VERSION 5.8 ;
BUSBITCHARS "[]" ;
DIVIDERCHAR "/" ;
UNITS
    DATABASE MICRONS 1000 ;
END UNITS

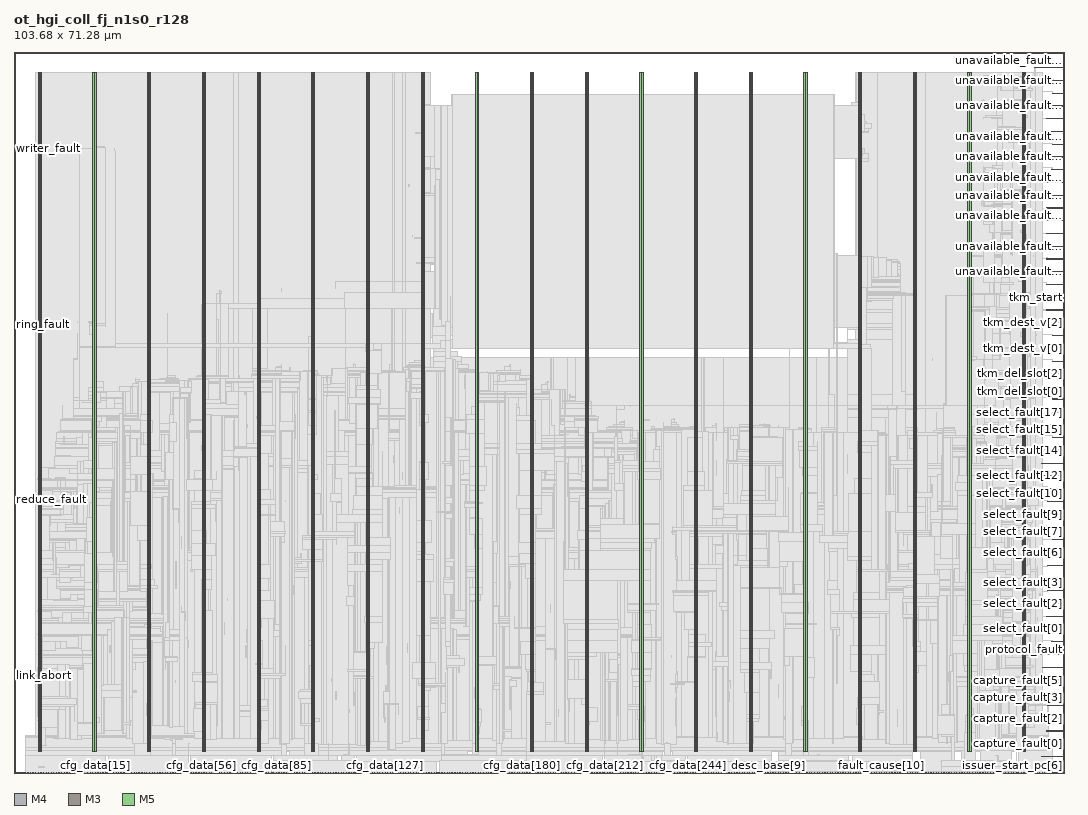
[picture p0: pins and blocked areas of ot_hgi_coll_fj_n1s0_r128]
MACRO ot_hgi_coll_fj_n1s0_r128
  FOREIGN ot_hgi_coll_fj_n1s0_r128 0 0 ;
  CLASS BLOCK ;
  SIZE 103.68 BY 71.28 ;
  PIN arg_capture_slot
    DIRECTION INPUT ;
    USE SIGNAL ;
    PORT
      LAYER M4 ;
        RECT  103.596 1.632 103.68 1.656 ;
    END
    PORT
      LAYER M4 ;
        RECT  101.437 1.632 103.644 1.656 ;
    END
  END arg_capture_slot
  PIN capture_fault[0]
    DIRECTION INPUT ;
    USE SIGNAL ;
    PORT
      LAYER M4 ;
        RECT  103.596 2.88 103.68 2.904 ;
    END
    PORT
      LAYER M4 ;
        RECT  102.013 2.88 103.644 2.904 ;
    END
  END capture_fault[0]
  PIN capture_fault[1]
    DIRECTION INPUT ;
    USE SIGNAL ;
    PORT
      LAYER M4 ;
        RECT  103.596 4.128 103.68 4.152 ;
    END
    PORT
      LAYER M4 ;
        RECT  101.977 4.128 103.644 4.152 ;
    END
  END capture_fault[1]
  PIN capture_fault[2]
    DIRECTION INPUT ;
    USE SIGNAL ;
    PORT
      LAYER M4 ;
        RECT  103.596 5.376 103.68 5.4 ;
    END
    PORT
      LAYER M4 ;
        RECT  102.553 5.376 103.644 5.4 ;
    END
  END capture_fault[2]
  PIN capture_fault[3]
    DIRECTION INPUT ;
    USE SIGNAL ;
    PORT
      LAYER M4 ;
        RECT  103.596 6.672 103.68 6.696 ;
    END
    PORT
      LAYER M4 ;
        RECT  102.013 6.672 103.644 6.696 ;
    END
  END capture_fault[3]
  PIN capture_fault[4]
    DIRECTION INPUT ;
    USE SIGNAL ;
    PORT
      LAYER M4 ;
        RECT  103.596 7.92 103.68 7.944 ;
    END
    PORT
      LAYER M4 ;
        RECT  101.977 7.92 103.644 7.944 ;
    END
  END capture_fault[4]
  PIN capture_fault[5]
    DIRECTION INPUT ;
    USE SIGNAL ;
    PORT
      LAYER M4 ;
        RECT  103.596 9.168 103.68 9.192 ;
    END
    PORT
      LAYER M4 ;
        RECT  101.905 9.168 103.644 9.192 ;
    END
  END capture_fault[5]
  PIN capture_fault[6]
    DIRECTION INPUT ;
    USE SIGNAL ;
    PORT
      LAYER M4 ;
        RECT  103.596 10.416 103.68 10.44 ;
    END
    PORT
      LAYER M4 ;
        RECT  101.509 10.416 103.644 10.44 ;
    END
  END capture_fault[6]
  PIN capture_fault[7]
    DIRECTION INPUT ;
    USE SIGNAL ;
    PORT
      LAYER M4 ;
        RECT  103.596 11.712 103.68 11.736 ;
    END
    PORT
      LAYER M4 ;
        RECT  101.365 11.712 103.644 11.736 ;
    END
  END capture_fault[7]
  PIN cfg_addr[0]
    DIRECTION INPUT ;
    USE SIGNAL ;
    PORT
      LAYER M3 ;
        RECT  1.116 0 1.134 0.038 ;
    END
  END cfg_addr[0]
  PIN cfg_addr[10]
    DIRECTION INPUT ;
    USE SIGNAL ;
    PORT
      LAYER M3 ;
        RECT  3.672 0 3.69 0.038 ;
    END
  END cfg_addr[10]
  PIN cfg_addr[11]
    DIRECTION INPUT ;
    USE SIGNAL ;
    PORT
      LAYER M3 ;
        RECT  3.924 0 3.942 0.038 ;
    END
  END cfg_addr[11]
  PIN cfg_addr[1]
    DIRECTION INPUT ;
    USE SIGNAL ;
    PORT
      LAYER M3 ;
        RECT  1.368 0 1.386 0.038 ;
    END
  END cfg_addr[1]
  PIN cfg_addr[2]
    DIRECTION INPUT ;
    USE SIGNAL ;
    PORT
      LAYER M3 ;
        RECT  1.62 0 1.638 0.038 ;
    END
  END cfg_addr[2]
  PIN cfg_addr[3]
    DIRECTION INPUT ;
    USE SIGNAL ;
    PORT
      LAYER M3 ;
        RECT  1.872 0 1.89 0.038 ;
    END
  END cfg_addr[3]
  PIN cfg_addr[4]
    DIRECTION INPUT ;
    USE SIGNAL ;
    PORT
      LAYER M3 ;
        RECT  2.124 0 2.142 0.038 ;
    END
  END cfg_addr[4]
  PIN cfg_addr[5]
    DIRECTION INPUT ;
    USE SIGNAL ;
    PORT
      LAYER M3 ;
        RECT  2.412 0 2.43 0.038 ;
    END
  END cfg_addr[5]
  PIN cfg_addr[6]
    DIRECTION INPUT ;
    USE SIGNAL ;
    PORT
      LAYER M3 ;
        RECT  2.664 0 2.682 0.038 ;
    END
  END cfg_addr[6]
  PIN cfg_addr[7]
    DIRECTION INPUT ;
    USE SIGNAL ;
    PORT
      LAYER M3 ;
        RECT  2.916 0 2.934 0.038 ;
    END
  END cfg_addr[7]
  PIN cfg_addr[8]
    DIRECTION INPUT ;
    USE SIGNAL ;
    PORT
      LAYER M3 ;
        RECT  3.168 0 3.186 0.038 ;
    END
  END cfg_addr[8]
  PIN cfg_addr[9]
    DIRECTION INPUT ;
    USE SIGNAL ;
    PORT
      LAYER M3 ;
        RECT  3.42 0 3.438 0.038 ;
    END
  END cfg_addr[9]
  PIN cfg_data[0]
    DIRECTION INPUT ;
    USE SIGNAL ;
    PORT
      LAYER M3 ;
        RECT  4.176 0 4.194 0.038 ;
    END
  END cfg_data[0]
  PIN cfg_data[100]
    DIRECTION INPUT ;
    USE SIGNAL ;
    PORT
      LAYER M5 ;
        RECT  29.712 0 29.736 0.084 ;
    END
  END cfg_data[100]
  PIN cfg_data[101]
    DIRECTION INPUT ;
    USE SIGNAL ;
    PORT
      LAYER M5 ;
        RECT  30 0 30.024 0.084 ;
    END
  END cfg_data[101]
  PIN cfg_data[102]
    DIRECTION INPUT ;
    USE SIGNAL ;
    PORT
      LAYER M5 ;
        RECT  30.24 0 30.264 0.084 ;
    END
  END cfg_data[102]
  PIN cfg_data[103]
    DIRECTION INPUT ;
    USE SIGNAL ;
    PORT
      LAYER M5 ;
        RECT  30.48 0 30.504 0.084 ;
    END
  END cfg_data[103]
  PIN cfg_data[104]
    DIRECTION INPUT ;
    USE SIGNAL ;
    PORT
      LAYER M5 ;
        RECT  30.768 0 30.792 0.084 ;
    END
  END cfg_data[104]
  PIN cfg_data[105]
    DIRECTION INPUT ;
    USE SIGNAL ;
    PORT
      LAYER M5 ;
        RECT  31.008 0 31.032 0.084 ;
    END
  END cfg_data[105]
  PIN cfg_data[106]
    DIRECTION INPUT ;
    USE SIGNAL ;
    PORT
      LAYER M5 ;
        RECT  31.248 0 31.272 0.084 ;
    END
  END cfg_data[106]
  PIN cfg_data[107]
    DIRECTION INPUT ;
    USE SIGNAL ;
    PORT
      LAYER M5 ;
        RECT  31.536 0 31.56 0.084 ;
    END
  END cfg_data[107]
  PIN cfg_data[108]
    DIRECTION INPUT ;
    USE SIGNAL ;
    PORT
      LAYER M5 ;
        RECT  31.776 0 31.8 0.084 ;
    END
  END cfg_data[108]
  PIN cfg_data[109]
    DIRECTION INPUT ;
    USE SIGNAL ;
    PORT
      LAYER M5 ;
        RECT  32.016 0 32.04 0.084 ;
    END
  END cfg_data[109]
  PIN cfg_data[10]
    DIRECTION INPUT ;
    USE SIGNAL ;
    PORT
      LAYER M3 ;
        RECT  6.732 0 6.75 0.038 ;
    END
  END cfg_data[10]
  PIN cfg_data[110]
    DIRECTION INPUT ;
    USE SIGNAL ;
    PORT
      LAYER M5 ;
        RECT  32.304 0 32.328 0.084 ;
    END
  END cfg_data[110]
  PIN cfg_data[111]
    DIRECTION INPUT ;
    USE SIGNAL ;
    PORT
      LAYER M5 ;
        RECT  32.544 0 32.568 0.084 ;
    END
  END cfg_data[111]
  PIN cfg_data[112]
    DIRECTION INPUT ;
    USE SIGNAL ;
    PORT
      LAYER M5 ;
        RECT  32.784 0 32.808 0.084 ;
    END
  END cfg_data[112]
  PIN cfg_data[113]
    DIRECTION INPUT ;
    USE SIGNAL ;
    PORT
      LAYER M5 ;
        RECT  33.072 0 33.096 0.084 ;
    END
  END cfg_data[113]
  PIN cfg_data[114]
    DIRECTION INPUT ;
    USE SIGNAL ;
    PORT
      LAYER M5 ;
        RECT  33.312 0 33.336 0.084 ;
    END
  END cfg_data[114]
  PIN cfg_data[115]
    DIRECTION INPUT ;
    USE SIGNAL ;
    PORT
      LAYER M5 ;
        RECT  33.552 0 33.576 0.084 ;
    END
  END cfg_data[115]
  PIN cfg_data[116]
    DIRECTION INPUT ;
    USE SIGNAL ;
    PORT
      LAYER M3 ;
        RECT  33.804 0 33.822 0.038 ;
    END
  END cfg_data[116]
  PIN cfg_data[117]
    DIRECTION INPUT ;
    USE SIGNAL ;
    PORT
      LAYER M3 ;
        RECT  34.092 0 34.11 0.038 ;
    END
  END cfg_data[117]
  PIN cfg_data[118]
    DIRECTION INPUT ;
    USE SIGNAL ;
    PORT
      LAYER M3 ;
        RECT  34.344 0 34.362 0.038 ;
    END
  END cfg_data[118]
  PIN cfg_data[119]
    DIRECTION INPUT ;
    USE SIGNAL ;
    PORT
      LAYER M3 ;
        RECT  34.596 0 34.614 0.038 ;
    END
  END cfg_data[119]
  PIN cfg_data[11]
    DIRECTION INPUT ;
    USE SIGNAL ;
    PORT
      LAYER M3 ;
        RECT  6.984 0 7.002 0.038 ;
    END
  END cfg_data[11]
  PIN cfg_data[120]
    DIRECTION INPUT ;
    USE SIGNAL ;
    PORT
      LAYER M3 ;
        RECT  34.848 0 34.866 0.038 ;
    END
  END cfg_data[120]
  PIN cfg_data[121]
    DIRECTION INPUT ;
    USE SIGNAL ;
    PORT
      LAYER M3 ;
        RECT  35.1 0 35.118 0.038 ;
    END
  END cfg_data[121]
  PIN cfg_data[122]
    DIRECTION INPUT ;
    USE SIGNAL ;
    PORT
      LAYER M3 ;
        RECT  35.352 0 35.37 0.038 ;
    END
  END cfg_data[122]
  PIN cfg_data[123]
    DIRECTION INPUT ;
    USE SIGNAL ;
    PORT
      LAYER M3 ;
        RECT  35.604 0 35.622 0.038 ;
    END
  END cfg_data[123]
  PIN cfg_data[124]
    DIRECTION INPUT ;
    USE SIGNAL ;
    PORT
      LAYER M3 ;
        RECT  35.856 0 35.874 0.038 ;
    END
  END cfg_data[124]
  PIN cfg_data[125]
    DIRECTION INPUT ;
    USE SIGNAL ;
    PORT
      LAYER M3 ;
        RECT  36.108 0 36.126 0.038 ;
    END
  END cfg_data[125]
  PIN cfg_data[126]
    DIRECTION INPUT ;
    USE SIGNAL ;
    PORT
      LAYER M3 ;
        RECT  36.36 0 36.378 0.038 ;
    END
  END cfg_data[126]
  PIN cfg_data[127]
    DIRECTION INPUT ;
    USE SIGNAL ;
    PORT
      LAYER M3 ;
        RECT  36.648 0 36.666 0.038 ;
    END
  END cfg_data[127]
  PIN cfg_data[128]
    DIRECTION INPUT ;
    USE SIGNAL ;
    PORT
      LAYER M3 ;
        RECT  36.9 0 36.918 0.038 ;
    END
  END cfg_data[128]
  PIN cfg_data[129]
    DIRECTION INPUT ;
    USE SIGNAL ;
    PORT
      LAYER M3 ;
        RECT  37.152 0 37.17 0.038 ;
    END
  END cfg_data[129]
  PIN cfg_data[12]
    DIRECTION INPUT ;
    USE SIGNAL ;
    PORT
      LAYER M3 ;
        RECT  7.236 0 7.254 0.038 ;
    END
  END cfg_data[12]
  PIN cfg_data[130]
    DIRECTION INPUT ;
    USE SIGNAL ;
    PORT
      LAYER M3 ;
        RECT  37.404 0 37.422 0.038 ;
    END
  END cfg_data[130]
  PIN cfg_data[131]
    DIRECTION INPUT ;
    USE SIGNAL ;
    PORT
      LAYER M3 ;
        RECT  37.656 0 37.674 0.038 ;
    END
  END cfg_data[131]
  PIN cfg_data[132]
    DIRECTION INPUT ;
    USE SIGNAL ;
    PORT
      LAYER M3 ;
        RECT  37.908 0 37.926 0.038 ;
    END
  END cfg_data[132]
  PIN cfg_data[133]
    DIRECTION INPUT ;
    USE SIGNAL ;
    PORT
      LAYER M3 ;
        RECT  38.16 0 38.178 0.038 ;
    END
  END cfg_data[133]
  PIN cfg_data[134]
    DIRECTION INPUT ;
    USE SIGNAL ;
    PORT
      LAYER M3 ;
        RECT  38.412 0 38.43 0.038 ;
    END
  END cfg_data[134]
  PIN cfg_data[135]
    DIRECTION INPUT ;
    USE SIGNAL ;
    PORT
      LAYER M3 ;
        RECT  38.664 0 38.682 0.038 ;
    END
  END cfg_data[135]
  PIN cfg_data[136]
    DIRECTION INPUT ;
    USE SIGNAL ;
    PORT
      LAYER M3 ;
        RECT  38.916 0 38.934 0.038 ;
    END
  END cfg_data[136]
  PIN cfg_data[137]
    DIRECTION INPUT ;
    USE SIGNAL ;
    PORT
      LAYER M3 ;
        RECT  39.168 0 39.186 0.038 ;
    END
  END cfg_data[137]
  PIN cfg_data[138]
    DIRECTION INPUT ;
    USE SIGNAL ;
    PORT
      LAYER M3 ;
        RECT  39.456 0 39.474 0.038 ;
    END
  END cfg_data[138]
  PIN cfg_data[139]
    DIRECTION INPUT ;
    USE SIGNAL ;
    PORT
      LAYER M3 ;
        RECT  39.708 0 39.726 0.038 ;
    END
  END cfg_data[139]
  PIN cfg_data[13]
    DIRECTION INPUT ;
    USE SIGNAL ;
    PORT
      LAYER M3 ;
        RECT  7.524 0 7.542 0.038 ;
    END
  END cfg_data[13]
  PIN cfg_data[140]
    DIRECTION INPUT ;
    USE SIGNAL ;
    PORT
      LAYER M3 ;
        RECT  39.96 0 39.978 0.038 ;
    END
  END cfg_data[140]
  PIN cfg_data[141]
    DIRECTION INPUT ;
    USE SIGNAL ;
    PORT
      LAYER M3 ;
        RECT  40.212 0 40.23 0.038 ;
    END
  END cfg_data[141]
  PIN cfg_data[142]
    DIRECTION INPUT ;
    USE SIGNAL ;
    PORT
      LAYER M3 ;
        RECT  40.464 0 40.482 0.038 ;
    END
  END cfg_data[142]
  PIN cfg_data[143]
    DIRECTION INPUT ;
    USE SIGNAL ;
    PORT
      LAYER M3 ;
        RECT  40.716 0 40.734 0.038 ;
    END
  END cfg_data[143]
  PIN cfg_data[144]
    DIRECTION INPUT ;
    USE SIGNAL ;
    PORT
      LAYER M3 ;
        RECT  40.968 0 40.986 0.038 ;
    END
  END cfg_data[144]
  PIN cfg_data[145]
    DIRECTION INPUT ;
    USE SIGNAL ;
    PORT
      LAYER M3 ;
        RECT  41.22 0 41.238 0.038 ;
    END
  END cfg_data[145]
  PIN cfg_data[146]
    DIRECTION INPUT ;
    USE SIGNAL ;
    PORT
      LAYER M3 ;
        RECT  41.472 0 41.49 0.038 ;
    END
  END cfg_data[146]
  PIN cfg_data[147]
    DIRECTION INPUT ;
    USE SIGNAL ;
    PORT
      LAYER M3 ;
        RECT  41.724 0 41.742 0.038 ;
    END
  END cfg_data[147]
  PIN cfg_data[148]
    DIRECTION INPUT ;
    USE SIGNAL ;
    PORT
      LAYER M5 ;
        RECT  42 0 42.024 0.084 ;
    END
  END cfg_data[148]
  PIN cfg_data[149]
    DIRECTION INPUT ;
    USE SIGNAL ;
    PORT
      LAYER M5 ;
        RECT  42.24 0 42.264 0.084 ;
    END
  END cfg_data[149]
  PIN cfg_data[14]
    DIRECTION INPUT ;
    USE SIGNAL ;
    PORT
      LAYER M3 ;
        RECT  7.776 0 7.794 0.038 ;
    END
  END cfg_data[14]
  PIN cfg_data[150]
    DIRECTION INPUT ;
    USE SIGNAL ;
    PORT
      LAYER M5 ;
        RECT  42.48 0 42.504 0.084 ;
    END
  END cfg_data[150]
  PIN cfg_data[151]
    DIRECTION INPUT ;
    USE SIGNAL ;
    PORT
      LAYER M5 ;
        RECT  42.768 0 42.792 0.084 ;
    END
  END cfg_data[151]
  PIN cfg_data[152]
    DIRECTION INPUT ;
    USE SIGNAL ;
    PORT
      LAYER M5 ;
        RECT  43.008 0 43.032 0.084 ;
    END
  END cfg_data[152]
  PIN cfg_data[153]
    DIRECTION INPUT ;
    USE SIGNAL ;
    PORT
      LAYER M5 ;
        RECT  43.248 0 43.272 0.084 ;
    END
  END cfg_data[153]
  PIN cfg_data[154]
    DIRECTION INPUT ;
    USE SIGNAL ;
    PORT
      LAYER M5 ;
        RECT  43.536 0 43.56 0.084 ;
    END
  END cfg_data[154]
  PIN cfg_data[155]
    DIRECTION INPUT ;
    USE SIGNAL ;
    PORT
      LAYER M5 ;
        RECT  43.776 0 43.8 0.084 ;
    END
  END cfg_data[155]
  PIN cfg_data[156]
    DIRECTION INPUT ;
    USE SIGNAL ;
    PORT
      LAYER M5 ;
        RECT  44.016 0 44.04 0.084 ;
    END
  END cfg_data[156]
  PIN cfg_data[157]
    DIRECTION INPUT ;
    USE SIGNAL ;
    PORT
      LAYER M5 ;
        RECT  44.304 0 44.328 0.084 ;
    END
  END cfg_data[157]
  PIN cfg_data[158]
    DIRECTION INPUT ;
    USE SIGNAL ;
    PORT
      LAYER M5 ;
        RECT  44.544 0 44.568 0.084 ;
    END
  END cfg_data[158]
  PIN cfg_data[159]
    DIRECTION INPUT ;
    USE SIGNAL ;
    PORT
      LAYER M5 ;
        RECT  44.784 0 44.808 0.084 ;
    END
  END cfg_data[159]
  PIN cfg_data[15]
    DIRECTION INPUT ;
    USE SIGNAL ;
    PORT
      LAYER M3 ;
        RECT  8.028 0 8.046 0.038 ;
    END
  END cfg_data[15]
  PIN cfg_data[160]
    DIRECTION INPUT ;
    USE SIGNAL ;
    PORT
      LAYER M5 ;
        RECT  45.072 0 45.096 0.084 ;
    END
  END cfg_data[160]
  PIN cfg_data[161]
    DIRECTION INPUT ;
    USE SIGNAL ;
    PORT
      LAYER M5 ;
        RECT  45.312 0 45.336 0.084 ;
    END
  END cfg_data[161]
  PIN cfg_data[162]
    DIRECTION INPUT ;
    USE SIGNAL ;
    PORT
      LAYER M5 ;
        RECT  45.552 0 45.576 0.084 ;
    END
  END cfg_data[162]
  PIN cfg_data[163]
    DIRECTION INPUT ;
    USE SIGNAL ;
    PORT
      LAYER M5 ;
        RECT  45.84 0 45.864 0.084 ;
    END
  END cfg_data[163]
  PIN cfg_data[164]
    DIRECTION INPUT ;
    USE SIGNAL ;
    PORT
      LAYER M5 ;
        RECT  46.08 0 46.104 0.084 ;
    END
  END cfg_data[164]
  PIN cfg_data[165]
    DIRECTION INPUT ;
    USE SIGNAL ;
    PORT
      LAYER M5 ;
        RECT  46.32 0 46.344 0.084 ;
    END
  END cfg_data[165]
  PIN cfg_data[166]
    DIRECTION INPUT ;
    USE SIGNAL ;
    PORT
      LAYER M5 ;
        RECT  46.608 0 46.632 0.084 ;
    END
  END cfg_data[166]
  PIN cfg_data[167]
    DIRECTION INPUT ;
    USE SIGNAL ;
    PORT
      LAYER M5 ;
        RECT  46.848 0 46.872 0.084 ;
    END
  END cfg_data[167]
  PIN cfg_data[168]
    DIRECTION INPUT ;
    USE SIGNAL ;
    PORT
      LAYER M5 ;
        RECT  47.088 0 47.112 0.084 ;
    END
  END cfg_data[168]
  PIN cfg_data[169]
    DIRECTION INPUT ;
    USE SIGNAL ;
    PORT
      LAYER M5 ;
        RECT  47.376 0 47.4 0.084 ;
    END
  END cfg_data[169]
  PIN cfg_data[16]
    DIRECTION INPUT ;
    USE SIGNAL ;
    PORT
      LAYER M3 ;
        RECT  8.28 0 8.298 0.038 ;
    END
  END cfg_data[16]
  PIN cfg_data[170]
    DIRECTION INPUT ;
    USE SIGNAL ;
    PORT
      LAYER M5 ;
        RECT  47.616 0 47.64 0.084 ;
    END
  END cfg_data[170]
  PIN cfg_data[171]
    DIRECTION INPUT ;
    USE SIGNAL ;
    PORT
      LAYER M5 ;
        RECT  47.856 0 47.88 0.084 ;
    END
  END cfg_data[171]
  PIN cfg_data[172]
    DIRECTION INPUT ;
    USE SIGNAL ;
    PORT
      LAYER M5 ;
        RECT  48.144 0 48.168 0.084 ;
    END
  END cfg_data[172]
  PIN cfg_data[173]
    DIRECTION INPUT ;
    USE SIGNAL ;
    PORT
      LAYER M5 ;
        RECT  48.384 0 48.408 0.084 ;
    END
  END cfg_data[173]
  PIN cfg_data[174]
    DIRECTION INPUT ;
    USE SIGNAL ;
    PORT
      LAYER M5 ;
        RECT  48.624 0 48.648 0.084 ;
    END
  END cfg_data[174]
  PIN cfg_data[175]
    DIRECTION INPUT ;
    USE SIGNAL ;
    PORT
      LAYER M5 ;
        RECT  48.912 0 48.936 0.084 ;
    END
  END cfg_data[175]
  PIN cfg_data[176]
    DIRECTION INPUT ;
    USE SIGNAL ;
    PORT
      LAYER M5 ;
        RECT  49.152 0 49.176 0.084 ;
    END
  END cfg_data[176]
  PIN cfg_data[177]
    DIRECTION INPUT ;
    USE SIGNAL ;
    PORT
      LAYER M5 ;
        RECT  49.392 0 49.416 0.084 ;
    END
  END cfg_data[177]
  PIN cfg_data[178]
    DIRECTION INPUT ;
    USE SIGNAL ;
    PORT
      LAYER M5 ;
        RECT  49.68 0 49.704 0.084 ;
    END
  END cfg_data[178]
  PIN cfg_data[179]
    DIRECTION INPUT ;
    USE SIGNAL ;
    PORT
      LAYER M5 ;
        RECT  49.92 0 49.944 0.084 ;
    END
  END cfg_data[179]
  PIN cfg_data[17]
    DIRECTION INPUT ;
    USE SIGNAL ;
    PORT
      LAYER M3 ;
        RECT  8.532 0 8.55 0.038 ;
    END
  END cfg_data[17]
  PIN cfg_data[180]
    DIRECTION INPUT ;
    USE SIGNAL ;
    PORT
      LAYER M3 ;
        RECT  50.184 0 50.202 0.038 ;
    END
  END cfg_data[180]
  PIN cfg_data[181]
    DIRECTION INPUT ;
    USE SIGNAL ;
    PORT
      LAYER M3 ;
        RECT  50.436 0 50.454 0.038 ;
    END
  END cfg_data[181]
  PIN cfg_data[182]
    DIRECTION INPUT ;
    USE SIGNAL ;
    PORT
      LAYER M3 ;
        RECT  50.688 0 50.706 0.038 ;
    END
  END cfg_data[182]
  PIN cfg_data[183]
    DIRECTION INPUT ;
    USE SIGNAL ;
    PORT
      LAYER M3 ;
        RECT  50.94 0 50.958 0.038 ;
    END
  END cfg_data[183]
  PIN cfg_data[184]
    DIRECTION INPUT ;
    USE SIGNAL ;
    PORT
      LAYER M3 ;
        RECT  51.192 0 51.21 0.038 ;
    END
  END cfg_data[184]
  PIN cfg_data[185]
    DIRECTION INPUT ;
    USE SIGNAL ;
    PORT
      LAYER M3 ;
        RECT  51.444 0 51.462 0.038 ;
    END
  END cfg_data[185]
  PIN cfg_data[186]
    DIRECTION INPUT ;
    USE SIGNAL ;
    PORT
      LAYER M3 ;
        RECT  51.696 0 51.714 0.038 ;
    END
  END cfg_data[186]
  PIN cfg_data[187]
    DIRECTION INPUT ;
    USE SIGNAL ;
    PORT
      LAYER M3 ;
        RECT  51.948 0 51.966 0.038 ;
    END
  END cfg_data[187]
  PIN cfg_data[188]
    DIRECTION INPUT ;
    USE SIGNAL ;
    PORT
      LAYER M3 ;
        RECT  52.2 0 52.218 0.038 ;
    END
  END cfg_data[188]
  PIN cfg_data[189]
    DIRECTION INPUT ;
    USE SIGNAL ;
    PORT
      LAYER M3 ;
        RECT  52.488 0 52.506 0.038 ;
    END
  END cfg_data[189]
  PIN cfg_data[18]
    DIRECTION INPUT ;
    USE SIGNAL ;
    PORT
      LAYER M3 ;
        RECT  8.784 0 8.802 0.038 ;
    END
  END cfg_data[18]
  PIN cfg_data[190]
    DIRECTION INPUT ;
    USE SIGNAL ;
    PORT
      LAYER M3 ;
        RECT  52.74 0 52.758 0.038 ;
    END
  END cfg_data[190]
  PIN cfg_data[191]
    DIRECTION INPUT ;
    USE SIGNAL ;
    PORT
      LAYER M3 ;
        RECT  52.992 0 53.01 0.038 ;
    END
  END cfg_data[191]
  PIN cfg_data[192]
    DIRECTION INPUT ;
    USE SIGNAL ;
    PORT
      LAYER M3 ;
        RECT  53.244 0 53.262 0.038 ;
    END
  END cfg_data[192]
  PIN cfg_data[193]
    DIRECTION INPUT ;
    USE SIGNAL ;
    PORT
      LAYER M3 ;
        RECT  53.496 0 53.514 0.038 ;
    END
  END cfg_data[193]
  PIN cfg_data[194]
    DIRECTION INPUT ;
    USE SIGNAL ;
    PORT
      LAYER M3 ;
        RECT  53.748 0 53.766 0.038 ;
    END
  END cfg_data[194]
  PIN cfg_data[195]
    DIRECTION INPUT ;
    USE SIGNAL ;
    PORT
      LAYER M3 ;
        RECT  54 0 54.018 0.038 ;
    END
  END cfg_data[195]
  PIN cfg_data[196]
    DIRECTION INPUT ;
    USE SIGNAL ;
    PORT
      LAYER M3 ;
        RECT  54.252 0 54.27 0.038 ;
    END
  END cfg_data[196]
  PIN cfg_data[197]
    DIRECTION INPUT ;
    USE SIGNAL ;
    PORT
      LAYER M3 ;
        RECT  54.504 0 54.522 0.038 ;
    END
  END cfg_data[197]
  PIN cfg_data[198]
    DIRECTION INPUT ;
    USE SIGNAL ;
    PORT
      LAYER M3 ;
        RECT  54.756 0 54.774 0.038 ;
    END
  END cfg_data[198]
  PIN cfg_data[199]
    DIRECTION INPUT ;
    USE SIGNAL ;
    PORT
      LAYER M3 ;
        RECT  55.008 0 55.026 0.038 ;
    END
  END cfg_data[199]
  PIN cfg_data[19]
    DIRECTION INPUT ;
    USE SIGNAL ;
    PORT
      LAYER M3 ;
        RECT  9.036 0 9.054 0.038 ;
    END
  END cfg_data[19]
  PIN cfg_data[1]
    DIRECTION INPUT ;
    USE SIGNAL ;
    PORT
      LAYER M3 ;
        RECT  4.428 0 4.446 0.038 ;
    END
  END cfg_data[1]
  PIN cfg_data[200]
    DIRECTION INPUT ;
    USE SIGNAL ;
    PORT
      LAYER M3 ;
        RECT  55.296 0 55.314 0.038 ;
    END
  END cfg_data[200]
  PIN cfg_data[201]
    DIRECTION INPUT ;
    USE SIGNAL ;
    PORT
      LAYER M3 ;
        RECT  55.548 0 55.566 0.038 ;
    END
  END cfg_data[201]
  PIN cfg_data[202]
    DIRECTION INPUT ;
    USE SIGNAL ;
    PORT
      LAYER M3 ;
        RECT  55.8 0 55.818 0.038 ;
    END
  END cfg_data[202]
  PIN cfg_data[203]
    DIRECTION INPUT ;
    USE SIGNAL ;
    PORT
      LAYER M3 ;
        RECT  56.052 0 56.07 0.038 ;
    END
  END cfg_data[203]
  PIN cfg_data[204]
    DIRECTION INPUT ;
    USE SIGNAL ;
    PORT
      LAYER M3 ;
        RECT  56.304 0 56.322 0.038 ;
    END
  END cfg_data[204]
  PIN cfg_data[205]
    DIRECTION INPUT ;
    USE SIGNAL ;
    PORT
      LAYER M3 ;
        RECT  56.556 0 56.574 0.038 ;
    END
  END cfg_data[205]
  PIN cfg_data[206]
    DIRECTION INPUT ;
    USE SIGNAL ;
    PORT
      LAYER M3 ;
        RECT  56.808 0 56.826 0.038 ;
    END
  END cfg_data[206]
  PIN cfg_data[207]
    DIRECTION INPUT ;
    USE SIGNAL ;
    PORT
      LAYER M3 ;
        RECT  57.06 0 57.078 0.038 ;
    END
  END cfg_data[207]
  PIN cfg_data[208]
    DIRECTION INPUT ;
    USE SIGNAL ;
    PORT
      LAYER M3 ;
        RECT  57.312 0 57.33 0.038 ;
    END
  END cfg_data[208]
  PIN cfg_data[209]
    DIRECTION INPUT ;
    USE SIGNAL ;
    PORT
      LAYER M3 ;
        RECT  57.564 0 57.582 0.038 ;
    END
  END cfg_data[209]
  PIN cfg_data[20]
    DIRECTION INPUT ;
    USE SIGNAL ;
    PORT
      LAYER M5 ;
        RECT  9.312 0 9.336 0.084 ;
    END
  END cfg_data[20]
  PIN cfg_data[210]
    DIRECTION INPUT ;
    USE SIGNAL ;
    PORT
      LAYER M3 ;
        RECT  57.852 0 57.87 0.038 ;
    END
  END cfg_data[210]
  PIN cfg_data[211]
    DIRECTION INPUT ;
    USE SIGNAL ;
    PORT
      LAYER M3 ;
        RECT  58.104 0 58.122 0.038 ;
    END
  END cfg_data[211]
  PIN cfg_data[212]
    DIRECTION INPUT ;
    USE SIGNAL ;
    PORT
      LAYER M5 ;
        RECT  58.32 0 58.344 0.084 ;
    END
  END cfg_data[212]
  PIN cfg_data[213]
    DIRECTION INPUT ;
    USE SIGNAL ;
    PORT
      LAYER M5 ;
        RECT  58.608 0 58.632 0.084 ;
    END
  END cfg_data[213]
  PIN cfg_data[214]
    DIRECTION INPUT ;
    USE SIGNAL ;
    PORT
      LAYER M5 ;
        RECT  58.848 0 58.872 0.084 ;
    END
  END cfg_data[214]
  PIN cfg_data[215]
    DIRECTION INPUT ;
    USE SIGNAL ;
    PORT
      LAYER M5 ;
        RECT  59.088 0 59.112 0.084 ;
    END
  END cfg_data[215]
  PIN cfg_data[216]
    DIRECTION INPUT ;
    USE SIGNAL ;
    PORT
      LAYER M5 ;
        RECT  59.376 0 59.4 0.084 ;
    END
  END cfg_data[216]
  PIN cfg_data[217]
    DIRECTION INPUT ;
    USE SIGNAL ;
    PORT
      LAYER M5 ;
        RECT  59.616 0 59.64 0.084 ;
    END
  END cfg_data[217]
  PIN cfg_data[218]
    DIRECTION INPUT ;
    USE SIGNAL ;
    PORT
      LAYER M5 ;
        RECT  59.856 0 59.88 0.084 ;
    END
  END cfg_data[218]
  PIN cfg_data[219]
    DIRECTION INPUT ;
    USE SIGNAL ;
    PORT
      LAYER M5 ;
        RECT  60.144 0 60.168 0.084 ;
    END
  END cfg_data[219]
  PIN cfg_data[21]
    DIRECTION INPUT ;
    USE SIGNAL ;
    PORT
      LAYER M5 ;
        RECT  9.552 0 9.576 0.084 ;
    END
  END cfg_data[21]
  PIN cfg_data[220]
    DIRECTION INPUT ;
    USE SIGNAL ;
    PORT
      LAYER M5 ;
        RECT  60.384 0 60.408 0.084 ;
    END
  END cfg_data[220]
  PIN cfg_data[221]
    DIRECTION INPUT ;
    USE SIGNAL ;
    PORT
      LAYER M5 ;
        RECT  60.624 0 60.648 0.084 ;
    END
  END cfg_data[221]
  PIN cfg_data[222]
    DIRECTION INPUT ;
    USE SIGNAL ;
    PORT
      LAYER M5 ;
        RECT  60.912 0 60.936 0.084 ;
    END
  END cfg_data[222]
  PIN cfg_data[223]
    DIRECTION INPUT ;
    USE SIGNAL ;
    PORT
      LAYER M5 ;
        RECT  61.152 0 61.176 0.084 ;
    END
  END cfg_data[223]
  PIN cfg_data[224]
    DIRECTION INPUT ;
    USE SIGNAL ;
    PORT
      LAYER M5 ;
        RECT  61.392 0 61.416 0.084 ;
    END
  END cfg_data[224]
  PIN cfg_data[225]
    DIRECTION INPUT ;
    USE SIGNAL ;
    PORT
      LAYER M5 ;
        RECT  61.68 0 61.704 0.084 ;
    END
  END cfg_data[225]
  PIN cfg_data[226]
    DIRECTION INPUT ;
    USE SIGNAL ;
    PORT
      LAYER M5 ;
        RECT  61.92 0 61.944 0.084 ;
    END
  END cfg_data[226]
  PIN cfg_data[227]
    DIRECTION INPUT ;
    USE SIGNAL ;
    PORT
      LAYER M5 ;
        RECT  62.16 0 62.184 0.084 ;
    END
  END cfg_data[227]
  PIN cfg_data[228]
    DIRECTION INPUT ;
    USE SIGNAL ;
    PORT
      LAYER M5 ;
        RECT  62.448 0 62.472 0.084 ;
    END
  END cfg_data[228]
  PIN cfg_data[229]
    DIRECTION INPUT ;
    USE SIGNAL ;
    PORT
      LAYER M5 ;
        RECT  62.688 0 62.712 0.084 ;
    END
  END cfg_data[229]
  PIN cfg_data[22]
    DIRECTION INPUT ;
    USE SIGNAL ;
    PORT
      LAYER M5 ;
        RECT  9.792 0 9.816 0.084 ;
    END
  END cfg_data[22]
  PIN cfg_data[230]
    DIRECTION INPUT ;
    USE SIGNAL ;
    PORT
      LAYER M5 ;
        RECT  62.928 0 62.952 0.084 ;
    END
  END cfg_data[230]
  PIN cfg_data[231]
    DIRECTION INPUT ;
    USE SIGNAL ;
    PORT
      LAYER M5 ;
        RECT  63.216 0 63.24 0.084 ;
    END
  END cfg_data[231]
  PIN cfg_data[232]
    DIRECTION INPUT ;
    USE SIGNAL ;
    PORT
      LAYER M5 ;
        RECT  63.456 0 63.48 0.084 ;
    END
  END cfg_data[232]
  PIN cfg_data[233]
    DIRECTION INPUT ;
    USE SIGNAL ;
    PORT
      LAYER M5 ;
        RECT  63.696 0 63.72 0.084 ;
    END
  END cfg_data[233]
  PIN cfg_data[234]
    DIRECTION INPUT ;
    USE SIGNAL ;
    PORT
      LAYER M5 ;
        RECT  63.984 0 64.008 0.084 ;
    END
  END cfg_data[234]
  PIN cfg_data[235]
    DIRECTION INPUT ;
    USE SIGNAL ;
    PORT
      LAYER M5 ;
        RECT  64.224 0 64.248 0.084 ;
    END
  END cfg_data[235]
  PIN cfg_data[236]
    DIRECTION INPUT ;
    USE SIGNAL ;
    PORT
      LAYER M5 ;
        RECT  64.464 0 64.488 0.084 ;
    END
  END cfg_data[236]
  PIN cfg_data[237]
    DIRECTION INPUT ;
    USE SIGNAL ;
    PORT
      LAYER M5 ;
        RECT  64.752 0 64.776 0.084 ;
    END
  END cfg_data[237]
  PIN cfg_data[238]
    DIRECTION INPUT ;
    USE SIGNAL ;
    PORT
      LAYER M5 ;
        RECT  64.992 0 65.016 0.084 ;
    END
  END cfg_data[238]
  PIN cfg_data[239]
    DIRECTION INPUT ;
    USE SIGNAL ;
    PORT
      LAYER M5 ;
        RECT  65.232 0 65.256 0.084 ;
    END
  END cfg_data[239]
  PIN cfg_data[23]
    DIRECTION INPUT ;
    USE SIGNAL ;
    PORT
      LAYER M5 ;
        RECT  10.08 0 10.104 0.084 ;
    END
  END cfg_data[23]
  PIN cfg_data[240]
    DIRECTION INPUT ;
    USE SIGNAL ;
    PORT
      LAYER M5 ;
        RECT  65.52 0 65.544 0.084 ;
    END
  END cfg_data[240]
  PIN cfg_data[241]
    DIRECTION INPUT ;
    USE SIGNAL ;
    PORT
      LAYER M5 ;
        RECT  65.76 0 65.784 0.084 ;
    END
  END cfg_data[241]
  PIN cfg_data[242]
    DIRECTION INPUT ;
    USE SIGNAL ;
    PORT
      LAYER M5 ;
        RECT  66 0 66.024 0.084 ;
    END
  END cfg_data[242]
  PIN cfg_data[243]
    DIRECTION INPUT ;
    USE SIGNAL ;
    PORT
      LAYER M5 ;
        RECT  66.24 0 66.264 0.084 ;
    END
  END cfg_data[243]
  PIN cfg_data[244]
    DIRECTION INPUT ;
    USE SIGNAL ;
    PORT
      LAYER M3 ;
        RECT  66.528 0 66.546 0.038 ;
    END
  END cfg_data[244]
  PIN cfg_data[245]
    DIRECTION INPUT ;
    USE SIGNAL ;
    PORT
      LAYER M3 ;
        RECT  66.78 0 66.798 0.038 ;
    END
  END cfg_data[245]
  PIN cfg_data[246]
    DIRECTION INPUT ;
    USE SIGNAL ;
    PORT
      LAYER M3 ;
        RECT  67.032 0 67.05 0.038 ;
    END
  END cfg_data[246]
  PIN cfg_data[247]
    DIRECTION INPUT ;
    USE SIGNAL ;
    PORT
      LAYER M3 ;
        RECT  67.284 0 67.302 0.038 ;
    END
  END cfg_data[247]
  PIN cfg_data[248]
    DIRECTION INPUT ;
    USE SIGNAL ;
    PORT
      LAYER M3 ;
        RECT  67.536 0 67.554 0.038 ;
    END
  END cfg_data[248]
  PIN cfg_data[249]
    DIRECTION INPUT ;
    USE SIGNAL ;
    PORT
      LAYER M3 ;
        RECT  67.788 0 67.806 0.038 ;
    END
  END cfg_data[249]
  PIN cfg_data[24]
    DIRECTION INPUT ;
    USE SIGNAL ;
    PORT
      LAYER M5 ;
        RECT  10.32 0 10.344 0.084 ;
    END
  END cfg_data[24]
  PIN cfg_data[250]
    DIRECTION INPUT ;
    USE SIGNAL ;
    PORT
      LAYER M3 ;
        RECT  68.04 0 68.058 0.038 ;
    END
  END cfg_data[250]
  PIN cfg_data[251]
    DIRECTION INPUT ;
    USE SIGNAL ;
    PORT
      LAYER M3 ;
        RECT  68.292 0 68.31 0.038 ;
    END
  END cfg_data[251]
  PIN cfg_data[252]
    DIRECTION INPUT ;
    USE SIGNAL ;
    PORT
      LAYER M3 ;
        RECT  68.58 0 68.598 0.038 ;
    END
  END cfg_data[252]
  PIN cfg_data[253]
    DIRECTION INPUT ;
    USE SIGNAL ;
    PORT
      LAYER M3 ;
        RECT  68.832 0 68.85 0.038 ;
    END
  END cfg_data[253]
  PIN cfg_data[254]
    DIRECTION INPUT ;
    USE SIGNAL ;
    PORT
      LAYER M3 ;
        RECT  69.084 0 69.102 0.038 ;
    END
  END cfg_data[254]
  PIN cfg_data[255]
    DIRECTION INPUT ;
    USE SIGNAL ;
    PORT
      LAYER M3 ;
        RECT  69.336 0 69.354 0.038 ;
    END
  END cfg_data[255]
  PIN cfg_data[25]
    DIRECTION INPUT ;
    USE SIGNAL ;
    PORT
      LAYER M5 ;
        RECT  10.56 0 10.584 0.084 ;
    END
  END cfg_data[25]
  PIN cfg_data[26]
    DIRECTION INPUT ;
    USE SIGNAL ;
    PORT
      LAYER M5 ;
        RECT  10.848 0 10.872 0.084 ;
    END
  END cfg_data[26]
  PIN cfg_data[27]
    DIRECTION INPUT ;
    USE SIGNAL ;
    PORT
      LAYER M5 ;
        RECT  11.088 0 11.112 0.084 ;
    END
  END cfg_data[27]
  PIN cfg_data[28]
    DIRECTION INPUT ;
    USE SIGNAL ;
    PORT
      LAYER M5 ;
        RECT  11.328 0 11.352 0.084 ;
    END
  END cfg_data[28]
  PIN cfg_data[29]
    DIRECTION INPUT ;
    USE SIGNAL ;
    PORT
      LAYER M5 ;
        RECT  11.568 0 11.592 0.084 ;
    END
  END cfg_data[29]
  PIN cfg_data[2]
    DIRECTION INPUT ;
    USE SIGNAL ;
    PORT
      LAYER M3 ;
        RECT  4.68 0 4.698 0.038 ;
    END
  END cfg_data[2]
  PIN cfg_data[30]
    DIRECTION INPUT ;
    USE SIGNAL ;
    PORT
      LAYER M5 ;
        RECT  11.856 0 11.88 0.084 ;
    END
  END cfg_data[30]
  PIN cfg_data[31]
    DIRECTION INPUT ;
    USE SIGNAL ;
    PORT
      LAYER M5 ;
        RECT  12.096 0 12.12 0.084 ;
    END
  END cfg_data[31]
  PIN cfg_data[32]
    DIRECTION INPUT ;
    USE SIGNAL ;
    PORT
      LAYER M5 ;
        RECT  12.336 0 12.36 0.084 ;
    END
  END cfg_data[32]
  PIN cfg_data[33]
    DIRECTION INPUT ;
    USE SIGNAL ;
    PORT
      LAYER M5 ;
        RECT  12.624 0 12.648 0.084 ;
    END
  END cfg_data[33]
  PIN cfg_data[34]
    DIRECTION INPUT ;
    USE SIGNAL ;
    PORT
      LAYER M5 ;
        RECT  12.864 0 12.888 0.084 ;
    END
  END cfg_data[34]
  PIN cfg_data[35]
    DIRECTION INPUT ;
    USE SIGNAL ;
    PORT
      LAYER M5 ;
        RECT  13.104 0 13.128 0.084 ;
    END
  END cfg_data[35]
  PIN cfg_data[36]
    DIRECTION INPUT ;
    USE SIGNAL ;
    PORT
      LAYER M5 ;
        RECT  13.392 0 13.416 0.084 ;
    END
  END cfg_data[36]
  PIN cfg_data[37]
    DIRECTION INPUT ;
    USE SIGNAL ;
    PORT
      LAYER M5 ;
        RECT  13.632 0 13.656 0.084 ;
    END
  END cfg_data[37]
  PIN cfg_data[38]
    DIRECTION INPUT ;
    USE SIGNAL ;
    PORT
      LAYER M5 ;
        RECT  13.872 0 13.896 0.084 ;
    END
  END cfg_data[38]
  PIN cfg_data[39]
    DIRECTION INPUT ;
    USE SIGNAL ;
    PORT
      LAYER M5 ;
        RECT  14.16 0 14.184 0.084 ;
    END
  END cfg_data[39]
  PIN cfg_data[3]
    DIRECTION INPUT ;
    USE SIGNAL ;
    PORT
      LAYER M3 ;
        RECT  4.968 0 4.986 0.038 ;
    END
  END cfg_data[3]
  PIN cfg_data[40]
    DIRECTION INPUT ;
    USE SIGNAL ;
    PORT
      LAYER M5 ;
        RECT  14.4 0 14.424 0.084 ;
    END
  END cfg_data[40]
  PIN cfg_data[41]
    DIRECTION INPUT ;
    USE SIGNAL ;
    PORT
      LAYER M5 ;
        RECT  14.64 0 14.664 0.084 ;
    END
  END cfg_data[41]
  PIN cfg_data[42]
    DIRECTION INPUT ;
    USE SIGNAL ;
    PORT
      LAYER M5 ;
        RECT  14.928 0 14.952 0.084 ;
    END
  END cfg_data[42]
  PIN cfg_data[43]
    DIRECTION INPUT ;
    USE SIGNAL ;
    PORT
      LAYER M5 ;
        RECT  15.168 0 15.192 0.084 ;
    END
  END cfg_data[43]
  PIN cfg_data[44]
    DIRECTION INPUT ;
    USE SIGNAL ;
    PORT
      LAYER M5 ;
        RECT  15.408 0 15.432 0.084 ;
    END
  END cfg_data[44]
  PIN cfg_data[45]
    DIRECTION INPUT ;
    USE SIGNAL ;
    PORT
      LAYER M5 ;
        RECT  15.696 0 15.72 0.084 ;
    END
  END cfg_data[45]
  PIN cfg_data[46]
    DIRECTION INPUT ;
    USE SIGNAL ;
    PORT
      LAYER M5 ;
        RECT  15.936 0 15.96 0.084 ;
    END
  END cfg_data[46]
  PIN cfg_data[47]
    DIRECTION INPUT ;
    USE SIGNAL ;
    PORT
      LAYER M5 ;
        RECT  16.176 0 16.2 0.084 ;
    END
  END cfg_data[47]
  PIN cfg_data[48]
    DIRECTION INPUT ;
    USE SIGNAL ;
    PORT
      LAYER M5 ;
        RECT  16.464 0 16.488 0.084 ;
    END
  END cfg_data[48]
  PIN cfg_data[49]
    DIRECTION INPUT ;
    USE SIGNAL ;
    PORT
      LAYER M5 ;
        RECT  16.704 0 16.728 0.084 ;
    END
  END cfg_data[49]
  PIN cfg_data[4]
    DIRECTION INPUT ;
    USE SIGNAL ;
    PORT
      LAYER M3 ;
        RECT  5.22 0 5.238 0.038 ;
    END
  END cfg_data[4]
  PIN cfg_data[50]
    DIRECTION INPUT ;
    USE SIGNAL ;
    PORT
      LAYER M5 ;
        RECT  16.944 0 16.968 0.084 ;
    END
  END cfg_data[50]
  PIN cfg_data[51]
    DIRECTION INPUT ;
    USE SIGNAL ;
    PORT
      LAYER M5 ;
        RECT  17.232 0 17.256 0.084 ;
    END
  END cfg_data[51]
  PIN cfg_data[52]
    DIRECTION INPUT ;
    USE SIGNAL ;
    PORT
      LAYER M3 ;
        RECT  17.46 0 17.478 0.038 ;
    END
  END cfg_data[52]
  PIN cfg_data[53]
    DIRECTION INPUT ;
    USE SIGNAL ;
    PORT
      LAYER M3 ;
        RECT  17.712 0 17.73 0.038 ;
    END
  END cfg_data[53]
  PIN cfg_data[54]
    DIRECTION INPUT ;
    USE SIGNAL ;
    PORT
      LAYER M3 ;
        RECT  17.964 0 17.982 0.038 ;
    END
  END cfg_data[54]
  PIN cfg_data[55]
    DIRECTION INPUT ;
    USE SIGNAL ;
    PORT
      LAYER M3 ;
        RECT  18.252 0 18.27 0.038 ;
    END
  END cfg_data[55]
  PIN cfg_data[56]
    DIRECTION INPUT ;
    USE SIGNAL ;
    PORT
      LAYER M3 ;
        RECT  18.504 0 18.522 0.038 ;
    END
  END cfg_data[56]
  PIN cfg_data[57]
    DIRECTION INPUT ;
    USE SIGNAL ;
    PORT
      LAYER M3 ;
        RECT  18.756 0 18.774 0.038 ;
    END
  END cfg_data[57]
  PIN cfg_data[58]
    DIRECTION INPUT ;
    USE SIGNAL ;
    PORT
      LAYER M3 ;
        RECT  19.008 0 19.026 0.038 ;
    END
  END cfg_data[58]
  PIN cfg_data[59]
    DIRECTION INPUT ;
    USE SIGNAL ;
    PORT
      LAYER M3 ;
        RECT  19.26 0 19.278 0.038 ;
    END
  END cfg_data[59]
  PIN cfg_data[5]
    DIRECTION INPUT ;
    USE SIGNAL ;
    PORT
      LAYER M3 ;
        RECT  5.472 0 5.49 0.038 ;
    END
  END cfg_data[5]
  PIN cfg_data[60]
    DIRECTION INPUT ;
    USE SIGNAL ;
    PORT
      LAYER M3 ;
        RECT  19.512 0 19.53 0.038 ;
    END
  END cfg_data[60]
  PIN cfg_data[61]
    DIRECTION INPUT ;
    USE SIGNAL ;
    PORT
      LAYER M3 ;
        RECT  19.764 0 19.782 0.038 ;
    END
  END cfg_data[61]
  PIN cfg_data[62]
    DIRECTION INPUT ;
    USE SIGNAL ;
    PORT
      LAYER M3 ;
        RECT  20.016 0 20.034 0.038 ;
    END
  END cfg_data[62]
  PIN cfg_data[63]
    DIRECTION INPUT ;
    USE SIGNAL ;
    PORT
      LAYER M3 ;
        RECT  20.268 0 20.286 0.038 ;
    END
  END cfg_data[63]
  PIN cfg_data[64]
    DIRECTION INPUT ;
    USE SIGNAL ;
    PORT
      LAYER M3 ;
        RECT  20.52 0 20.538 0.038 ;
    END
  END cfg_data[64]
  PIN cfg_data[65]
    DIRECTION INPUT ;
    USE SIGNAL ;
    PORT
      LAYER M3 ;
        RECT  20.808 0 20.826 0.038 ;
    END
  END cfg_data[65]
  PIN cfg_data[66]
    DIRECTION INPUT ;
    USE SIGNAL ;
    PORT
      LAYER M3 ;
        RECT  21.06 0 21.078 0.038 ;
    END
  END cfg_data[66]
  PIN cfg_data[67]
    DIRECTION INPUT ;
    USE SIGNAL ;
    PORT
      LAYER M3 ;
        RECT  21.312 0 21.33 0.038 ;
    END
  END cfg_data[67]
  PIN cfg_data[68]
    DIRECTION INPUT ;
    USE SIGNAL ;
    PORT
      LAYER M3 ;
        RECT  21.564 0 21.582 0.038 ;
    END
  END cfg_data[68]
  PIN cfg_data[69]
    DIRECTION INPUT ;
    USE SIGNAL ;
    PORT
      LAYER M3 ;
        RECT  21.816 0 21.834 0.038 ;
    END
  END cfg_data[69]
  PIN cfg_data[6]
    DIRECTION INPUT ;
    USE SIGNAL ;
    PORT
      LAYER M3 ;
        RECT  5.724 0 5.742 0.038 ;
    END
  END cfg_data[6]
  PIN cfg_data[70]
    DIRECTION INPUT ;
    USE SIGNAL ;
    PORT
      LAYER M3 ;
        RECT  22.068 0 22.086 0.038 ;
    END
  END cfg_data[70]
  PIN cfg_data[71]
    DIRECTION INPUT ;
    USE SIGNAL ;
    PORT
      LAYER M3 ;
        RECT  22.32 0 22.338 0.038 ;
    END
  END cfg_data[71]
  PIN cfg_data[72]
    DIRECTION INPUT ;
    USE SIGNAL ;
    PORT
      LAYER M3 ;
        RECT  22.572 0 22.59 0.038 ;
    END
  END cfg_data[72]
  PIN cfg_data[73]
    DIRECTION INPUT ;
    USE SIGNAL ;
    PORT
      LAYER M3 ;
        RECT  22.824 0 22.842 0.038 ;
    END
  END cfg_data[73]
  PIN cfg_data[74]
    DIRECTION INPUT ;
    USE SIGNAL ;
    PORT
      LAYER M3 ;
        RECT  23.076 0 23.094 0.038 ;
    END
  END cfg_data[74]
  PIN cfg_data[75]
    DIRECTION INPUT ;
    USE SIGNAL ;
    PORT
      LAYER M3 ;
        RECT  23.328 0 23.346 0.038 ;
    END
  END cfg_data[75]
  PIN cfg_data[76]
    DIRECTION INPUT ;
    USE SIGNAL ;
    PORT
      LAYER M3 ;
        RECT  23.616 0 23.634 0.038 ;
    END
  END cfg_data[76]
  PIN cfg_data[77]
    DIRECTION INPUT ;
    USE SIGNAL ;
    PORT
      LAYER M3 ;
        RECT  23.868 0 23.886 0.038 ;
    END
  END cfg_data[77]
  PIN cfg_data[78]
    DIRECTION INPUT ;
    USE SIGNAL ;
    PORT
      LAYER M3 ;
        RECT  24.12 0 24.138 0.038 ;
    END
  END cfg_data[78]
  PIN cfg_data[79]
    DIRECTION INPUT ;
    USE SIGNAL ;
    PORT
      LAYER M3 ;
        RECT  24.372 0 24.39 0.038 ;
    END
  END cfg_data[79]
  PIN cfg_data[7]
    DIRECTION INPUT ;
    USE SIGNAL ;
    PORT
      LAYER M3 ;
        RECT  5.976 0 5.994 0.038 ;
    END
  END cfg_data[7]
  PIN cfg_data[80]
    DIRECTION INPUT ;
    USE SIGNAL ;
    PORT
      LAYER M3 ;
        RECT  24.624 0 24.642 0.038 ;
    END
  END cfg_data[80]
  PIN cfg_data[81]
    DIRECTION INPUT ;
    USE SIGNAL ;
    PORT
      LAYER M3 ;
        RECT  24.876 0 24.894 0.038 ;
    END
  END cfg_data[81]
  PIN cfg_data[82]
    DIRECTION INPUT ;
    USE SIGNAL ;
    PORT
      LAYER M3 ;
        RECT  25.128 0 25.146 0.038 ;
    END
  END cfg_data[82]
  PIN cfg_data[83]
    DIRECTION INPUT ;
    USE SIGNAL ;
    PORT
      LAYER M3 ;
        RECT  25.38 0 25.398 0.038 ;
    END
  END cfg_data[83]
  PIN cfg_data[84]
    DIRECTION INPUT ;
    USE SIGNAL ;
    PORT
      LAYER M5 ;
        RECT  25.632 0 25.656 0.084 ;
    END
  END cfg_data[84]
  PIN cfg_data[85]
    DIRECTION INPUT ;
    USE SIGNAL ;
    PORT
      LAYER M5 ;
        RECT  25.92 0 25.944 0.084 ;
    END
  END cfg_data[85]
  PIN cfg_data[86]
    DIRECTION INPUT ;
    USE SIGNAL ;
    PORT
      LAYER M5 ;
        RECT  26.16 0 26.184 0.084 ;
    END
  END cfg_data[86]
  PIN cfg_data[87]
    DIRECTION INPUT ;
    USE SIGNAL ;
    PORT
      LAYER M5 ;
        RECT  26.4 0 26.424 0.084 ;
    END
  END cfg_data[87]
  PIN cfg_data[88]
    DIRECTION INPUT ;
    USE SIGNAL ;
    PORT
      LAYER M5 ;
        RECT  26.64 0 26.664 0.084 ;
    END
  END cfg_data[88]
  PIN cfg_data[89]
    DIRECTION INPUT ;
    USE SIGNAL ;
    PORT
      LAYER M5 ;
        RECT  26.928 0 26.952 0.084 ;
    END
  END cfg_data[89]
  PIN cfg_data[8]
    DIRECTION INPUT ;
    USE SIGNAL ;
    PORT
      LAYER M3 ;
        RECT  6.228 0 6.246 0.038 ;
    END
  END cfg_data[8]
  PIN cfg_data[90]
    DIRECTION INPUT ;
    USE SIGNAL ;
    PORT
      LAYER M5 ;
        RECT  27.168 0 27.192 0.084 ;
    END
  END cfg_data[90]
  PIN cfg_data[91]
    DIRECTION INPUT ;
    USE SIGNAL ;
    PORT
      LAYER M5 ;
        RECT  27.408 0 27.432 0.084 ;
    END
  END cfg_data[91]
  PIN cfg_data[92]
    DIRECTION INPUT ;
    USE SIGNAL ;
    PORT
      LAYER M5 ;
        RECT  27.696 0 27.72 0.084 ;
    END
  END cfg_data[92]
  PIN cfg_data[93]
    DIRECTION INPUT ;
    USE SIGNAL ;
    PORT
      LAYER M5 ;
        RECT  27.936 0 27.96 0.084 ;
    END
  END cfg_data[93]
  PIN cfg_data[94]
    DIRECTION INPUT ;
    USE SIGNAL ;
    PORT
      LAYER M5 ;
        RECT  28.176 0 28.2 0.084 ;
    END
  END cfg_data[94]
  PIN cfg_data[95]
    DIRECTION INPUT ;
    USE SIGNAL ;
    PORT
      LAYER M5 ;
        RECT  28.464 0 28.488 0.084 ;
    END
  END cfg_data[95]
  PIN cfg_data[96]
    DIRECTION INPUT ;
    USE SIGNAL ;
    PORT
      LAYER M5 ;
        RECT  28.704 0 28.728 0.084 ;
    END
  END cfg_data[96]
  PIN cfg_data[97]
    DIRECTION INPUT ;
    USE SIGNAL ;
    PORT
      LAYER M5 ;
        RECT  28.944 0 28.968 0.084 ;
    END
  END cfg_data[97]
  PIN cfg_data[98]
    DIRECTION INPUT ;
    USE SIGNAL ;
    PORT
      LAYER M5 ;
        RECT  29.232 0 29.256 0.084 ;
    END
  END cfg_data[98]
  PIN cfg_data[99]
    DIRECTION INPUT ;
    USE SIGNAL ;
    PORT
      LAYER M5 ;
        RECT  29.472 0 29.496 0.084 ;
    END
  END cfg_data[99]
  PIN cfg_data[9]
    DIRECTION INPUT ;
    USE SIGNAL ;
    PORT
      LAYER M3 ;
        RECT  6.48 0 6.498 0.038 ;
    END
  END cfg_data[9]
  PIN cfg_target[0]
    DIRECTION INPUT ;
    USE SIGNAL ;
    PORT
      LAYER M3 ;
        RECT  69.588 0 69.606 0.038 ;
    END
  END cfg_target[0]
  PIN cfg_target[1]
    DIRECTION INPUT ;
    USE SIGNAL ;
    PORT
      LAYER M3 ;
        RECT  69.84 0 69.858 0.038 ;
    END
  END cfg_target[1]
  PIN cfg_target[2]
    DIRECTION INPUT ;
    USE SIGNAL ;
    PORT
      LAYER M3 ;
        RECT  70.092 0 70.11 0.038 ;
    END
  END cfg_target[2]
  PIN cfg_target[3]
    DIRECTION INPUT ;
    USE SIGNAL ;
    PORT
      LAYER M3 ;
        RECT  70.344 0 70.362 0.038 ;
    END
  END cfg_target[3]
  PIN cfg_target[4]
    DIRECTION INPUT ;
    USE SIGNAL ;
    PORT
      LAYER M3 ;
        RECT  70.596 0 70.614 0.038 ;
    END
  END cfg_target[4]
  PIN cfg_target[5]
    DIRECTION INPUT ;
    USE SIGNAL ;
    PORT
      LAYER M3 ;
        RECT  70.848 0 70.866 0.038 ;
    END
  END cfg_target[5]
  PIN cfg_target[6]
    DIRECTION INPUT ;
    USE SIGNAL ;
    PORT
      LAYER M3 ;
        RECT  71.136 0 71.154 0.038 ;
    END
  END cfg_target[6]
  PIN cfg_target[7]
    DIRECTION INPUT ;
    USE SIGNAL ;
    PORT
      LAYER M3 ;
        RECT  71.388 0 71.406 0.038 ;
    END
  END cfg_target[7]
  PIN cfg_v
    DIRECTION INPUT ;
    USE SIGNAL ;
    PORT
      LAYER M3 ;
        RECT  71.64 0 71.658 0.038 ;
    END
  END cfg_v
  PIN clk
    DIRECTION INPUT ;
    USE SIGNAL ;
    PORT
      LAYER M3 ;
        RECT  50.58 0 50.598 0.038 ;
    END
  END clk
  PIN configured
    DIRECTION OUTPUT ;
    USE SIGNAL ;
    PORT
      LAYER M3 ;
        RECT  71.892 0 71.91 0.038 ;
    END
  END configured
  PIN desc_base[0]
    DIRECTION INPUT ;
    USE SIGNAL ;
    PORT
      LAYER M3 ;
        RECT  72.144 0 72.162 0.038 ;
    END
  END desc_base[0]
  PIN desc_base[10]
    DIRECTION INPUT ;
    USE SIGNAL ;
    PORT
      LAYER M5 ;
        RECT  74.688 0 74.712 0.084 ;
    END
  END desc_base[10]
  PIN desc_base[11]
    DIRECTION INPUT ;
    USE SIGNAL ;
    PORT
      LAYER M5 ;
        RECT  74.928 0 74.952 0.084 ;
    END
  END desc_base[11]
  PIN desc_base[1]
    DIRECTION INPUT ;
    USE SIGNAL ;
    PORT
      LAYER M3 ;
        RECT  72.396 0 72.414 0.038 ;
    END
  END desc_base[1]
  PIN desc_base[2]
    DIRECTION INPUT ;
    USE SIGNAL ;
    PORT
      LAYER M3 ;
        RECT  72.648 0 72.666 0.038 ;
    END
  END desc_base[2]
  PIN desc_base[3]
    DIRECTION INPUT ;
    USE SIGNAL ;
    PORT
      LAYER M3 ;
        RECT  72.9 0 72.918 0.038 ;
    END
  END desc_base[3]
  PIN desc_base[4]
    DIRECTION INPUT ;
    USE SIGNAL ;
    PORT
      LAYER M3 ;
        RECT  73.152 0 73.17 0.038 ;
    END
  END desc_base[4]
  PIN desc_base[5]
    DIRECTION INPUT ;
    USE SIGNAL ;
    PORT
      LAYER M3 ;
        RECT  73.404 0 73.422 0.038 ;
    END
  END desc_base[5]
  PIN desc_base[6]
    DIRECTION INPUT ;
    USE SIGNAL ;
    PORT
      LAYER M3 ;
        RECT  73.692 0 73.71 0.038 ;
    END
  END desc_base[6]
  PIN desc_base[7]
    DIRECTION INPUT ;
    USE SIGNAL ;
    PORT
      LAYER M3 ;
        RECT  73.944 0 73.962 0.038 ;
    END
  END desc_base[7]
  PIN desc_base[8]
    DIRECTION INPUT ;
    USE SIGNAL ;
    PORT
      LAYER M3 ;
        RECT  74.196 0 74.214 0.038 ;
    END
  END desc_base[8]
  PIN desc_base[9]
    DIRECTION INPUT ;
    USE SIGNAL ;
    PORT
      LAYER M3 ;
        RECT  74.448 0 74.466 0.038 ;
    END
  END desc_base[9]
  PIN desc_limit[0]
    DIRECTION INPUT ;
    USE SIGNAL ;
    PORT
      LAYER M5 ;
        RECT  75.216 0 75.24 0.084 ;
    END
  END desc_limit[0]
  PIN desc_limit[10]
    DIRECTION INPUT ;
    USE SIGNAL ;
    PORT
      LAYER M5 ;
        RECT  77.76 0 77.784 0.084 ;
    END
  END desc_limit[10]
  PIN desc_limit[11]
    DIRECTION INPUT ;
    USE SIGNAL ;
    PORT
      LAYER M5 ;
        RECT  78 0 78.024 0.084 ;
    END
  END desc_limit[11]
  PIN desc_limit[12]
    DIRECTION INPUT ;
    USE SIGNAL ;
    PORT
      LAYER M5 ;
        RECT  78.288 0 78.312 0.084 ;
    END
  END desc_limit[12]
  PIN desc_limit[1]
    DIRECTION INPUT ;
    USE SIGNAL ;
    PORT
      LAYER M5 ;
        RECT  75.456 0 75.48 0.084 ;
    END
  END desc_limit[1]
  PIN desc_limit[2]
    DIRECTION INPUT ;
    USE SIGNAL ;
    PORT
      LAYER M5 ;
        RECT  75.696 0 75.72 0.084 ;
    END
  END desc_limit[2]
  PIN desc_limit[3]
    DIRECTION INPUT ;
    USE SIGNAL ;
    PORT
      LAYER M5 ;
        RECT  75.984 0 76.008 0.084 ;
    END
  END desc_limit[3]
  PIN desc_limit[4]
    DIRECTION INPUT ;
    USE SIGNAL ;
    PORT
      LAYER M5 ;
        RECT  76.224 0 76.248 0.084 ;
    END
  END desc_limit[4]
  PIN desc_limit[5]
    DIRECTION INPUT ;
    USE SIGNAL ;
    PORT
      LAYER M5 ;
        RECT  76.464 0 76.488 0.084 ;
    END
  END desc_limit[5]
  PIN desc_limit[6]
    DIRECTION INPUT ;
    USE SIGNAL ;
    PORT
      LAYER M5 ;
        RECT  76.752 0 76.776 0.084 ;
    END
  END desc_limit[6]
  PIN desc_limit[7]
    DIRECTION INPUT ;
    USE SIGNAL ;
    PORT
      LAYER M5 ;
        RECT  76.992 0 77.016 0.084 ;
    END
  END desc_limit[7]
  PIN desc_limit[8]
    DIRECTION INPUT ;
    USE SIGNAL ;
    PORT
      LAYER M5 ;
        RECT  77.232 0 77.256 0.084 ;
    END
  END desc_limit[8]
  PIN desc_limit[9]
    DIRECTION INPUT ;
    USE SIGNAL ;
    PORT
      LAYER M5 ;
        RECT  77.52 0 77.544 0.084 ;
    END
  END desc_limit[9]
  PIN desc_loops[0]
    DIRECTION INPUT ;
    USE SIGNAL ;
    PORT
      LAYER M5 ;
        RECT  78.528 0 78.552 0.084 ;
    END
  END desc_loops[0]
  PIN desc_loops[10]
    DIRECTION INPUT ;
    USE SIGNAL ;
    PORT
      LAYER M5 ;
        RECT  81.072 0 81.096 0.084 ;
    END
  END desc_loops[10]
  PIN desc_loops[11]
    DIRECTION INPUT ;
    USE SIGNAL ;
    PORT
      LAYER M5 ;
        RECT  81.36 0 81.384 0.084 ;
    END
  END desc_loops[11]
  PIN desc_loops[12]
    DIRECTION INPUT ;
    USE SIGNAL ;
    PORT
      LAYER M5 ;
        RECT  81.6 0 81.624 0.084 ;
    END
  END desc_loops[12]
  PIN desc_loops[13]
    DIRECTION INPUT ;
    USE SIGNAL ;
    PORT
      LAYER M5 ;
        RECT  81.84 0 81.864 0.084 ;
    END
  END desc_loops[13]
  PIN desc_loops[14]
    DIRECTION INPUT ;
    USE SIGNAL ;
    PORT
      LAYER M5 ;
        RECT  82.08 0 82.104 0.084 ;
    END
  END desc_loops[14]
  PIN desc_loops[15]
    DIRECTION INPUT ;
    USE SIGNAL ;
    PORT
      LAYER M5 ;
        RECT  82.368 0 82.392 0.084 ;
    END
  END desc_loops[15]
  PIN desc_loops[1]
    DIRECTION INPUT ;
    USE SIGNAL ;
    PORT
      LAYER M5 ;
        RECT  78.768 0 78.792 0.084 ;
    END
  END desc_loops[1]
  PIN desc_loops[2]
    DIRECTION INPUT ;
    USE SIGNAL ;
    PORT
      LAYER M5 ;
        RECT  79.056 0 79.08 0.084 ;
    END
  END desc_loops[2]
  PIN desc_loops[3]
    DIRECTION INPUT ;
    USE SIGNAL ;
    PORT
      LAYER M5 ;
        RECT  79.296 0 79.32 0.084 ;
    END
  END desc_loops[3]
  PIN desc_loops[4]
    DIRECTION INPUT ;
    USE SIGNAL ;
    PORT
      LAYER M5 ;
        RECT  79.536 0 79.56 0.084 ;
    END
  END desc_loops[4]
  PIN desc_loops[5]
    DIRECTION INPUT ;
    USE SIGNAL ;
    PORT
      LAYER M5 ;
        RECT  79.824 0 79.848 0.084 ;
    END
  END desc_loops[5]
  PIN desc_loops[6]
    DIRECTION INPUT ;
    USE SIGNAL ;
    PORT
      LAYER M5 ;
        RECT  80.064 0 80.088 0.084 ;
    END
  END desc_loops[6]
  PIN desc_loops[7]
    DIRECTION INPUT ;
    USE SIGNAL ;
    PORT
      LAYER M5 ;
        RECT  80.304 0 80.328 0.084 ;
    END
  END desc_loops[7]
  PIN desc_loops[8]
    DIRECTION INPUT ;
    USE SIGNAL ;
    PORT
      LAYER M5 ;
        RECT  80.592 0 80.616 0.084 ;
    END
  END desc_loops[8]
  PIN desc_loops[9]
    DIRECTION INPUT ;
    USE SIGNAL ;
    PORT
      LAYER M5 ;
        RECT  80.832 0 80.856 0.084 ;
    END
  END desc_loops[9]
  PIN desc_v
    DIRECTION INPUT ;
    USE SIGNAL ;
    PORT
      LAYER M5 ;
        RECT  82.608 0 82.632 0.084 ;
    END
  END desc_v
  PIN fault
    DIRECTION OUTPUT ;
    USE SIGNAL ;
    PORT
      LAYER M3 ;
        RECT  82.872 0 82.89 0.038 ;
    END
  END fault
  PIN fault_cause[0]
    DIRECTION OUTPUT ;
    USE SIGNAL ;
    PORT
      LAYER M3 ;
        RECT  83.124 0 83.142 0.038 ;
    END
  END fault_cause[0]
  PIN fault_cause[10]
    DIRECTION OUTPUT ;
    USE SIGNAL ;
    PORT
      LAYER M3 ;
        RECT  85.68 0 85.698 0.038 ;
    END
  END fault_cause[10]
  PIN fault_cause[11]
    DIRECTION OUTPUT ;
    USE SIGNAL ;
    PORT
      LAYER M3 ;
        RECT  85.932 0 85.95 0.038 ;
    END
  END fault_cause[11]
  PIN fault_cause[12]
    DIRECTION OUTPUT ;
    USE SIGNAL ;
    PORT
      LAYER M3 ;
        RECT  86.184 0 86.202 0.038 ;
    END
  END fault_cause[12]
  PIN fault_cause[13]
    DIRECTION OUTPUT ;
    USE SIGNAL ;
    PORT
      LAYER M3 ;
        RECT  86.436 0 86.454 0.038 ;
    END
  END fault_cause[13]
  PIN fault_cause[14]
    DIRECTION OUTPUT ;
    USE SIGNAL ;
    PORT
      LAYER M3 ;
        RECT  86.688 0 86.706 0.038 ;
    END
  END fault_cause[14]
  PIN fault_cause[15]
    DIRECTION OUTPUT ;
    USE SIGNAL ;
    PORT
      LAYER M3 ;
        RECT  86.976 0 86.994 0.038 ;
    END
  END fault_cause[15]
  PIN fault_cause[1]
    DIRECTION OUTPUT ;
    USE SIGNAL ;
    PORT
      LAYER M3 ;
        RECT  83.376 0 83.394 0.038 ;
    END
  END fault_cause[1]
  PIN fault_cause[2]
    DIRECTION OUTPUT ;
    USE SIGNAL ;
    PORT
      LAYER M3 ;
        RECT  83.628 0 83.646 0.038 ;
    END
  END fault_cause[2]
  PIN fault_cause[3]
    DIRECTION OUTPUT ;
    USE SIGNAL ;
    PORT
      LAYER M3 ;
        RECT  83.88 0 83.898 0.038 ;
    END
  END fault_cause[3]
  PIN fault_cause[4]
    DIRECTION OUTPUT ;
    USE SIGNAL ;
    PORT
      LAYER M3 ;
        RECT  84.132 0 84.15 0.038 ;
    END
  END fault_cause[4]
  PIN fault_cause[5]
    DIRECTION OUTPUT ;
    USE SIGNAL ;
    PORT
      LAYER M3 ;
        RECT  84.42 0 84.438 0.038 ;
    END
  END fault_cause[5]
  PIN fault_cause[6]
    DIRECTION OUTPUT ;
    USE SIGNAL ;
    PORT
      LAYER M3 ;
        RECT  84.672 0 84.69 0.038 ;
    END
  END fault_cause[6]
  PIN fault_cause[7]
    DIRECTION OUTPUT ;
    USE SIGNAL ;
    PORT
      LAYER M3 ;
        RECT  84.924 0 84.942 0.038 ;
    END
  END fault_cause[7]
  PIN fault_cause[8]
    DIRECTION OUTPUT ;
    USE SIGNAL ;
    PORT
      LAYER M3 ;
        RECT  85.176 0 85.194 0.038 ;
    END
  END fault_cause[8]
  PIN fault_cause[9]
    DIRECTION OUTPUT ;
    USE SIGNAL ;
    PORT
      LAYER M3 ;
        RECT  85.428 0 85.446 0.038 ;
    END
  END fault_cause[9]
  PIN init_busy
    DIRECTION OUTPUT ;
    USE SIGNAL ;
    PORT
      LAYER M3 ;
        RECT  87.228 0 87.246 0.038 ;
    END
  END init_busy
  PIN issuer_busy
    DIRECTION INPUT ;
    USE SIGNAL ;
    PORT
      LAYER M3 ;
        RECT  87.48 0 87.498 0.038 ;
    END
  END issuer_busy
  PIN issuer_cfg[0]
    DIRECTION OUTPUT ;
    USE SIGNAL ;
    PORT
      LAYER M3 ;
        RECT  87.732 0 87.75 0.038 ;
    END
  END issuer_cfg[0]
  PIN issuer_cfg[10]
    DIRECTION OUTPUT ;
    USE SIGNAL ;
    PORT
      LAYER M3 ;
        RECT  90.288 0 90.306 0.038 ;
    END
  END issuer_cfg[10]
  PIN issuer_cfg[11]
    DIRECTION OUTPUT ;
    USE SIGNAL ;
    PORT
      LAYER M3 ;
        RECT  90.54 0 90.558 0.038 ;
    END
  END issuer_cfg[11]
  PIN issuer_cfg[12]
    DIRECTION OUTPUT ;
    USE SIGNAL ;
    PORT
      LAYER M3 ;
        RECT  90.792 0 90.81 0.038 ;
    END
  END issuer_cfg[12]
  PIN issuer_cfg[13]
    DIRECTION OUTPUT ;
    USE SIGNAL ;
    PORT
      LAYER M5 ;
        RECT  91.056 0 91.08 0.084 ;
    END
  END issuer_cfg[13]
  PIN issuer_cfg[14]
    DIRECTION OUTPUT ;
    USE SIGNAL ;
    PORT
      LAYER M5 ;
        RECT  91.296 0 91.32 0.084 ;
    END
  END issuer_cfg[14]
  PIN issuer_cfg[15]
    DIRECTION OUTPUT ;
    USE SIGNAL ;
    PORT
      LAYER M5 ;
        RECT  91.536 0 91.56 0.084 ;
    END
  END issuer_cfg[15]
  PIN issuer_cfg[16]
    DIRECTION OUTPUT ;
    USE SIGNAL ;
    PORT
      LAYER M5 ;
        RECT  91.824 0 91.848 0.084 ;
    END
  END issuer_cfg[16]
  PIN issuer_cfg[17]
    DIRECTION OUTPUT ;
    USE SIGNAL ;
    PORT
      LAYER M5 ;
        RECT  92.064 0 92.088 0.084 ;
    END
  END issuer_cfg[17]
  PIN issuer_cfg[18]
    DIRECTION OUTPUT ;
    USE SIGNAL ;
    PORT
      LAYER M5 ;
        RECT  92.304 0 92.328 0.084 ;
    END
  END issuer_cfg[18]
  PIN issuer_cfg[19]
    DIRECTION OUTPUT ;
    USE SIGNAL ;
    PORT
      LAYER M5 ;
        RECT  92.592 0 92.616 0.084 ;
    END
  END issuer_cfg[19]
  PIN issuer_cfg[1]
    DIRECTION OUTPUT ;
    USE SIGNAL ;
    PORT
      LAYER M3 ;
        RECT  87.984 0 88.002 0.038 ;
    END
  END issuer_cfg[1]
  PIN issuer_cfg[20]
    DIRECTION OUTPUT ;
    USE SIGNAL ;
    PORT
      LAYER M5 ;
        RECT  92.832 0 92.856 0.084 ;
    END
  END issuer_cfg[20]
  PIN issuer_cfg[21]
    DIRECTION OUTPUT ;
    USE SIGNAL ;
    PORT
      LAYER M5 ;
        RECT  93.072 0 93.096 0.084 ;
    END
  END issuer_cfg[21]
  PIN issuer_cfg[22]
    DIRECTION OUTPUT ;
    USE SIGNAL ;
    PORT
      LAYER M5 ;
        RECT  93.36 0 93.384 0.084 ;
    END
  END issuer_cfg[22]
  PIN issuer_cfg[23]
    DIRECTION OUTPUT ;
    USE SIGNAL ;
    PORT
      LAYER M5 ;
        RECT  93.6 0 93.624 0.084 ;
    END
  END issuer_cfg[23]
  PIN issuer_cfg[24]
    DIRECTION OUTPUT ;
    USE SIGNAL ;
    PORT
      LAYER M5 ;
        RECT  93.84 0 93.864 0.084 ;
    END
  END issuer_cfg[24]
  PIN issuer_cfg[25]
    DIRECTION OUTPUT ;
    USE SIGNAL ;
    PORT
      LAYER M5 ;
        RECT  94.128 0 94.152 0.084 ;
    END
  END issuer_cfg[25]
  PIN issuer_cfg[26]
    DIRECTION OUTPUT ;
    USE SIGNAL ;
    PORT
      LAYER M5 ;
        RECT  94.368 0 94.392 0.084 ;
    END
  END issuer_cfg[26]
  PIN issuer_cfg[27]
    DIRECTION OUTPUT ;
    USE SIGNAL ;
    PORT
      LAYER M5 ;
        RECT  94.608 0 94.632 0.084 ;
    END
  END issuer_cfg[27]
  PIN issuer_cfg[28]
    DIRECTION OUTPUT ;
    USE SIGNAL ;
    PORT
      LAYER M5 ;
        RECT  94.896 0 94.92 0.084 ;
    END
  END issuer_cfg[28]
  PIN issuer_cfg[29]
    DIRECTION OUTPUT ;
    USE SIGNAL ;
    PORT
      LAYER M5 ;
        RECT  95.136 0 95.16 0.084 ;
    END
  END issuer_cfg[29]
  PIN issuer_cfg[2]
    DIRECTION OUTPUT ;
    USE SIGNAL ;
    PORT
      LAYER M3 ;
        RECT  88.236 0 88.254 0.038 ;
    END
  END issuer_cfg[2]
  PIN issuer_cfg[30]
    DIRECTION OUTPUT ;
    USE SIGNAL ;
    PORT
      LAYER M5 ;
        RECT  95.376 0 95.4 0.084 ;
    END
  END issuer_cfg[30]
  PIN issuer_cfg[31]
    DIRECTION OUTPUT ;
    USE SIGNAL ;
    PORT
      LAYER M5 ;
        RECT  95.664 0 95.688 0.084 ;
    END
  END issuer_cfg[31]
  PIN issuer_cfg[32]
    DIRECTION OUTPUT ;
    USE SIGNAL ;
    PORT
      LAYER M5 ;
        RECT  95.904 0 95.928 0.084 ;
    END
  END issuer_cfg[32]
  PIN issuer_cfg[33]
    DIRECTION OUTPUT ;
    USE SIGNAL ;
    PORT
      LAYER M5 ;
        RECT  96.144 0 96.168 0.084 ;
    END
  END issuer_cfg[33]
  PIN issuer_cfg[34]
    DIRECTION OUTPUT ;
    USE SIGNAL ;
    PORT
      LAYER M5 ;
        RECT  96.432 0 96.456 0.084 ;
    END
  END issuer_cfg[34]
  PIN issuer_cfg[35]
    DIRECTION OUTPUT ;
    USE SIGNAL ;
    PORT
      LAYER M5 ;
        RECT  96.672 0 96.696 0.084 ;
    END
  END issuer_cfg[35]
  PIN issuer_cfg[36]
    DIRECTION OUTPUT ;
    USE SIGNAL ;
    PORT
      LAYER M5 ;
        RECT  96.912 0 96.936 0.084 ;
    END
  END issuer_cfg[36]
  PIN issuer_cfg[3]
    DIRECTION OUTPUT ;
    USE SIGNAL ;
    PORT
      LAYER M3 ;
        RECT  88.488 0 88.506 0.038 ;
    END
  END issuer_cfg[3]
  PIN issuer_cfg[4]
    DIRECTION OUTPUT ;
    USE SIGNAL ;
    PORT
      LAYER M3 ;
        RECT  88.74 0 88.758 0.038 ;
    END
  END issuer_cfg[4]
  PIN issuer_cfg[5]
    DIRECTION OUTPUT ;
    USE SIGNAL ;
    PORT
      LAYER M3 ;
        RECT  88.992 0 89.01 0.038 ;
    END
  END issuer_cfg[5]
  PIN issuer_cfg[6]
    DIRECTION OUTPUT ;
    USE SIGNAL ;
    PORT
      LAYER M3 ;
        RECT  89.244 0 89.262 0.038 ;
    END
  END issuer_cfg[6]
  PIN issuer_cfg[7]
    DIRECTION OUTPUT ;
    USE SIGNAL ;
    PORT
      LAYER M3 ;
        RECT  89.532 0 89.55 0.038 ;
    END
  END issuer_cfg[7]
  PIN issuer_cfg[8]
    DIRECTION OUTPUT ;
    USE SIGNAL ;
    PORT
      LAYER M3 ;
        RECT  89.784 0 89.802 0.038 ;
    END
  END issuer_cfg[8]
  PIN issuer_cfg[9]
    DIRECTION OUTPUT ;
    USE SIGNAL ;
    PORT
      LAYER M3 ;
        RECT  90.036 0 90.054 0.038 ;
    END
  END issuer_cfg[9]
  PIN issuer_fault
    DIRECTION INPUT ;
    USE SIGNAL ;
    PORT
      LAYER M5 ;
        RECT  97.152 0 97.176 0.084 ;
    END
  END issuer_fault
  PIN issuer_start
    DIRECTION OUTPUT ;
    USE SIGNAL ;
    PORT
      LAYER M5 ;
        RECT  97.44 0 97.464 0.084 ;
    END
  END issuer_start
  PIN issuer_start_pc[0]
    DIRECTION OUTPUT ;
    USE SIGNAL ;
    PORT
      LAYER M5 ;
        RECT  97.68 0 97.704 0.084 ;
    END
  END issuer_start_pc[0]
  PIN issuer_start_pc[1]
    DIRECTION OUTPUT ;
    USE SIGNAL ;
    PORT
      LAYER M5 ;
        RECT  97.92 0 97.944 0.084 ;
    END
  END issuer_start_pc[1]
  PIN issuer_start_pc[2]
    DIRECTION OUTPUT ;
    USE SIGNAL ;
    PORT
      LAYER M5 ;
        RECT  98.208 0 98.232 0.084 ;
    END
  END issuer_start_pc[2]
  PIN issuer_start_pc[3]
    DIRECTION OUTPUT ;
    USE SIGNAL ;
    PORT
      LAYER M5 ;
        RECT  98.448 0 98.472 0.084 ;
    END
  END issuer_start_pc[3]
  PIN issuer_start_pc[4]
    DIRECTION OUTPUT ;
    USE SIGNAL ;
    PORT
      LAYER M5 ;
        RECT  98.688 0 98.712 0.084 ;
    END
  END issuer_start_pc[4]
  PIN issuer_start_pc[5]
    DIRECTION OUTPUT ;
    USE SIGNAL ;
    PORT
      LAYER M5 ;
        RECT  98.976 0 99 0.084 ;
    END
  END issuer_start_pc[5]
  PIN issuer_start_pc[6]
    DIRECTION OUTPUT ;
    USE SIGNAL ;
    PORT
      LAYER M3 ;
        RECT  99.216 0 99.234 0.038 ;
    END
  END issuer_start_pc[6]
  PIN issuer_uop_pc[0]
    DIRECTION INPUT ;
    USE SIGNAL ;
    PORT
      LAYER M3 ;
        RECT  99.468 0 99.486 0.038 ;
    END
  END issuer_uop_pc[0]
  PIN issuer_uop_pc[1]
    DIRECTION INPUT ;
    USE SIGNAL ;
    PORT
      LAYER M3 ;
        RECT  99.72 0 99.738 0.038 ;
    END
  END issuer_uop_pc[1]
  PIN issuer_uop_pc[2]
    DIRECTION INPUT ;
    USE SIGNAL ;
    PORT
      LAYER M3 ;
        RECT  99.972 0 99.99 0.038 ;
    END
  END issuer_uop_pc[2]
  PIN issuer_uop_pc[3]
    DIRECTION INPUT ;
    USE SIGNAL ;
    PORT
      LAYER M3 ;
        RECT  100.26 0 100.278 0.038 ;
    END
  END issuer_uop_pc[3]
  PIN issuer_uop_pc[4]
    DIRECTION INPUT ;
    USE SIGNAL ;
    PORT
      LAYER M3 ;
        RECT  100.512 0 100.53 0.038 ;
    END
  END issuer_uop_pc[4]
  PIN issuer_uop_pc[5]
    DIRECTION INPUT ;
    USE SIGNAL ;
    PORT
      LAYER M3 ;
        RECT  100.764 0 100.782 0.038 ;
    END
  END issuer_uop_pc[5]
  PIN issuer_uop_pc[6]
    DIRECTION INPUT ;
    USE SIGNAL ;
    PORT
      LAYER M3 ;
        RECT  101.016 0 101.034 0.038 ;
    END
  END issuer_uop_pc[6]
  PIN issuer_uop_v
    DIRECTION INPUT ;
    USE SIGNAL ;
    PORT
      LAYER M3 ;
        RECT  101.268 0 101.286 0.038 ;
    END
  END issuer_uop_v
  PIN launch_v
    DIRECTION INPUT ;
    USE SIGNAL ;
    PORT
      LAYER M3 ;
        RECT  101.52 0 101.538 0.038 ;
    END
  END launch_v
  PIN link_abort
    DIRECTION INPUT ;
    USE SIGNAL ;
    PORT
      LAYER M4 ;
        RECT  0 9.648 0.084 9.672 ;
    END
    PORT
      LAYER M4 ;
        RECT  0.06 9.648 0.137 9.672 ;
    END
  END link_abort
  PIN program_active
    DIRECTION INPUT ;
    USE SIGNAL ;
    PORT
      LAYER M3 ;
        RECT  101.772 0 101.79 0.038 ;
    END
  END program_active
  PIN program_fault
    DIRECTION OUTPUT ;
    USE SIGNAL ;
    PORT
      LAYER M3 ;
        RECT  102.024 0 102.042 0.038 ;
    END
  END program_fault
  PIN protocol_fault
    DIRECTION INPUT ;
    USE SIGNAL ;
    PORT
      LAYER M4 ;
        RECT  103.596 12.96 103.68 12.984 ;
    END
    PORT
      LAYER M4 ;
        RECT  102.481 12.96 103.644 12.984 ;
    END
  END protocol_fault
  PIN qid[0]
    DIRECTION INPUT ;
    USE SIGNAL ;
    PORT
      LAYER M3 ;
        RECT  102.276 0 102.294 0.038 ;
    END
  END qid[0]
  PIN qid[1]
    DIRECTION INPUT ;
    USE SIGNAL ;
    PORT
      LAYER M3 ;
        RECT  102.528 0 102.546 0.038 ;
    END
  END qid[1]
  PIN reduce_fault
    DIRECTION INPUT ;
    USE SIGNAL ;
    PORT
      LAYER M4 ;
        RECT  0 26.976 0.084 27 ;
    END
    PORT
      LAYER M4 ;
        RECT  0.06 26.976 0.137 27 ;
    END
  END reduce_fault
  PIN ring_fault
    DIRECTION INPUT ;
    USE SIGNAL ;
    PORT
      LAYER M4 ;
        RECT  0 44.304 0.084 44.328 ;
    END
    PORT
      LAYER M4 ;
        RECT  0.06 44.304 0.137 44.328 ;
    END
  END ring_fault
  PIN rst_n
    DIRECTION INPUT ;
    USE SIGNAL ;
    PORT
      LAYER M3 ;
        RECT  51.804 0 51.822 0.038 ;
    END
  END rst_n
  PIN select_fault[0]
    DIRECTION INPUT ;
    USE SIGNAL ;
    PORT
      LAYER M4 ;
        RECT  103.596 14.208 103.68 14.232 ;
    END
    PORT
      LAYER M4 ;
        RECT  102.553 14.208 103.644 14.232 ;
    END
  END select_fault[0]
  PIN select_fault[10]
    DIRECTION INPUT ;
    USE SIGNAL ;
    PORT
      LAYER M4 ;
        RECT  103.596 26.832 103.68 26.856 ;
    END
    PORT
      LAYER M4 ;
        RECT  102.013 26.832 103.644 26.856 ;
    END
  END select_fault[10]
  PIN select_fault[11]
    DIRECTION INPUT ;
    USE SIGNAL ;
    PORT
      LAYER M4 ;
        RECT  103.596 28.08 103.68 28.104 ;
    END
    PORT
      LAYER M4 ;
        RECT  102.013 28.08 103.644 28.104 ;
    END
  END select_fault[11]
  PIN select_fault[12]
    DIRECTION INPUT ;
    USE SIGNAL ;
    PORT
      LAYER M4 ;
        RECT  103.596 29.328 103.68 29.352 ;
    END
    PORT
      LAYER M4 ;
        RECT  101.437 29.328 103.644 29.352 ;
    END
  END select_fault[12]
  PIN select_fault[13]
    DIRECTION INPUT ;
    USE SIGNAL ;
    PORT
      LAYER M4 ;
        RECT  103.596 30.576 103.68 30.6 ;
    END
    PORT
      LAYER M4 ;
        RECT  101.437 30.576 103.644 30.6 ;
    END
  END select_fault[13]
  PIN select_fault[14]
    DIRECTION INPUT ;
    USE SIGNAL ;
    PORT
      LAYER M4 ;
        RECT  103.596 31.872 103.68 31.896 ;
    END
    PORT
      LAYER M4 ;
        RECT  102.553 31.872 103.644 31.896 ;
    END
  END select_fault[14]
  PIN select_fault[15]
    DIRECTION INPUT ;
    USE SIGNAL ;
    PORT
      LAYER M4 ;
        RECT  103.596 33.12 103.68 33.144 ;
    END
    PORT
      LAYER M4 ;
        RECT  102.553 33.12 103.644 33.144 ;
    END
  END select_fault[15]
  PIN select_fault[16]
    DIRECTION INPUT ;
    USE SIGNAL ;
    PORT
      LAYER M4 ;
        RECT  103.596 34.368 103.68 34.392 ;
    END
    PORT
      LAYER M4 ;
        RECT  101.977 34.368 103.644 34.392 ;
    END
  END select_fault[16]
  PIN select_fault[17]
    DIRECTION INPUT ;
    USE SIGNAL ;
    PORT
      LAYER M4 ;
        RECT  103.596 35.616 103.68 35.64 ;
    END
    PORT
      LAYER M4 ;
        RECT  102.553 35.616 103.644 35.64 ;
    END
  END select_fault[17]
  PIN select_fault[1]
    DIRECTION INPUT ;
    USE SIGNAL ;
    PORT
      LAYER M4 ;
        RECT  103.596 15.456 103.68 15.48 ;
    END
    PORT
      LAYER M4 ;
        RECT  101.977 15.456 103.644 15.48 ;
    END
  END select_fault[1]
  PIN select_fault[2]
    DIRECTION INPUT ;
    USE SIGNAL ;
    PORT
      LAYER M4 ;
        RECT  103.596 16.752 103.68 16.776 ;
    END
    PORT
      LAYER M4 ;
        RECT  102.553 16.752 103.644 16.776 ;
    END
  END select_fault[2]
  PIN select_fault[3]
    DIRECTION INPUT ;
    USE SIGNAL ;
    PORT
      LAYER M4 ;
        RECT  103.596 18 103.68 18.024 ;
    END
    PORT
      LAYER M4 ;
        RECT  102.013 18 103.644 18.024 ;
    END
  END select_fault[3]
  PIN select_fault[4]
    DIRECTION INPUT ;
    USE SIGNAL ;
    PORT
      LAYER M4 ;
        RECT  103.596 19.248 103.68 19.272 ;
    END
    PORT
      LAYER M4 ;
        RECT  101.977 19.248 103.644 19.272 ;
    END
  END select_fault[4]
  PIN select_fault[5]
    DIRECTION INPUT ;
    USE SIGNAL ;
    PORT
      LAYER M4 ;
        RECT  103.596 20.496 103.68 20.52 ;
    END
    PORT
      LAYER M4 ;
        RECT  102.013 20.496 103.644 20.52 ;
    END
  END select_fault[5]
  PIN select_fault[6]
    DIRECTION INPUT ;
    USE SIGNAL ;
    PORT
      LAYER M4 ;
        RECT  103.596 21.792 103.68 21.816 ;
    END
    PORT
      LAYER M4 ;
        RECT  102.553 21.792 103.644 21.816 ;
    END
  END select_fault[6]
  PIN select_fault[7]
    DIRECTION INPUT ;
    USE SIGNAL ;
    PORT
      LAYER M4 ;
        RECT  103.596 23.04 103.68 23.064 ;
    END
    PORT
      LAYER M4 ;
        RECT  102.553 23.04 103.644 23.064 ;
    END
  END select_fault[7]
  PIN select_fault[8]
    DIRECTION INPUT ;
    USE SIGNAL ;
    PORT
      LAYER M4 ;
        RECT  103.596 24.288 103.68 24.312 ;
    END
    PORT
      LAYER M4 ;
        RECT  101.977 24.288 103.644 24.312 ;
    END
  END select_fault[8]
  PIN select_fault[9]
    DIRECTION INPUT ;
    USE SIGNAL ;
    PORT
      LAYER M4 ;
        RECT  103.596 25.536 103.68 25.56 ;
    END
    PORT
      LAYER M4 ;
        RECT  102.553 25.536 103.644 25.56 ;
    END
  END select_fault[9]
  PIN tkm_del_slot[0]
    DIRECTION INPUT ;
    USE SIGNAL ;
    PORT
      LAYER M4 ;
        RECT  103.596 36.912 103.68 36.936 ;
    END
    PORT
      LAYER M4 ;
        RECT  102.553 36.912 103.644 36.936 ;
    END
  END tkm_del_slot[0]
  PIN tkm_del_slot[1]
    DIRECTION INPUT ;
    USE SIGNAL ;
    PORT
      LAYER M4 ;
        RECT  103.596 38.16 103.68 38.184 ;
    END
    PORT
      LAYER M4 ;
        RECT  101.977 38.16 103.644 38.184 ;
    END
  END tkm_del_slot[1]
  PIN tkm_del_slot[2]
    DIRECTION INPUT ;
    USE SIGNAL ;
    PORT
      LAYER M4 ;
        RECT  103.596 39.408 103.68 39.432 ;
    END
    PORT
      LAYER M4 ;
        RECT  102.553 39.408 103.644 39.432 ;
    END
  END tkm_del_slot[2]
  PIN tkm_del_slot[3]
    DIRECTION INPUT ;
    USE SIGNAL ;
    PORT
      LAYER M4 ;
        RECT  103.596 40.656 103.68 40.68 ;
    END
    PORT
      LAYER M4 ;
        RECT  102.553 40.656 103.644 40.68 ;
    END
  END tkm_del_slot[3]
  PIN tkm_dest_v[0]
    DIRECTION INPUT ;
    USE SIGNAL ;
    PORT
      LAYER M4 ;
        RECT  103.596 41.904 103.68 41.928 ;
    END
    PORT
      LAYER M4 ;
        RECT  102.553 41.904 103.644 41.928 ;
    END
  END tkm_dest_v[0]
  PIN tkm_dest_v[1]
    DIRECTION INPUT ;
    USE SIGNAL ;
    PORT
      LAYER M4 ;
        RECT  103.596 43.2 103.68 43.224 ;
    END
    PORT
      LAYER M4 ;
        RECT  102.553 43.2 103.644 43.224 ;
    END
  END tkm_dest_v[1]
  PIN tkm_dest_v[2]
    DIRECTION INPUT ;
    USE SIGNAL ;
    PORT
      LAYER M4 ;
        RECT  103.596 44.448 103.68 44.472 ;
    END
    PORT
      LAYER M4 ;
        RECT  102.589 44.448 103.644 44.472 ;
    END
  END tkm_dest_v[2]
  PIN tkm_dest_v[3]
    DIRECTION INPUT ;
    USE SIGNAL ;
    PORT
      LAYER M4 ;
        RECT  103.596 45.696 103.68 45.72 ;
    END
    PORT
      LAYER M4 ;
        RECT  101.977 45.696 103.644 45.72 ;
    END
  END tkm_dest_v[3]
  PIN tkm_start
    DIRECTION INPUT ;
    USE SIGNAL ;
    PORT
      LAYER M4 ;
        RECT  103.596 46.944 103.68 46.968 ;
    END
    PORT
      LAYER M4 ;
        RECT  102.553 46.944 103.644 46.968 ;
    END
  END tkm_start
  PIN unavailable_fault[0]
    DIRECTION INPUT ;
    USE SIGNAL ;
    PORT
      LAYER M4 ;
        RECT  103.596 48.24 103.68 48.264 ;
    END
    PORT
      LAYER M4 ;
        RECT  101.905 48.24 103.644 48.264 ;
    END
  END unavailable_fault[0]
  PIN unavailable_fault[10]
    DIRECTION INPUT ;
    USE SIGNAL ;
    PORT
      LAYER M4 ;
        RECT  103.596 60.816 103.68 60.84 ;
    END
    PORT
      LAYER M4 ;
        RECT  102.553 60.816 103.644 60.84 ;
    END
  END unavailable_fault[10]
  PIN unavailable_fault[11]
    DIRECTION INPUT ;
    USE SIGNAL ;
    PORT
      LAYER M4 ;
        RECT  103.596 62.064 103.68 62.088 ;
    END
    PORT
      LAYER M4 ;
        RECT  102.553 62.064 103.644 62.088 ;
    END
  END unavailable_fault[11]
  PIN unavailable_fault[12]
    DIRECTION INPUT ;
    USE SIGNAL ;
    PORT
      LAYER M4 ;
        RECT  103.596 63.36 103.68 63.384 ;
    END
    PORT
      LAYER M4 ;
        RECT  102.013 63.36 103.644 63.384 ;
    END
  END unavailable_fault[12]
  PIN unavailable_fault[13]
    DIRECTION INPUT ;
    USE SIGNAL ;
    PORT
      LAYER M4 ;
        RECT  103.596 64.608 103.68 64.632 ;
    END
    PORT
      LAYER M4 ;
        RECT  101.977 64.608 103.644 64.632 ;
    END
  END unavailable_fault[13]
  PIN unavailable_fault[14]
    DIRECTION INPUT ;
    USE SIGNAL ;
    PORT
      LAYER M4 ;
        RECT  103.596 65.856 103.68 65.88 ;
    END
    PORT
      LAYER M4 ;
        RECT  102.553 65.856 103.644 65.88 ;
    END
  END unavailable_fault[14]
  PIN unavailable_fault[15]
    DIRECTION INPUT ;
    USE SIGNAL ;
    PORT
      LAYER M4 ;
        RECT  103.596 67.104 103.68 67.128 ;
    END
    PORT
      LAYER M4 ;
        RECT  102.553 67.104 103.644 67.128 ;
    END
  END unavailable_fault[15]
  PIN unavailable_fault[16]
    DIRECTION INPUT ;
    USE SIGNAL ;
    PORT
      LAYER M4 ;
        RECT  103.596 68.4 103.68 68.424 ;
    END
    PORT
      LAYER M4 ;
        RECT  102.589 68.4 103.644 68.424 ;
    END
  END unavailable_fault[16]
  PIN unavailable_fault[17]
    DIRECTION INPUT ;
    USE SIGNAL ;
    PORT
      LAYER M4 ;
        RECT  103.596 69.648 103.68 69.672 ;
    END
    PORT
      LAYER M4 ;
        RECT  100.789 69.648 103.644 69.672 ;
    END
  END unavailable_fault[17]
  PIN unavailable_fault[1]
    DIRECTION INPUT ;
    USE SIGNAL ;
    PORT
      LAYER M4 ;
        RECT  103.596 49.488 103.68 49.512 ;
    END
    PORT
      LAYER M4 ;
        RECT  101.977 49.488 103.644 49.512 ;
    END
  END unavailable_fault[1]
  PIN unavailable_fault[2]
    DIRECTION INPUT ;
    USE SIGNAL ;
    PORT
      LAYER M4 ;
        RECT  103.596 50.736 103.68 50.76 ;
    END
    PORT
      LAYER M4 ;
        RECT  101.977 50.736 103.644 50.76 ;
    END
  END unavailable_fault[2]
  PIN unavailable_fault[3]
    DIRECTION INPUT ;
    USE SIGNAL ;
    PORT
      LAYER M4 ;
        RECT  103.596 51.984 103.68 52.008 ;
    END
    PORT
      LAYER M4 ;
        RECT  102.553 51.984 103.644 52.008 ;
    END
  END unavailable_fault[3]
  PIN unavailable_fault[4]
    DIRECTION INPUT ;
    USE SIGNAL ;
    PORT
      LAYER M4 ;
        RECT  103.596 53.28 103.68 53.304 ;
    END
    PORT
      LAYER M4 ;
        RECT  101.977 53.28 103.644 53.304 ;
    END
  END unavailable_fault[4]
  PIN unavailable_fault[5]
    DIRECTION INPUT ;
    USE SIGNAL ;
    PORT
      LAYER M4 ;
        RECT  103.596 54.528 103.68 54.552 ;
    END
    PORT
      LAYER M4 ;
        RECT  101.977 54.528 103.644 54.552 ;
    END
  END unavailable_fault[5]
  PIN unavailable_fault[6]
    DIRECTION INPUT ;
    USE SIGNAL ;
    PORT
      LAYER M4 ;
        RECT  103.596 55.776 103.68 55.8 ;
    END
    PORT
      LAYER M4 ;
        RECT  101.977 55.776 103.644 55.8 ;
    END
  END unavailable_fault[6]
  PIN unavailable_fault[7]
    DIRECTION INPUT ;
    USE SIGNAL ;
    PORT
      LAYER M4 ;
        RECT  103.596 57.024 103.68 57.048 ;
    END
    PORT
      LAYER M4 ;
        RECT  102.553 57.024 103.644 57.048 ;
    END
  END unavailable_fault[7]
  PIN unavailable_fault[8]
    DIRECTION INPUT ;
    USE SIGNAL ;
    PORT
      LAYER M4 ;
        RECT  103.596 58.32 103.68 58.344 ;
    END
    PORT
      LAYER M4 ;
        RECT  101.617 58.32 103.644 58.344 ;
    END
  END unavailable_fault[8]
  PIN unavailable_fault[9]
    DIRECTION INPUT ;
    USE SIGNAL ;
    PORT
      LAYER M4 ;
        RECT  103.596 59.568 103.68 59.592 ;
    END
    PORT
      LAYER M4 ;
        RECT  102.481 59.568 103.644 59.592 ;
    END
  END unavailable_fault[9]
  PIN writer_fault
    DIRECTION INPUT ;
    USE SIGNAL ;
    PORT
      LAYER M4 ;
        RECT  0 61.632 0.084 61.656 ;
    END
    PORT
      LAYER M4 ;
        RECT  0.06 61.632 0.137 61.656 ;
    END
  END writer_fault
  PIN VDD
    DIRECTION INOUT ;
    USE POWER ;
    PORT
      LAYER M5 ;
        RECT  99.792 2.151 99.912 69.129 ;
        RECT  94.392 2.151 94.512 69.129 ;
        RECT  88.992 2.151 89.112 69.129 ;
        RECT  83.592 2.151 83.712 69.129 ;
        RECT  78.192 2.151 78.312 69.129 ;
        RECT  72.792 2.151 72.912 69.129 ;
        RECT  67.392 2.151 67.512 69.129 ;
        RECT  61.992 2.151 62.112 69.129 ;
        RECT  56.592 2.151 56.712 69.129 ;
        RECT  51.192 2.151 51.312 69.129 ;
        RECT  45.792 2.151 45.912 69.129 ;
        RECT  40.392 2.151 40.512 69.129 ;
        RECT  34.992 2.151 35.112 69.129 ;
        RECT  29.592 2.151 29.712 69.129 ;
        RECT  24.192 2.151 24.312 69.129 ;
        RECT  18.792 2.151 18.912 69.129 ;
        RECT  13.392 2.151 13.512 69.129 ;
        RECT  7.992 2.151 8.112 69.129 ;
        RECT  2.592 2.151 2.712 69.129 ;
    END
  END VDD
  PIN VSS
    DIRECTION INOUT ;
    USE GROUND ;
    PORT
      LAYER M5 ;
        RECT  99.6 2.137 99.72 69.143 ;
        RECT  94.2 2.137 94.32 69.143 ;
        RECT  88.8 2.137 88.92 69.143 ;
        RECT  83.4 2.137 83.52 69.143 ;
        RECT  78 2.137 78.12 69.129 ;
        RECT  72.6 2.137 72.72 69.129 ;
        RECT  67.2 2.137 67.32 69.129 ;
        RECT  61.8 2.137 61.92 69.129 ;
        RECT  56.4 2.137 56.52 69.129 ;
        RECT  51 2.137 51.12 69.129 ;
        RECT  45.6 2.137 45.72 69.129 ;
        RECT  40.2 2.137 40.32 69.143 ;
        RECT  34.8 2.137 34.92 69.143 ;
        RECT  29.4 2.137 29.52 69.143 ;
        RECT  24 2.137 24.12 69.143 ;
        RECT  18.6 2.137 18.72 69.143 ;
        RECT  13.2 2.137 13.32 69.143 ;
        RECT  7.8 2.137 7.92 69.143 ;
        RECT  2.4 2.137 2.52 69.143 ;
    END
  END VSS
  # OT_OBS_CLOSED layer=M5 d_um=1.536 added=442
  OBS
    LAYER RVTN ;
     RECT  2.16 2.16 101.52 2.295 ;
     RECT  2.16 2.565 101.52 2.835 ;
     RECT  2.16 3.105 101.52 3.375 ;
     RECT  2.16 3.645 101.52 3.915 ;
     RECT  2.16 4.185 101.52 4.455 ;
     RECT  2.16 4.725 101.52 4.995 ;
     RECT  2.16 5.265 101.52 5.535 ;
     RECT  2.16 5.805 101.52 6.075 ;
     RECT  2.16 6.345 101.52 6.615 ;
     RECT  2.16 6.885 101.52 7.155 ;
     RECT  2.16 7.425 101.52 7.695 ;
     RECT  2.16 7.965 101.52 8.235 ;
     RECT  2.16 8.505 101.52 8.775 ;
     RECT  2.16 9.045 101.52 9.315 ;
     RECT  2.16 9.585 101.52 9.855 ;
     RECT  2.16 10.125 101.52 10.395 ;
     RECT  2.16 10.665 101.52 10.935 ;
     RECT  2.16 11.205 101.52 11.475 ;
     RECT  2.16 11.745 101.52 12.015 ;
     RECT  2.16 12.285 101.52 12.555 ;
     RECT  2.16 12.825 101.52 13.095 ;
     RECT  2.16 13.365 101.52 13.635 ;
     RECT  2.16 13.905 101.52 14.175 ;
     RECT  2.16 14.445 101.52 14.715 ;
     RECT  2.16 14.985 101.52 15.255 ;
     RECT  2.16 15.525 101.52 15.795 ;
     RECT  2.16 16.065 101.52 16.335 ;
     RECT  2.16 16.605 101.52 16.875 ;
     RECT  2.16 17.145 101.52 17.415 ;
     RECT  2.16 17.685 101.52 17.955 ;
     RECT  2.16 18.225 101.52 18.495 ;
     RECT  2.16 18.765 101.52 19.035 ;
     RECT  2.16 19.305 101.52 19.575 ;
     RECT  2.16 19.845 101.52 20.115 ;
     RECT  2.16 20.385 101.52 20.655 ;
     RECT  2.16 20.925 101.52 21.195 ;
     RECT  2.16 21.465 101.52 21.735 ;
     RECT  2.16 22.005 101.52 22.275 ;
     RECT  2.16 22.545 101.52 22.815 ;
     RECT  2.16 23.085 101.52 23.355 ;
     RECT  2.16 23.625 101.52 23.895 ;
     RECT  2.16 24.165 101.52 24.435 ;
     RECT  2.16 24.705 101.52 24.975 ;
     RECT  2.16 25.245 101.52 25.515 ;
     RECT  2.16 25.785 101.52 26.055 ;
     RECT  2.16 26.325 101.52 26.595 ;
     RECT  2.16 26.865 101.52 27.135 ;
     RECT  2.16 27.405 101.52 27.675 ;
     RECT  2.16 27.945 101.52 28.215 ;
     RECT  2.16 28.485 101.52 28.755 ;
     RECT  2.16 29.025 101.52 29.295 ;
     RECT  2.16 29.565 101.52 29.835 ;
     RECT  2.16 30.105 101.52 30.375 ;
     RECT  2.16 30.645 101.52 30.915 ;
     RECT  2.16 31.185 101.52 31.455 ;
     RECT  2.16 31.725 101.52 31.995 ;
     RECT  2.16 32.265 101.52 32.535 ;
     RECT  2.16 32.805 101.52 33.075 ;
     RECT  2.16 33.345 101.52 33.615 ;
     RECT  2.16 33.885 101.52 34.155 ;
     RECT  2.16 34.425 101.52 34.695 ;
     RECT  2.16 34.965 101.52 35.235 ;
     RECT  2.16 35.505 101.52 35.775 ;
     RECT  2.16 36.045 101.52 36.315 ;
     RECT  2.16 36.585 101.52 36.855 ;
     RECT  2.16 37.125 101.52 37.395 ;
     RECT  2.16 37.665 101.52 37.935 ;
     RECT  2.16 38.205 101.52 38.475 ;
     RECT  2.16 38.745 101.52 39.015 ;
     RECT  2.16 39.285 101.52 39.555 ;
     RECT  2.16 39.825 101.52 40.095 ;
     RECT  2.16 40.365 101.52 40.635 ;
     RECT  2.16 40.905 101.52 41.04 ;
     RECT  2.16 41.04 41.148 41.175 ;
     RECT  83.052 41.04 101.52 41.175 ;
     RECT  2.16 41.445 41.148 41.715 ;
     RECT  83.052 41.445 101.52 41.715 ;
     RECT  2.16 41.985 41.148 42.255 ;
     RECT  83.052 41.985 101.52 42.255 ;
     RECT  2.16 42.525 41.148 42.795 ;
     RECT  83.052 42.525 101.52 42.795 ;
     RECT  2.16 43.065 41.148 43.335 ;
     RECT  83.052 43.065 101.52 43.335 ;
     RECT  2.16 43.605 41.148 43.875 ;
     RECT  83.052 43.605 101.52 43.875 ;
     RECT  2.16 44.145 41.148 44.415 ;
     RECT  83.052 44.145 101.52 44.415 ;
     RECT  2.16 44.685 41.148 44.955 ;
     RECT  83.052 44.685 101.52 44.955 ;
     RECT  2.16 45.225 41.148 45.495 ;
     RECT  83.052 45.225 101.52 45.495 ;
     RECT  2.16 45.765 41.148 46.035 ;
     RECT  83.052 45.765 101.52 46.035 ;
     RECT  2.16 46.305 41.148 46.575 ;
     RECT  83.052 46.305 101.52 46.575 ;
     RECT  2.16 46.845 41.148 47.115 ;
     RECT  83.052 46.845 101.52 47.115 ;
     RECT  2.16 47.385 41.148 47.655 ;
     RECT  83.052 47.385 101.52 47.655 ;
     RECT  2.16 47.925 41.148 48.195 ;
     RECT  83.052 47.925 101.52 48.195 ;
     RECT  2.16 48.465 41.148 48.735 ;
     RECT  83.052 48.465 101.52 48.735 ;
     RECT  2.16 49.005 41.148 49.275 ;
     RECT  83.052 49.005 101.52 49.275 ;
     RECT  2.16 49.545 41.148 49.815 ;
     RECT  83.052 49.545 101.52 49.815 ;
     RECT  2.16 50.085 41.148 50.355 ;
     RECT  83.052 50.085 101.52 50.355 ;
     RECT  2.16 50.625 41.148 50.895 ;
     RECT  83.052 50.625 101.52 50.895 ;
     RECT  2.16 51.165 41.148 51.435 ;
     RECT  83.052 51.165 101.52 51.435 ;
     RECT  2.16 51.705 41.148 51.975 ;
     RECT  83.052 51.705 101.52 51.975 ;
     RECT  2.16 52.245 41.148 52.515 ;
     RECT  83.052 52.245 101.52 52.515 ;
     RECT  2.16 52.785 41.148 53.055 ;
     RECT  83.052 52.785 101.52 53.055 ;
     RECT  2.16 53.325 41.148 53.595 ;
     RECT  83.052 53.325 101.52 53.595 ;
     RECT  2.16 53.865 41.148 54.135 ;
     RECT  83.052 53.865 101.52 54.135 ;
     RECT  2.16 54.405 41.148 54.675 ;
     RECT  83.052 54.405 101.52 54.675 ;
     RECT  2.16 54.945 41.148 55.215 ;
     RECT  83.052 54.945 101.52 55.215 ;
     RECT  2.16 55.485 41.148 55.755 ;
     RECT  83.052 55.485 101.52 55.755 ;
     RECT  2.16 56.025 41.148 56.295 ;
     RECT  83.052 56.025 101.52 56.295 ;
     RECT  2.16 56.565 41.148 56.835 ;
     RECT  83.052 56.565 101.52 56.835 ;
     RECT  2.16 57.105 41.148 57.375 ;
     RECT  83.052 57.105 101.52 57.375 ;
     RECT  2.16 57.645 41.148 57.915 ;
     RECT  83.052 57.645 101.52 57.915 ;
     RECT  2.16 58.185 41.148 58.455 ;
     RECT  83.052 58.185 101.52 58.455 ;
     RECT  2.16 58.725 41.148 58.995 ;
     RECT  83.052 58.725 101.52 58.995 ;
     RECT  2.16 59.265 41.148 59.535 ;
     RECT  83.052 59.265 101.52 59.535 ;
     RECT  2.16 59.805 41.148 60.075 ;
     RECT  83.052 59.805 101.52 60.075 ;
     RECT  2.16 60.345 41.148 60.615 ;
     RECT  83.052 60.345 101.52 60.615 ;
     RECT  2.16 60.885 41.148 61.155 ;
     RECT  83.052 60.885 101.52 61.155 ;
     RECT  2.16 61.425 41.148 61.695 ;
     RECT  83.052 61.425 101.52 61.695 ;
     RECT  2.16 61.965 41.148 62.235 ;
     RECT  83.052 61.965 101.52 62.235 ;
     RECT  2.16 62.505 41.148 62.775 ;
     RECT  83.052 62.505 101.52 62.775 ;
     RECT  2.16 63.045 41.148 63.315 ;
     RECT  83.052 63.045 101.52 63.315 ;
     RECT  2.16 63.585 41.148 63.855 ;
     RECT  83.052 63.585 101.52 63.855 ;
     RECT  2.16 64.125 41.148 64.395 ;
     RECT  83.052 64.125 101.52 64.395 ;
     RECT  2.16 64.665 41.148 64.935 ;
     RECT  83.052 64.665 101.52 64.935 ;
     RECT  2.16 65.205 41.148 65.475 ;
     RECT  83.052 65.205 101.52 65.475 ;
     RECT  2.16 65.745 41.148 66.015 ;
     RECT  83.052 65.745 101.52 66.015 ;
     RECT  2.16 66.285 41.148 66.555 ;
     RECT  83.052 66.285 101.52 66.555 ;
     RECT  2.16 66.825 41.148 67.095 ;
     RECT  83.052 66.825 101.52 67.095 ;
     RECT  2.16 67.365 41.148 67.635 ;
     RECT  83.052 67.365 101.52 67.635 ;
     RECT  2.16 67.905 41.148 68.175 ;
     RECT  83.052 67.905 101.52 68.175 ;
     RECT  2.16 68.445 41.148 68.715 ;
     RECT  83.052 68.445 101.52 68.715 ;
     RECT  2.16 68.985 41.148 69.12 ;
     RECT  83.052 68.985 101.52 69.12 ;
    LAYER RVTP ;
     RECT  2.16 2.295 101.52 2.565 ;
     RECT  2.16 2.835 101.52 3.105 ;
     RECT  2.16 3.375 101.52 3.645 ;
     RECT  2.16 3.915 101.52 4.185 ;
     RECT  2.16 4.455 101.52 4.725 ;
     RECT  2.16 4.995 101.52 5.265 ;
     RECT  2.16 5.535 101.52 5.805 ;
     RECT  2.16 6.075 101.52 6.345 ;
     RECT  2.16 6.615 101.52 6.885 ;
     RECT  2.16 7.155 101.52 7.425 ;
     RECT  2.16 7.695 101.52 7.965 ;
     RECT  2.16 8.235 101.52 8.505 ;
     RECT  2.16 8.775 101.52 9.045 ;
     RECT  2.16 9.315 101.52 9.585 ;
     RECT  2.16 9.855 101.52 10.125 ;
     RECT  2.16 10.395 101.52 10.665 ;
     RECT  2.16 10.935 101.52 11.205 ;
     RECT  2.16 11.475 101.52 11.745 ;
     RECT  2.16 12.015 101.52 12.285 ;
     RECT  2.16 12.555 101.52 12.825 ;
     RECT  2.16 13.095 101.52 13.365 ;
     RECT  2.16 13.635 101.52 13.905 ;
     RECT  2.16 14.175 101.52 14.445 ;
     RECT  2.16 14.715 101.52 14.985 ;
     RECT  2.16 15.255 101.52 15.525 ;
     RECT  2.16 15.795 101.52 16.065 ;
     RECT  2.16 16.335 101.52 16.605 ;
     RECT  2.16 16.875 101.52 17.145 ;
     RECT  2.16 17.415 101.52 17.685 ;
     RECT  2.16 17.955 101.52 18.225 ;
     RECT  2.16 18.495 101.52 18.765 ;
     RECT  2.16 19.035 101.52 19.305 ;
     RECT  2.16 19.575 101.52 19.845 ;
     RECT  2.16 20.115 101.52 20.385 ;
     RECT  2.16 20.655 101.52 20.925 ;
     RECT  2.16 21.195 101.52 21.465 ;
     RECT  2.16 21.735 101.52 22.005 ;
     RECT  2.16 22.275 101.52 22.545 ;
     RECT  2.16 22.815 101.52 23.085 ;
     RECT  2.16 23.355 101.52 23.625 ;
     RECT  2.16 23.895 101.52 24.165 ;
     RECT  2.16 24.435 101.52 24.705 ;
     RECT  2.16 24.975 101.52 25.245 ;
     RECT  2.16 25.515 101.52 25.785 ;
     RECT  2.16 26.055 101.52 26.325 ;
     RECT  2.16 26.595 101.52 26.865 ;
     RECT  2.16 27.135 101.52 27.405 ;
     RECT  2.16 27.675 101.52 27.945 ;
     RECT  2.16 28.215 101.52 28.485 ;
     RECT  2.16 28.755 101.52 29.025 ;
     RECT  2.16 29.295 101.52 29.565 ;
     RECT  2.16 29.835 101.52 30.105 ;
     RECT  2.16 30.375 101.52 30.645 ;
     RECT  2.16 30.915 101.52 31.185 ;
     RECT  2.16 31.455 101.52 31.725 ;
     RECT  2.16 31.995 101.52 32.265 ;
     RECT  2.16 32.535 101.52 32.805 ;
     RECT  2.16 33.075 101.52 33.345 ;
     RECT  2.16 33.615 101.52 33.885 ;
     RECT  2.16 34.155 101.52 34.425 ;
     RECT  2.16 34.695 101.52 34.965 ;
     RECT  2.16 35.235 101.52 35.505 ;
     RECT  2.16 35.775 101.52 36.045 ;
     RECT  2.16 36.315 101.52 36.585 ;
     RECT  2.16 36.855 101.52 37.125 ;
     RECT  2.16 37.395 101.52 37.665 ;
     RECT  2.16 37.935 101.52 38.205 ;
     RECT  2.16 38.475 101.52 38.745 ;
     RECT  2.16 39.015 101.52 39.285 ;
     RECT  2.16 39.555 101.52 39.825 ;
     RECT  2.16 40.095 101.52 40.365 ;
     RECT  2.16 40.635 101.52 40.905 ;
     RECT  2.16 41.175 41.148 41.445 ;
     RECT  83.052 41.175 101.52 41.445 ;
     RECT  2.16 41.715 41.148 41.985 ;
     RECT  83.052 41.715 101.52 41.985 ;
     RECT  2.16 42.255 41.148 42.525 ;
     RECT  83.052 42.255 101.52 42.525 ;
     RECT  2.16 42.795 41.148 43.065 ;
     RECT  83.052 42.795 101.52 43.065 ;
     RECT  2.16 43.335 41.148 43.605 ;
     RECT  83.052 43.335 101.52 43.605 ;
     RECT  2.16 43.875 41.148 44.145 ;
     RECT  83.052 43.875 101.52 44.145 ;
     RECT  2.16 44.415 41.148 44.685 ;
     RECT  83.052 44.415 101.52 44.685 ;
     RECT  2.16 44.955 41.148 45.225 ;
     RECT  83.052 44.955 101.52 45.225 ;
     RECT  2.16 45.495 41.148 45.765 ;
     RECT  83.052 45.495 101.52 45.765 ;
     RECT  2.16 46.035 41.148 46.305 ;
     RECT  83.052 46.035 101.52 46.305 ;
     RECT  2.16 46.575 41.148 46.845 ;
     RECT  83.052 46.575 101.52 46.845 ;
     RECT  2.16 47.115 41.148 47.385 ;
     RECT  83.052 47.115 101.52 47.385 ;
     RECT  2.16 47.655 41.148 47.925 ;
     RECT  83.052 47.655 101.52 47.925 ;
     RECT  2.16 48.195 41.148 48.465 ;
     RECT  83.052 48.195 101.52 48.465 ;
     RECT  2.16 48.735 41.148 49.005 ;
     RECT  83.052 48.735 101.52 49.005 ;
     RECT  2.16 49.275 41.148 49.545 ;
     RECT  83.052 49.275 101.52 49.545 ;
     RECT  2.16 49.815 41.148 50.085 ;
     RECT  83.052 49.815 101.52 50.085 ;
     RECT  2.16 50.355 41.148 50.625 ;
     RECT  83.052 50.355 101.52 50.625 ;
     RECT  2.16 50.895 41.148 51.165 ;
     RECT  83.052 50.895 101.52 51.165 ;
     RECT  2.16 51.435 41.148 51.705 ;
     RECT  83.052 51.435 101.52 51.705 ;
     RECT  2.16 51.975 41.148 52.245 ;
     RECT  83.052 51.975 101.52 52.245 ;
     RECT  2.16 52.515 41.148 52.785 ;
     RECT  83.052 52.515 101.52 52.785 ;
     RECT  2.16 53.055 41.148 53.325 ;
     RECT  83.052 53.055 101.52 53.325 ;
     RECT  2.16 53.595 41.148 53.865 ;
     RECT  83.052 53.595 101.52 53.865 ;
     RECT  2.16 54.135 41.148 54.405 ;
     RECT  83.052 54.135 101.52 54.405 ;
     RECT  2.16 54.675 41.148 54.945 ;
     RECT  83.052 54.675 101.52 54.945 ;
     RECT  2.16 55.215 41.148 55.485 ;
     RECT  83.052 55.215 101.52 55.485 ;
     RECT  2.16 55.755 41.148 56.025 ;
     RECT  83.052 55.755 101.52 56.025 ;
     RECT  2.16 56.295 41.148 56.565 ;
     RECT  83.052 56.295 101.52 56.565 ;
     RECT  2.16 56.835 41.148 57.105 ;
     RECT  83.052 56.835 101.52 57.105 ;
     RECT  2.16 57.375 41.148 57.645 ;
     RECT  83.052 57.375 101.52 57.645 ;
     RECT  2.16 57.915 41.148 58.185 ;
     RECT  83.052 57.915 101.52 58.185 ;
     RECT  2.16 58.455 41.148 58.725 ;
     RECT  83.052 58.455 101.52 58.725 ;
     RECT  2.16 58.995 41.148 59.265 ;
     RECT  83.052 58.995 101.52 59.265 ;
     RECT  2.16 59.535 41.148 59.805 ;
     RECT  83.052 59.535 101.52 59.805 ;
     RECT  2.16 60.075 41.148 60.345 ;
     RECT  83.052 60.075 101.52 60.345 ;
     RECT  2.16 60.615 41.148 60.885 ;
     RECT  83.052 60.615 101.52 60.885 ;
     RECT  2.16 61.155 41.148 61.425 ;
     RECT  83.052 61.155 101.52 61.425 ;
     RECT  2.16 61.695 41.148 61.965 ;
     RECT  83.052 61.695 101.52 61.965 ;
     RECT  2.16 62.235 41.148 62.505 ;
     RECT  83.052 62.235 101.52 62.505 ;
     RECT  2.16 62.775 41.148 63.045 ;
     RECT  83.052 62.775 101.52 63.045 ;
     RECT  2.16 63.315 41.148 63.585 ;
     RECT  83.052 63.315 101.52 63.585 ;
     RECT  2.16 63.855 41.148 64.125 ;
     RECT  83.052 63.855 101.52 64.125 ;
     RECT  2.16 64.395 41.148 64.665 ;
     RECT  83.052 64.395 101.52 64.665 ;
     RECT  2.16 64.935 41.148 65.205 ;
     RECT  83.052 64.935 101.52 65.205 ;
     RECT  2.16 65.475 41.148 65.745 ;
     RECT  83.052 65.475 101.52 65.745 ;
     RECT  2.16 66.015 41.148 66.285 ;
     RECT  83.052 66.015 101.52 66.285 ;
     RECT  2.16 66.555 41.148 66.825 ;
     RECT  83.052 66.555 101.52 66.825 ;
     RECT  2.16 67.095 41.148 67.365 ;
     RECT  83.052 67.095 101.52 67.365 ;
     RECT  2.16 67.635 41.148 67.905 ;
     RECT  83.052 67.635 101.52 67.905 ;
     RECT  2.16 68.175 41.148 68.445 ;
     RECT  83.052 68.175 101.52 68.445 ;
     RECT  2.16 68.715 41.148 68.985 ;
     RECT  83.052 68.715 101.52 68.985 ;
    LAYER M1 ;
     RECT  2.16 2.151 101.52 41.049 ;
     RECT  43.2 43.2 81 66.984 ;
     RECT  2.16 41.049 41.148 69.129 ;
     RECT  83.052 41.049 101.52 69.129 ;
    LAYER M2 ;
     RECT  1.111 3.654 1.363 3.672 ;
     RECT  1.363 3.312 1.867 3.672 ;
     RECT  1.867 3.114 2.119 3.672 ;
     RECT  2.119 3.042 2.16 3.672 ;
     RECT  0.103 9.63 2.16 9.648 ;
     RECT  0.103 27.072 2.16 27.09 ;
     RECT  0.103 44.352 2.16 44.37 ;
     RECT  0.103 61.632 2.16 61.65 ;
     RECT  5.179 0.036 5.243 0.054 ;
     RECT  20.803 0.036 20.903 0.054 ;
     RECT  2.16 2.151 21.667 69.129 ;
     RECT  21.667 2.106 22.127 69.129 ;
     RECT  23.971 0.036 24.143 0.054 ;
     RECT  34.843 0.036 35.267 0.054 ;
     RECT  22.127 2.151 37.399 69.129 ;
     RECT  37.399 1.728 37.535 69.129 ;
     RECT  37.903 1.152 38.039 1.17 ;
     RECT  37.535 2.151 38.407 69.129 ;
     RECT  38.407 2.106 38.651 69.129 ;
     RECT  38.407 0.036 39.011 0.054 ;
     RECT  40.135 0.036 40.235 0.054 ;
     RECT  38.651 2.151 41.148 69.129 ;
     RECT  41.148 43.038 41.315 45.324 ;
     RECT  41.148 51.876 41.459 53.424 ;
     RECT  41.459 51.876 41.603 53.28 ;
     RECT  41.148 54.342 41.603 63.81 ;
     RECT  41.148 64.566 41.603 65.7 ;
     RECT  41.148 48.276 41.639 49.5 ;
     RECT  41.603 52.992 41.639 53.28 ;
     RECT  41.603 54.414 41.639 54.432 ;
     RECT  41.603 55.26 41.639 55.44 ;
     RECT  41.603 56.502 41.639 59.562 ;
     RECT  41.603 64.566 41.639 65.268 ;
     RECT  41.148 2.151 41.719 41.049 ;
     RECT  41.719 1.728 41.855 41.049 ;
     RECT  41.148 50.256 42.179 51.12 ;
     RECT  41.639 56.502 42.179 56.754 ;
     RECT  41.639 57.582 42.179 59.562 ;
     RECT  41.603 60.552 42.179 63.81 ;
     RECT  41.315 44.73 42.215 45.324 ;
     RECT  41.639 48.276 42.215 49.266 ;
     RECT  42.179 60.786 42.215 63.684 ;
     RECT  42.215 44.73 42.251 44.748 ;
     RECT  41.315 43.038 42.467 43.704 ;
     RECT  41.855 2.151 42.691 41.049 ;
     RECT  42.655 42.732 42.763 42.75 ;
     RECT  42.763 42.651 43.007 42.75 ;
     RECT  42.467 43.542 43.2 43.704 ;
     RECT  42.215 48.978 43.2 48.996 ;
     RECT  42.179 50.256 43.2 50.274 ;
     RECT  41.639 52.992 43.2 53.01 ;
     RECT  41.639 55.422 43.2 55.44 ;
     RECT  42.179 57.924 43.2 59.49 ;
     RECT  42.215 60.786 43.2 62.19 ;
     RECT  42.215 63.486 43.2 63.504 ;
     RECT  41.639 64.566 43.2 65.124 ;
     RECT  42.691 2.151 43.835 41.589 ;
     RECT  43.835 2.151 44.195 41.094 ;
     RECT  51.583 0.036 51.827 0.054 ;
     RECT  44.195 2.151 52.951 41.049 ;
     RECT  52.951 2.106 53.059 41.049 ;
     RECT  53.059 2.034 53.231 41.049 ;
     RECT  54.319 0.036 54.527 0.054 ;
     RECT  53.231 2.151 54.607 41.049 ;
     RECT  54.607 2.106 55.427 41.049 ;
     RECT  55.427 2.151 56.623 41.049 ;
     RECT  56.623 1.728 56.831 41.049 ;
     RECT  57.055 0.036 57.803 0.054 ;
     RECT  67.279 0.036 67.379 0.054 ;
     RECT  56.831 2.151 67.891 41.049 ;
     RECT  67.891 2.106 68.035 41.049 ;
     RECT  68.035 1.728 68.207 41.049 ;
     RECT  68.207 2.106 70.043 41.049 ;
     RECT  72.571 0.036 73.175 0.054 ;
     RECT  74.443 0.036 74.543 0.054 ;
     RECT  74.659 1.152 74.759 1.17 ;
     RECT  43.2 43.2 76.567 66.984 ;
     RECT  75.487 0.036 79.159 0.054 ;
     RECT  79.087 1.152 79.187 1.17 ;
     RECT  70.043 2.151 79.195 41.049 ;
     RECT  79.159 0.036 80.131 0.09 ;
     RECT  76.567 42.462 80.455 66.984 ;
     RECT  80.455 41.886 81 66.984 ;
     RECT  80.131 0.036 81.463 0.234 ;
     RECT  82.291 47.286 82.651 47.304 ;
     RECT  81 41.886 82.831 42.48 ;
     RECT  81.463 0.036 82.895 0.279 ;
     RECT  79.195 2.106 83.052 41.049 ;
     RECT  82.831 41.886 83.052 42.786 ;
     RECT  82.651 43.812 83.052 43.83 ;
     RECT  82.651 45.738 83.052 45.756 ;
     RECT  82.651 46.656 83.052 47.304 ;
     RECT  82.651 48.132 83.052 48.69 ;
     RECT  82.651 62.136 83.052 62.154 ;
     RECT  82.651 62.982 83.052 63 ;
     RECT  82.651 65.682 83.052 66.24 ;
     RECT  83.047 1.152 83.147 1.17 ;
     RECT  83.052 2.106 83.227 69.129 ;
     RECT  82.895 0.072 83.399 0.279 ;
     RECT  83.399 0.144 83.651 0.279 ;
     RECT  83.651 0.216 83.903 0.279 ;
     RECT  84.055 1.152 84.155 1.17 ;
     RECT  83.903 0.261 84.443 0.279 ;
     RECT  83.227 2.034 85.235 69.129 ;
     RECT  85.531 0.036 85.855 0.054 ;
     RECT  85.855 0.036 85.927 0.126 ;
     RECT  85.927 0.036 86.315 0.594 ;
     RECT  86.315 0.036 86.459 0.126 ;
     RECT  86.459 0.108 87.223 0.126 ;
     RECT  87.223 0.036 88.231 0.126 ;
     RECT  88.231 0.036 88.267 0.594 ;
     RECT  88.267 0.036 88.475 1.17 ;
     RECT  88.475 1.152 88.511 1.17 ;
     RECT  88.475 0.036 89.015 0.126 ;
     RECT  89.015 0.036 89.663 0.054 ;
     RECT  85.235 2.106 90.023 69.129 ;
     RECT  90.535 1.116 90.815 1.134 ;
     RECT  90.787 0.036 90.887 0.054 ;
     RECT  95.323 1.152 95.423 1.17 ;
     RECT  96.439 1.224 96.511 1.242 ;
     RECT  96.511 1.152 96.611 1.242 ;
     RECT  99.571 0.036 99.743 0.054 ;
     RECT  90.023 2.151 100.399 69.129 ;
     RECT  100.399 2.106 100.895 69.129 ;
     RECT  100.895 2.151 101.52 69.129 ;
     RECT  101.52 10.71 101.543 10.728 ;
     RECT  101.52 58.5 101.651 58.518 ;
     RECT  101.52 9.288 101.939 9.306 ;
     RECT  101.52 48.438 101.939 48.456 ;
     RECT  101.52 2.502 102.011 4.176 ;
     RECT  101.52 7.938 102.011 7.956 ;
     RECT  101.52 15.462 102.011 15.48 ;
     RECT  101.52 19.278 102.011 19.296 ;
     RECT  101.52 24.372 102.011 24.39 ;
     RECT  101.52 34.398 102.011 34.416 ;
     RECT  101.52 38.142 102.011 38.16 ;
     RECT  101.52 45.702 102.011 45.72 ;
     RECT  101.52 49.482 102.011 49.5 ;
     RECT  101.52 50.832 102.011 50.85 ;
     RECT  101.52 53.298 102.011 53.316 ;
     RECT  101.52 54.612 102.011 54.63 ;
     RECT  101.52 55.692 102.011 55.71 ;
     RECT  101.52 64.602 102.011 64.62 ;
     RECT  102.011 2.502 102.047 3.474 ;
     RECT  101.52 6.66 102.047 6.804 ;
     RECT  101.52 17.892 102.047 17.91 ;
     RECT  101.52 20.394 102.047 20.412 ;
     RECT  101.52 26.91 102.047 26.928 ;
     RECT  101.52 28.26 102.047 28.278 ;
     RECT  101.52 63.252 102.047 63.27 ;
     RECT  102.019 0.036 102.119 0.054 ;
     RECT  102.047 6.786 102.119 6.804 ;
     RECT  102.047 3.456 102.299 3.474 ;
     RECT  101.52 13.068 102.515 13.086 ;
     RECT  101.52 59.778 102.515 59.796 ;
     RECT  102.047 2.502 102.551 2.52 ;
     RECT  101.52 5.31 102.587 5.328 ;
     RECT  101.52 14.382 102.587 14.4 ;
     RECT  101.52 16.812 102.587 16.83 ;
     RECT  101.52 21.942 102.587 21.96 ;
     RECT  101.52 23.022 102.587 23.04 ;
     RECT  101.52 25.722 102.587 25.74 ;
     RECT  101.52 31.932 102.587 31.95 ;
     RECT  101.52 33.282 102.587 33.3 ;
     RECT  101.52 35.442 102.587 35.46 ;
     RECT  101.52 37.062 102.587 37.08 ;
     RECT  101.52 39.492 102.587 39.51 ;
     RECT  101.52 40.842 102.587 40.86 ;
     RECT  101.52 41.922 102.587 41.94 ;
     RECT  101.52 43.272 102.587 43.29 ;
     RECT  101.52 46.782 102.587 46.8 ;
     RECT  101.52 51.912 102.587 51.93 ;
     RECT  101.52 57.042 102.587 57.06 ;
     RECT  101.52 60.822 102.587 60.84 ;
     RECT  101.52 62.172 102.587 62.19 ;
     RECT  101.52 65.952 102.587 65.97 ;
     RECT  101.52 67.302 102.587 67.32 ;
     RECT  101.52 44.352 102.623 44.37 ;
     RECT  101.52 68.382 102.623 68.4 ;
    LAYER M3 ;
     RECT  66.546 0.012 66.78 0.031 ;
     RECT  66.798 0.012 67.032 0.031 ;
     RECT  67.05 0.012 67.284 0.031 ;
     RECT  67.302 0.012 67.536 0.031 ;
     RECT  67.554 0.012 67.788 0.031 ;
     RECT  67.806 0.012 68.04 0.031 ;
     RECT  68.058 0.012 68.292 0.031 ;
     RECT  68.31 0.012 68.58 0.031 ;
     RECT  68.598 0.012 68.832 0.031 ;
     RECT  68.85 0.012 69.084 0.031 ;
     RECT  69.102 0.012 69.336 0.031 ;
     RECT  69.354 0.012 69.588 0.031 ;
     RECT  69.606 0.012 69.84 0.031 ;
     RECT  69.858 0.012 70.092 0.031 ;
     RECT  70.11 0.012 70.344 0.031 ;
     RECT  70.362 0.012 70.596 0.031 ;
     RECT  70.614 0.012 70.848 0.031 ;
     RECT  70.866 0.012 71.136 0.031 ;
     RECT  71.154 0.012 71.388 0.031 ;
     RECT  71.406 0.012 71.64 0.031 ;
     RECT  71.658 0.012 71.892 0.031 ;
     RECT  71.91 0.012 72.144 0.031 ;
     RECT  72.162 0.012 72.396 0.031 ;
     RECT  72.414 0.012 72.648 0.031 ;
     RECT  72.666 0.012 72.9 0.031 ;
     RECT  72.918 0.012 73.152 0.031 ;
     RECT  73.17 0.012 73.404 0.031 ;
     RECT  73.422 0.012 73.692 0.031 ;
     RECT  73.71 0.012 73.944 0.031 ;
     RECT  73.962 0.012 74.196 0.031 ;
     RECT  74.214 0.012 74.448 0.031 ;
     RECT  82.89 0.012 83.124 0.031 ;
     RECT  83.142 0.012 83.376 0.031 ;
     RECT  83.394 0.012 83.628 0.031 ;
     RECT  83.646 0.012 83.88 0.031 ;
     RECT  83.898 0.012 84.132 0.031 ;
     RECT  84.15 0.012 84.42 0.031 ;
     RECT  84.438 0.012 84.672 0.031 ;
     RECT  84.69 0.012 84.924 0.031 ;
     RECT  84.942 0.012 85.176 0.031 ;
     RECT  85.194 0.012 85.428 0.031 ;
     RECT  85.446 0.012 85.68 0.031 ;
     RECT  85.698 0.012 85.932 0.031 ;
     RECT  85.95 0.012 86.184 0.031 ;
     RECT  86.202 0.012 86.436 0.031 ;
     RECT  86.454 0.012 86.688 0.031 ;
     RECT  86.706 0.012 86.976 0.031 ;
     RECT  86.994 0.012 87.228 0.031 ;
     RECT  87.246 0.012 87.48 0.031 ;
     RECT  87.498 0.012 87.732 0.031 ;
     RECT  87.75 0.012 87.984 0.031 ;
     RECT  88.002 0.012 88.236 0.031 ;
     RECT  88.254 0.012 88.488 0.031 ;
     RECT  88.506 0.012 88.74 0.031 ;
     RECT  88.758 0.012 88.992 0.031 ;
     RECT  89.01 0.012 89.244 0.031 ;
     RECT  89.262 0.012 89.532 0.031 ;
     RECT  89.55 0.012 89.784 0.031 ;
     RECT  89.802 0.012 90.036 0.031 ;
     RECT  90.054 0.012 90.288 0.031 ;
     RECT  90.306 0.012 90.54 0.031 ;
     RECT  90.558 0.012 90.792 0.031 ;
     RECT  82.89 0.031 83.124 0.038 ;
     RECT  83.142 0.031 83.376 0.038 ;
     RECT  83.394 0.031 83.628 0.038 ;
     RECT  83.646 0.031 83.88 0.038 ;
     RECT  83.898 0.031 84.132 0.038 ;
     RECT  84.15 0.031 84.42 0.038 ;
     RECT  84.438 0.031 84.672 0.038 ;
     RECT  84.69 0.031 84.924 0.038 ;
     RECT  84.942 0.031 85.176 0.038 ;
     RECT  85.194 0.031 85.428 0.038 ;
     RECT  85.446 0.031 85.68 0.038 ;
     RECT  85.698 0.031 85.932 0.038 ;
     RECT  85.95 0.031 86.184 0.038 ;
     RECT  86.202 0.031 86.436 0.038 ;
     RECT  86.454 0.031 86.688 0.038 ;
     RECT  86.706 0.031 86.976 0.038 ;
     RECT  86.994 0.031 87.228 0.038 ;
     RECT  87.246 0.031 87.48 0.038 ;
     RECT  87.498 0.031 87.732 0.038 ;
     RECT  87.75 0.031 87.984 0.038 ;
     RECT  88.002 0.031 88.236 0.038 ;
     RECT  88.254 0.031 88.488 0.038 ;
     RECT  88.506 0.031 88.74 0.038 ;
     RECT  88.758 0.031 88.992 0.038 ;
     RECT  89.01 0.031 89.244 0.038 ;
     RECT  89.262 0.031 89.532 0.038 ;
     RECT  89.55 0.031 89.784 0.038 ;
     RECT  89.802 0.031 90.036 0.038 ;
     RECT  90.054 0.031 90.288 0.038 ;
     RECT  90.306 0.031 90.54 0.038 ;
     RECT  90.558 0.031 90.792 0.038 ;
     RECT  90.81 0.031 90.882 0.038 ;
     RECT  82.872 0.038 90.882 0.059 ;
     RECT  83.124 0.059 90.882 0.091 ;
     RECT  83.124 0.091 92.79 0.131 ;
     RECT  93.888 0.091 93.906 0.139 ;
     RECT  83.124 0.131 88.686 0.239 ;
     RECT  93.888 0.139 94.59 0.523 ;
     RECT  96.948 0.091 96.966 0.523 ;
     RECT  98.28 0.091 98.478 0.523 ;
     RECT  81.468 0.256 81.486 0.571 ;
     RECT  95.904 0.523 95.922 0.571 ;
     RECT  96.948 0.523 98.478 0.571 ;
     RECT  61.704 0.571 61.722 1.099 ;
     RECT  66.546 0.031 66.78 0.038 ;
     RECT  66.798 0.031 67.032 0.038 ;
     RECT  67.05 0.031 67.284 0.038 ;
     RECT  67.302 0.031 67.536 0.038 ;
     RECT  67.554 0.031 67.788 0.038 ;
     RECT  67.806 0.031 68.04 0.038 ;
     RECT  68.058 0.031 68.292 0.038 ;
     RECT  68.31 0.031 68.58 0.038 ;
     RECT  68.598 0.031 68.832 0.038 ;
     RECT  68.85 0.031 69.084 0.038 ;
     RECT  69.102 0.031 69.336 0.038 ;
     RECT  69.354 0.031 69.588 0.038 ;
     RECT  69.606 0.031 69.84 0.038 ;
     RECT  69.858 0.031 70.092 0.038 ;
     RECT  70.11 0.031 70.344 0.038 ;
     RECT  70.362 0.031 70.596 0.038 ;
     RECT  70.614 0.031 70.848 0.038 ;
     RECT  70.866 0.031 71.136 0.038 ;
     RECT  71.154 0.031 71.388 0.038 ;
     RECT  71.406 0.031 71.64 0.038 ;
     RECT  71.658 0.031 71.892 0.038 ;
     RECT  71.91 0.031 72.144 0.038 ;
     RECT  72.162 0.031 72.396 0.038 ;
     RECT  72.414 0.031 72.648 0.038 ;
     RECT  72.666 0.031 72.9 0.038 ;
     RECT  72.918 0.031 73.152 0.038 ;
     RECT  73.17 0.031 73.404 0.038 ;
     RECT  73.422 0.031 73.692 0.038 ;
     RECT  73.71 0.031 73.944 0.038 ;
     RECT  73.962 0.031 74.196 0.038 ;
     RECT  74.214 0.031 74.448 0.038 ;
     RECT  74.466 0.031 74.538 0.038 ;
     RECT  66.528 0.038 74.538 1.099 ;
     RECT  10.116 0.571 10.134 1.147 ;
     RECT  31.068 0.571 31.698 1.147 ;
     RECT  33.822 0.012 34.092 0.038 ;
     RECT  34.11 0.012 34.344 0.038 ;
     RECT  34.362 0.012 34.596 0.038 ;
     RECT  34.614 0.012 34.848 0.038 ;
     RECT  34.866 0.012 35.1 0.038 ;
     RECT  35.118 0.012 35.352 0.038 ;
     RECT  35.37 0.012 35.604 0.038 ;
     RECT  35.622 0.012 35.856 0.038 ;
     RECT  35.874 0.012 36.108 0.038 ;
     RECT  36.126 0.012 36.36 0.038 ;
     RECT  36.378 0.012 36.648 0.038 ;
     RECT  36.666 0.012 36.9 0.038 ;
     RECT  36.918 0.012 37.152 0.038 ;
     RECT  37.17 0.012 37.404 0.038 ;
     RECT  37.422 0.012 37.656 0.038 ;
     RECT  37.674 0.012 37.908 0.038 ;
     RECT  37.926 0.012 38.16 0.038 ;
     RECT  38.178 0.012 38.412 0.038 ;
     RECT  38.43 0.012 38.664 0.038 ;
     RECT  38.682 0.012 38.916 0.038 ;
     RECT  38.934 0.012 39.168 0.038 ;
     RECT  39.186 0.012 39.456 0.038 ;
     RECT  39.474 0.012 39.708 0.038 ;
     RECT  39.726 0.012 39.96 0.038 ;
     RECT  39.978 0.012 40.212 0.038 ;
     RECT  40.23 0.012 40.464 0.038 ;
     RECT  40.482 0.012 40.716 0.038 ;
     RECT  40.734 0.012 40.968 0.038 ;
     RECT  40.986 0.012 41.22 0.038 ;
     RECT  41.238 0.012 41.472 0.038 ;
     RECT  41.49 0.012 41.724 0.038 ;
     RECT  33.804 0.038 41.742 1.147 ;
     RECT  42.588 0.571 42.606 1.147 ;
     RECT  61.704 1.099 61.794 1.147 ;
     RECT  62.676 0.571 63.27 1.147 ;
     RECT  66.528 1.099 74.682 1.147 ;
     RECT  75.492 0.031 75.51 1.147 ;
     RECT  77.976 1.099 77.994 1.147 ;
     RECT  79.164 0.067 79.182 1.147 ;
     RECT  80.136 0.211 80.154 1.147 ;
     RECT  83.124 0.239 83.358 1.147 ;
     RECT  84.132 0.239 88.686 1.147 ;
     RECT  95.328 0.571 98.478 1.175 ;
     RECT  44.424 1.147 44.442 1.195 ;
     RECT  28.764 1.147 28.782 1.675 ;
     RECT  45.756 1.627 45.774 1.675 ;
     RECT  1.134 0.012 1.368 0.038 ;
     RECT  1.386 0.012 1.62 0.038 ;
     RECT  1.638 0.012 1.872 0.038 ;
     RECT  1.89 0.012 2.124 0.038 ;
     RECT  2.142 0.012 2.412 0.038 ;
     RECT  2.43 0.012 2.664 0.038 ;
     RECT  2.682 0.012 2.916 0.038 ;
     RECT  2.934 0.012 3.168 0.038 ;
     RECT  3.186 0.012 3.42 0.038 ;
     RECT  3.438 0.012 3.672 0.038 ;
     RECT  3.69 0.012 3.924 0.038 ;
     RECT  3.942 0.012 4.176 0.038 ;
     RECT  4.194 0.012 4.428 0.038 ;
     RECT  4.446 0.012 4.68 0.038 ;
     RECT  4.698 0.012 4.968 0.038 ;
     RECT  4.986 0.012 5.22 0.038 ;
     RECT  5.238 0.012 5.472 0.038 ;
     RECT  5.49 0.012 5.724 0.038 ;
     RECT  5.742 0.012 5.976 0.038 ;
     RECT  5.994 0.012 6.228 0.038 ;
     RECT  6.246 0.012 6.48 0.038 ;
     RECT  6.498 0.012 6.732 0.038 ;
     RECT  6.75 0.012 6.984 0.038 ;
     RECT  7.002 0.012 7.236 0.038 ;
     RECT  7.254 0.012 7.524 0.038 ;
     RECT  7.542 0.012 7.776 0.038 ;
     RECT  7.794 0.012 8.028 0.038 ;
     RECT  8.046 0.012 8.28 0.038 ;
     RECT  8.298 0.012 8.532 0.038 ;
     RECT  8.55 0.012 8.784 0.038 ;
     RECT  8.802 0.012 9.036 0.038 ;
     RECT  1.116 0.038 9.054 1.723 ;
     RECT  10.116 1.147 10.314 1.723 ;
     RECT  11.952 0.571 11.97 1.723 ;
     RECT  14.76 0.091 14.778 1.723 ;
     RECT  17.478 0.012 17.712 0.038 ;
     RECT  17.73 0.012 17.964 0.038 ;
     RECT  17.982 0.012 18.252 0.038 ;
     RECT  18.27 0.012 18.504 0.038 ;
     RECT  18.522 0.012 18.756 0.038 ;
     RECT  18.774 0.012 19.008 0.038 ;
     RECT  19.026 0.012 19.26 0.038 ;
     RECT  19.278 0.012 19.512 0.038 ;
     RECT  19.53 0.012 19.764 0.038 ;
     RECT  19.782 0.012 20.016 0.038 ;
     RECT  20.034 0.012 20.268 0.038 ;
     RECT  20.286 0.012 20.52 0.038 ;
     RECT  20.538 0.012 20.808 0.038 ;
     RECT  20.826 0.012 21.06 0.038 ;
     RECT  21.078 0.012 21.312 0.038 ;
     RECT  21.33 0.012 21.564 0.038 ;
     RECT  21.582 0.012 21.816 0.038 ;
     RECT  21.834 0.012 22.068 0.038 ;
     RECT  22.086 0.012 22.32 0.038 ;
     RECT  22.338 0.012 22.572 0.038 ;
     RECT  22.59 0.012 22.824 0.038 ;
     RECT  22.842 0.012 23.076 0.038 ;
     RECT  23.094 0.012 23.328 0.038 ;
     RECT  23.346 0.012 23.616 0.038 ;
     RECT  23.634 0.012 23.868 0.038 ;
     RECT  23.886 0.012 24.12 0.038 ;
     RECT  24.138 0.012 24.372 0.038 ;
     RECT  24.39 0.012 24.624 0.038 ;
     RECT  24.642 0.012 24.876 0.038 ;
     RECT  24.894 0.012 25.128 0.038 ;
     RECT  25.146 0.012 25.38 0.038 ;
     RECT  17.46 0.038 25.398 1.723 ;
     RECT  27.72 0.571 27.738 1.723 ;
     RECT  28.548 1.675 28.782 1.723 ;
     RECT  29.556 0.571 29.574 1.723 ;
     RECT  31.068 1.147 31.95 1.723 ;
     RECT  33.804 1.147 42.606 1.723 ;
     RECT  44.424 1.195 44.766 1.723 ;
     RECT  45.756 1.675 45.954 1.723 ;
     RECT  47.88 1.147 47.898 1.723 ;
     RECT  50.202 0.012 50.436 0.038 ;
     RECT  50.454 0.012 50.58 0.038 ;
     RECT  50.598 0.012 50.688 0.038 ;
     RECT  50.706 0.012 50.94 0.038 ;
     RECT  50.958 0.012 51.192 0.038 ;
     RECT  51.21 0.012 51.444 0.038 ;
     RECT  51.462 0.012 51.696 0.038 ;
     RECT  51.714 0.012 51.804 0.038 ;
     RECT  51.822 0.012 51.948 0.038 ;
     RECT  51.966 0.012 52.2 0.038 ;
     RECT  52.218 0.012 52.488 0.038 ;
     RECT  52.506 0.012 52.74 0.038 ;
     RECT  52.758 0.012 52.992 0.038 ;
     RECT  53.01 0.012 53.244 0.038 ;
     RECT  53.262 0.012 53.496 0.038 ;
     RECT  53.514 0.012 53.748 0.038 ;
     RECT  53.766 0.012 54 0.038 ;
     RECT  54.018 0.012 54.252 0.038 ;
     RECT  54.27 0.012 54.504 0.038 ;
     RECT  54.522 0.012 54.756 0.038 ;
     RECT  54.774 0.012 55.008 0.038 ;
     RECT  55.026 0.012 55.296 0.038 ;
     RECT  55.314 0.012 55.548 0.038 ;
     RECT  55.566 0.012 55.8 0.038 ;
     RECT  55.818 0.012 56.052 0.038 ;
     RECT  56.07 0.012 56.304 0.038 ;
     RECT  56.322 0.012 56.556 0.038 ;
     RECT  56.574 0.012 56.808 0.038 ;
     RECT  56.826 0.012 57.06 0.038 ;
     RECT  57.078 0.012 57.312 0.038 ;
     RECT  57.33 0.012 57.564 0.038 ;
     RECT  57.582 0.012 57.852 0.038 ;
     RECT  57.87 0.012 58.104 0.038 ;
     RECT  50.184 0.038 58.122 1.723 ;
     RECT  61.704 1.147 63.882 1.723 ;
     RECT  65.7 1.147 65.718 1.723 ;
     RECT  66.528 1.147 74.754 1.723 ;
     RECT  75.492 1.147 76.086 1.723 ;
     RECT  77.076 1.147 77.094 1.723 ;
     RECT  77.976 1.147 78.174 1.723 ;
     RECT  79.092 1.147 79.182 1.723 ;
     RECT  80.136 1.147 80.226 1.723 ;
     RECT  81.468 0.571 81.918 1.723 ;
     RECT  82.764 1.147 88.686 1.723 ;
     RECT  27.252 1.723 42.606 1.771 ;
     RECT  44.028 1.723 44.802 1.771 ;
     RECT  45.756 1.723 63.99 2.143 ;
     RECT  75.492 1.723 88.686 2.143 ;
     RECT  89.532 0.131 92.79 2.143 ;
     RECT  1.116 1.723 26.442 2.191 ;
     RECT  27.252 1.771 44.802 2.191 ;
     RECT  45.615 2.143 63.99 2.191 ;
     RECT  65.052 1.723 74.754 2.191 ;
     RECT  75.492 2.143 92.79 2.191 ;
     RECT  93.564 0.523 94.59 2.191 ;
     RECT  95.4 1.175 98.478 2.191 ;
     RECT  99.234 0.012 99.468 0.038 ;
     RECT  99.486 0.012 99.72 0.038 ;
     RECT  99.738 0.012 99.972 0.038 ;
     RECT  99.99 0.012 100.26 0.038 ;
     RECT  100.278 0.012 100.512 0.038 ;
     RECT  100.53 0.012 100.764 0.038 ;
     RECT  100.782 0.012 101.016 0.038 ;
     RECT  101.034 0.012 101.268 0.038 ;
     RECT  101.286 0.012 101.52 0.038 ;
     RECT  101.538 0.012 101.772 0.038 ;
     RECT  101.79 0.012 102.024 0.038 ;
     RECT  102.042 0.012 102.276 0.038 ;
     RECT  102.294 0.012 102.528 0.038 ;
     RECT  99.216 0.038 102.546 2.191 ;
     RECT  1.116 2.191 26.514 2.263 ;
     RECT  27.252 2.191 63.99 2.263 ;
     RECT  65.052 2.191 102.546 2.263 ;
     RECT  1.116 2.263 102.546 2.525 ;
     RECT  1.116 2.525 102.294 3.479 ;
     RECT  1.116 3.479 102.114 3.605 ;
     RECT  1.116 3.605 1.134 3.677 ;
     RECT  2.304 3.605 102.114 3.749 ;
     RECT  2.376 3.749 102.114 4.919 ;
     RECT  2.376 4.919 101.358 4.955 ;
     RECT  2.376 4.955 80.406 5.021 ;
     RECT  80.244 5.021 80.406 5.189 ;
     RECT  2.376 5.021 79.254 5.261 ;
     RECT  81.144 4.955 101.358 5.297 ;
     RECT  102.096 4.919 102.114 5.305 ;
     RECT  102.096 5.305 102.582 5.405 ;
     RECT  81.144 5.297 101.142 5.567 ;
     RECT  2.376 5.261 78.93 5.575 ;
     RECT  80.388 5.189 80.406 5.707 ;
     RECT  81.144 5.567 101.07 5.707 ;
     RECT  80.388 5.707 101.07 5.909 ;
     RECT  2.34 5.575 78.93 6.115 ;
     RECT  2.34 6.115 79.326 6.151 ;
     RECT  2.34 6.151 79.47 6.187 ;
     RECT  80.388 5.909 100.89 6.187 ;
     RECT  102.096 5.405 102.114 6.655 ;
     RECT  2.34 6.187 100.89 6.691 ;
     RECT  102.024 6.655 102.114 6.691 ;
     RECT  2.34 6.691 102.114 6.809 ;
     RECT  2.34 6.809 101.394 7.079 ;
     RECT  2.34 7.079 101.106 7.259 ;
     RECT  2.34 7.259 100.962 7.469 ;
     RECT  99.54 7.469 100.962 7.889 ;
     RECT  101.988 7.915 102.006 7.961 ;
     RECT  2.34 7.469 98.766 8.159 ;
     RECT  96.696 8.159 98.766 8.275 ;
     RECT  99.54 7.889 100.746 8.275 ;
     RECT  96.696 8.275 100.746 8.537 ;
     RECT  2.34 8.159 95.922 9.067 ;
     RECT  96.696 8.537 100.53 9.067 ;
     RECT  101.916 9.163 101.934 9.311 ;
     RECT  2.34 9.067 100.53 9.383 ;
     RECT  76.32 9.383 100.53 9.509 ;
     RECT  76.32 9.509 100.242 9.545 ;
     RECT  0.108 9.625 0.126 9.677 ;
     RECT  2.34 9.383 75.51 10.291 ;
     RECT  76.392 9.545 100.242 10.291 ;
     RECT  2.34 10.291 100.242 10.391 ;
     RECT  2.415 10.391 100.242 10.399 ;
     RECT  2.415 10.399 100.674 10.589 ;
     RECT  101.52 10.411 101.538 10.733 ;
     RECT  2.415 10.589 100.314 11.371 ;
     RECT  2.415 11.371 100.35 11.641 ;
     RECT  2.376 11.641 100.35 11.669 ;
     RECT  2.376 11.669 100.314 11.693 ;
     RECT  101.376 11.707 101.394 11.813 ;
     RECT  102.492 12.955 102.51 13.091 ;
     RECT  2.415 11.693 100.314 13.441 ;
     RECT  2.415 13.441 100.386 13.559 ;
     RECT  2.415 13.559 100.278 13.595 ;
     RECT  2.415 13.595 100.242 13.667 ;
     RECT  2.415 13.667 100.098 13.675 ;
     RECT  102.564 14.203 102.582 14.405 ;
     RECT  2.376 13.675 100.098 14.719 ;
     RECT  2.376 14.719 100.17 14.791 ;
     RECT  2.376 14.791 100.314 14.909 ;
     RECT  2.376 14.909 100.17 15.053 ;
     RECT  2.376 15.053 99.99 15.215 ;
     RECT  101.088 15.061 101.106 15.323 ;
     RECT  101.988 15.448 102.006 15.485 ;
     RECT  50.256 15.215 99.99 15.871 ;
     RECT  2.376 15.215 49.41 16.069 ;
     RECT  50.256 15.871 100.278 16.069 ;
     RECT  2.376 16.069 100.278 16.105 ;
     RECT  2.376 16.105 100.458 16.367 ;
     RECT  2.376 16.367 100.314 16.529 ;
     RECT  102.564 16.747 102.582 16.835 ;
     RECT  2.415 16.529 100.314 17.105 ;
     RECT  4.536 17.105 100.314 17.141 ;
     RECT  4.608 17.141 100.314 17.221 ;
     RECT  101.304 17.491 101.322 17.681 ;
     RECT  102.024 17.887 102.042 18.029 ;
     RECT  4.608 17.221 100.53 18.031 ;
     RECT  4.608 18.031 100.89 18.157 ;
     RECT  4.464 18.157 100.89 18.265 ;
     RECT  4.212 18.265 100.89 18.455 ;
     RECT  4.212 18.455 100.674 18.995 ;
     RECT  101.988 19.243 102.006 19.301 ;
     RECT  2.415 17.105 3.294 19.345 ;
     RECT  4.212 18.995 100.35 19.345 ;
     RECT  2.415 19.345 100.35 19.885 ;
     RECT  101.088 19.201 101.106 19.885 ;
     RECT  2.415 19.885 101.106 20.075 ;
     RECT  101.088 20.075 101.106 20.381 ;
     RECT  102.024 20.389 102.042 20.525 ;
     RECT  2.415 20.075 100.35 20.621 ;
     RECT  2.415 20.621 100.278 21.739 ;
     RECT  2.415 21.739 100.926 21.929 ;
     RECT  102.564 21.787 102.582 21.965 ;
     RECT  2.415 21.929 100.278 22.919 ;
     RECT  2.415 22.919 100.242 23.009 ;
     RECT  102.564 23.017 102.582 23.069 ;
     RECT  2.415 23.009 100.17 23.165 ;
     RECT  2.415 23.165 86.85 23.819 ;
     RECT  5.04 23.819 86.85 23.971 ;
     RECT  87.696 23.165 100.17 23.971 ;
     RECT  5.04 23.971 100.17 24.241 ;
     RECT  101.988 24.283 102.006 24.395 ;
     RECT  5.04 24.241 100.35 24.511 ;
     RECT  2.415 23.819 4.266 24.745 ;
     RECT  5.04 24.511 100.422 24.745 ;
     RECT  2.415 24.745 100.422 24.781 ;
     RECT  2.415 24.781 100.602 25.079 ;
     RECT  102.564 25.531 102.582 25.745 ;
     RECT  2.415 25.079 100.17 26.059 ;
     RECT  2.415 26.059 100.314 26.131 ;
     RECT  2.415 26.131 100.386 26.285 ;
     RECT  6.084 26.285 100.386 26.365 ;
     RECT  2.415 26.285 5.346 26.789 ;
     RECT  102.024 26.827 102.042 26.933 ;
     RECT  0.108 26.971 0.126 27.095 ;
     RECT  6.084 26.365 101.178 27.139 ;
     RECT  2.415 26.789 4.842 27.679 ;
     RECT  5.616 27.139 101.178 27.679 ;
     RECT  2.415 27.679 101.178 28.021 ;
     RECT  2.415 28.021 101.214 28.139 ;
     RECT  2.415 28.139 100.638 28.175 ;
     RECT  102.024 28.075 102.042 28.283 ;
     RECT  5.076 28.175 100.638 28.859 ;
     RECT  2.415 28.175 4.266 28.921 ;
     RECT  5.076 28.859 100.17 28.921 ;
     RECT  2.415 28.921 100.17 29.021 ;
     RECT  2.415 29.021 2.697 29.029 ;
     RECT  2.34 29.029 2.697 29.069 ;
     RECT  101.448 29.299 101.466 29.357 ;
     RECT  3.42 29.021 100.17 30.029 ;
     RECT  4.032 30.029 100.17 30.065 ;
     RECT  2.415 29.069 2.697 30.139 ;
     RECT  2.415 30.139 3.294 30.179 ;
     RECT  4.032 30.065 100.134 30.335 ;
     RECT  101.448 30.568 101.466 30.605 ;
     RECT  4.032 30.335 100.026 31.289 ;
     RECT  59.04 31.289 100.026 31.729 ;
     RECT  59.04 31.729 100.566 31.919 ;
     RECT  102.564 31.867 102.582 31.955 ;
     RECT  4.068 31.289 58.302 32.035 ;
     RECT  59.04 31.919 100.026 32.035 ;
     RECT  4.068 32.035 100.026 32.189 ;
     RECT  97.056 32.189 100.026 32.333 ;
     RECT  4.068 32.189 96.066 32.495 ;
     RECT  4.104 32.495 96.066 32.567 ;
     RECT  60.804 32.567 96.066 32.639 ;
     RECT  4.104 32.567 60.066 32.729 ;
     RECT  60.804 32.639 73.17 32.729 ;
     RECT  73.944 32.639 96.066 32.729 ;
     RECT  73.944 32.729 95.958 32.765 ;
     RECT  60.84 32.729 73.098 32.873 ;
     RECT  4.176 32.729 60.066 32.999 ;
     RECT  73.944 32.765 95.814 33.035 ;
     RECT  97.056 32.333 97.254 33.067 ;
     RECT  4.176 32.999 60.03 33.071 ;
     RECT  97.056 33.067 97.398 33.079 ;
     RECT  97.056 33.079 97.578 33.151 ;
     RECT  98.388 32.333 100.026 33.151 ;
     RECT  97.056 33.151 100.026 33.269 ;
     RECT  100.872 33.079 100.89 33.269 ;
     RECT  60.84 32.873 73.062 33.305 ;
     RECT  77.436 33.035 95.814 33.305 ;
     RECT  97.056 33.269 97.398 33.305 ;
     RECT  102.564 33.115 102.582 33.305 ;
     RECT  94.104 33.305 95.814 33.413 ;
     RECT  77.436 33.305 87.03 33.449 ;
     RECT  73.944 33.035 76.698 33.539 ;
     RECT  77.436 33.449 86.202 33.539 ;
     RECT  77.436 33.539 86.094 33.575 ;
     RECT  88.02 33.305 93.006 33.575 ;
     RECT  94.215 33.413 95.814 33.575 ;
     RECT  4.176 33.071 59.994 33.611 ;
     RECT  77.436 33.575 81.234 33.611 ;
     RECT  90.216 33.575 93.006 33.611 ;
     RECT  61.815 33.305 73.062 33.629 ;
     RECT  77.436 33.611 81.198 33.629 ;
     RECT  70.128 33.629 73.062 33.643 ;
     RECT  73.944 33.539 76.59 33.643 ;
     RECT  61.815 33.629 69.318 33.647 ;
     RECT  4.356 33.611 59.994 33.719 ;
     RECT  79.704 33.629 81.198 33.719 ;
     RECT  87.012 33.449 87.03 33.719 ;
     RECT  4.572 33.719 59.994 33.809 ;
     RECT  61.815 33.647 67.497 33.809 ;
     RECT  70.128 33.643 76.59 33.809 ;
     RECT  90.828 33.611 93.006 33.809 ;
     RECT  90.828 33.809 92.862 33.845 ;
     RECT  62.82 33.809 67.497 33.917 ;
     RECT  77.436 33.629 78.786 33.925 ;
     RECT  77.364 33.925 78.786 33.953 ;
     RECT  79.74 33.719 81.198 33.953 ;
     RECT  58.464 33.809 59.994 33.961 ;
     RECT  60.84 33.305 61.074 33.961 ;
     RECT  77.364 33.953 78.714 33.965 ;
     RECT  62.964 33.917 67.497 33.989 ;
     RECT  77.508 33.965 78.714 33.989 ;
     RECT  91.044 33.845 92.862 34.013 ;
     RECT  58.464 33.961 61.074 34.079 ;
     RECT  70.164 33.809 76.59 34.079 ;
     RECT  77.508 33.989 78.426 34.079 ;
     RECT  79.74 33.953 81.018 34.079 ;
     RECT  91.908 34.013 92.862 34.079 ;
     RECT  70.416 34.079 76.59 34.109 ;
     RECT  58.464 34.079 60.39 34.115 ;
     RECT  68.328 33.647 69.318 34.115 ;
     RECT  70.74 34.109 76.59 34.115 ;
     RECT  77.508 34.079 78.318 34.115 ;
     RECT  64.152 33.989 67.497 34.151 ;
     RECT  70.74 34.115 75.51 34.151 ;
     RECT  77.508 34.115 78.297 34.151 ;
     RECT  88.02 33.575 89.19 34.151 ;
     RECT  58.716 34.115 60.318 34.187 ;
     RECT  62.964 33.989 63.198 34.187 ;
     RECT  64.152 34.151 65.754 34.187 ;
     RECT  66.708 34.151 67.497 34.187 ;
     RECT  70.812 34.151 70.83 34.187 ;
     RECT  95.76 33.575 95.814 34.195 ;
     RECT  97.056 33.305 97.254 34.195 ;
     RECT  98.172 33.269 100.026 34.223 ;
     RECT  71.676 34.151 74.718 34.253 ;
     RECT  64.152 34.187 65.646 34.259 ;
     RECT  68.976 34.115 69.318 34.349 ;
     RECT  73.62 34.253 74.718 34.349 ;
     RECT  75.492 34.151 75.51 34.349 ;
     RECT  101.196 34.231 101.214 34.349 ;
     RECT  59.22 34.187 60.318 34.385 ;
     RECT  64.908 34.259 65.646 34.385 ;
     RECT  71.676 34.253 72.897 34.385 ;
     RECT  73.62 34.349 74.574 34.385 ;
     RECT  95.76 34.195 97.254 34.385 ;
     RECT  74.124 34.385 74.394 34.421 ;
     RECT  101.988 34.363 102.006 34.421 ;
     RECT  71.676 34.385 71.694 34.457 ;
     RECT  69.3 34.349 69.318 34.493 ;
     RECT  74.124 34.421 74.142 34.493 ;
     RECT  59.832 34.385 60.318 34.619 ;
     RECT  64.152 34.259 64.17 34.619 ;
     RECT  64.908 34.385 65.394 34.655 ;
     RECT  95.796 34.385 97.254 34.655 ;
     RECT  60.012 34.619 60.318 34.691 ;
     RECT  60.3 34.691 60.318 34.763 ;
     RECT  98.388 34.223 100.026 34.763 ;
     RECT  61.815 33.809 62.097 34.771 ;
     RECT  4.572 33.809 57.546 34.795 ;
     RECT  97.236 34.655 97.254 34.799 ;
     RECT  4.572 34.795 57.618 34.889 ;
     RECT  61.815 34.771 62.73 34.889 ;
     RECT  64.908 34.655 65.25 34.889 ;
     RECT  4.788 34.889 57.618 34.961 ;
     RECT  65.124 34.889 65.25 34.961 ;
     RECT  65.124 34.961 65.142 34.997 ;
     RECT  5.832 34.961 57.618 35.041 ;
     RECT  98.388 34.763 99.954 35.041 ;
     RECT  82.296 33.575 86.094 35.131 ;
     RECT  5.832 35.041 57.726 35.195 ;
     RECT  94.215 33.575 94.497 35.323 ;
     RECT  95.796 34.655 96.426 35.323 ;
     RECT  5.832 35.195 57.438 35.339 ;
     RECT  97.704 35.041 99.954 35.339 ;
     RECT  94.215 35.323 96.426 35.429 ;
     RECT  95.292 35.429 96.354 35.501 ;
     RECT  99.615 35.339 99.954 35.581 ;
     RECT  91.044 34.013 91.062 35.609 ;
     RECT  102.564 35.437 102.582 35.645 ;
     RECT  95.292 35.501 95.886 35.699 ;
     RECT  99.615 35.581 100.242 35.699 ;
     RECT  95.796 35.699 95.886 35.735 ;
     RECT  82.296 35.131 86.706 35.899 ;
     RECT  88.02 34.151 89.097 35.941 ;
     RECT  82.296 35.899 87.138 35.947 ;
     RECT  5.832 35.339 57.006 35.969 ;
     RECT  60.228 35.899 60.246 35.969 ;
     RECT  88.02 35.941 89.19 35.981 ;
     RECT  61.815 34.889 62.097 36.121 ;
     RECT  82.296 35.947 87.21 36.239 ;
     RECT  60.876 36.211 60.894 36.269 ;
     RECT  61.776 36.121 62.097 36.269 ;
     RECT  4.788 34.961 4.806 36.311 ;
     RECT  9.9 35.969 57.006 36.461 ;
     RECT  36.9 36.461 57.006 36.653 ;
     RECT  56.415 36.653 57.006 36.689 ;
     RECT  36.9 36.653 55.422 36.779 ;
     RECT  5.832 35.969 9.162 36.797 ;
     RECT  97.704 35.339 98.406 36.895 ;
     RECT  99.615 35.699 99.954 36.895 ;
     RECT  7.38 36.797 9.162 36.931 ;
     RECT  9.9 36.461 35.982 36.931 ;
     RECT  99.615 36.895 100.314 36.931 ;
     RECT  97.236 36.895 98.406 37.003 ;
     RECT  99.18 36.931 100.782 37.003 ;
     RECT  54.9 36.779 55.422 37.049 ;
     RECT  97.236 37.003 100.782 37.049 ;
     RECT  5.832 36.797 6.426 37.085 ;
     RECT  36.9 36.779 54.162 37.085 ;
     RECT  102.564 36.907 102.582 37.085 ;
     RECT  99.615 37.049 99.954 37.121 ;
     RECT  54.9 37.049 55.314 37.193 ;
     RECT  7.38 36.931 35.982 37.319 ;
     RECT  54.9 37.193 54.954 37.319 ;
     RECT  82.296 36.239 86.706 37.327 ;
     RECT  54.9 37.319 54.918 37.355 ;
     RECT  80.46 34.079 81.018 37.355 ;
     RECT  88.02 35.981 89.097 37.355 ;
     RECT  36.9 37.085 54.126 37.363 ;
     RECT  36.72 37.363 54.126 37.427 ;
     RECT  10.044 37.319 35.982 37.589 ;
     RECT  52.056 37.427 54.126 37.589 ;
     RECT  10.116 37.589 35.982 37.625 ;
     RECT  36.72 37.427 51.297 37.625 ;
     RECT  52.056 37.589 52.938 37.625 ;
     RECT  54.108 37.589 54.126 37.625 ;
     RECT  88.02 37.355 88.038 37.633 ;
     RECT  10.368 37.625 35.982 37.661 ;
     RECT  22.212 37.661 35.982 37.669 ;
     RECT  36.72 37.625 44.766 37.669 ;
     RECT  7.38 37.319 9.162 37.709 ;
     RECT  99.615 37.121 99.897 37.939 ;
     RECT  97.236 37.049 98.406 38.011 ;
     RECT  7.38 37.709 8.802 38.039 ;
     RECT  22.212 37.669 44.766 38.045 ;
     RECT  97.236 38.011 98.694 38.129 ;
     RECT  99.615 37.939 100.062 38.129 ;
     RECT  10.368 37.661 21.474 38.165 ;
     RECT  101.988 38.137 102.006 38.189 ;
     RECT  10.368 38.165 10.386 38.201 ;
     RECT  11.484 38.165 21.474 38.201 ;
     RECT  100.62 38.173 100.638 38.309 ;
     RECT  37.008 38.045 44.766 38.371 ;
     RECT  45.54 37.625 51.297 38.371 ;
     RECT  52.056 37.625 52.65 38.399 ;
     RECT  11.664 38.201 21.474 38.435 ;
     RECT  11.952 38.435 21.474 38.551 ;
     RECT  22.212 38.045 36.27 38.551 ;
     RECT  52.524 38.399 52.65 38.551 ;
     RECT  11.952 38.551 36.27 38.579 ;
     RECT  52.524 38.551 52.758 38.579 ;
     RECT  7.815 38.039 8.802 38.669 ;
     RECT  11.952 38.579 12.474 38.669 ;
     RECT  17.136 38.579 36.27 38.669 ;
     RECT  52.632 38.579 52.758 38.669 ;
     RECT  52.632 38.669 52.65 38.705 ;
     RECT  95.796 35.735 95.814 38.749 ;
     RECT  95.796 38.749 95.886 38.777 ;
     RECT  11.952 38.669 12.438 38.813 ;
     RECT  13.215 38.579 16.29 38.813 ;
     RECT  11.952 38.813 11.97 38.939 ;
     RECT  14.328 38.813 16.29 38.939 ;
     RECT  17.316 38.669 36.27 38.939 ;
     RECT  23.364 38.939 36.27 38.947 ;
     RECT  37.008 38.371 51.297 38.947 ;
     RECT  22.248 38.939 22.59 38.957 ;
     RECT  14.328 38.939 14.346 38.975 ;
     RECT  17.316 38.939 21.222 38.975 ;
     RECT  23.364 38.947 51.297 38.975 ;
     RECT  15.084 38.939 15.966 39.047 ;
     RECT  18 38.975 21.222 39.119 ;
     RECT  15.156 39.047 15.966 39.209 ;
     RECT  22.248 38.957 22.302 39.209 ;
     RECT  23.472 38.975 51.297 39.209 ;
     RECT  15.948 39.209 15.966 39.245 ;
     RECT  18.072 39.119 21.222 39.245 ;
     RECT  22.248 39.209 22.266 39.245 ;
     RECT  23.472 39.209 30.366 39.245 ;
     RECT  31.356 39.209 51.297 39.245 ;
     RECT  31.356 39.245 50.202 39.281 ;
     RECT  23.472 39.245 30.042 39.317 ;
     RECT  31.356 39.281 50.058 39.317 ;
     RECT  97.236 38.129 98.406 39.353 ;
     RECT  95.868 38.777 95.886 39.361 ;
     RECT  31.968 39.317 50.058 39.395 ;
     RECT  97.236 39.353 98.334 39.451 ;
     RECT  23.58 39.317 30.042 39.479 ;
     RECT  32.184 39.395 50.058 39.479 ;
     RECT  95.868 39.361 95.958 39.479 ;
     RECT  46.764 39.479 50.058 39.515 ;
     RECT  102.564 39.403 102.582 39.515 ;
     RECT  46.764 39.515 46.818 39.533 ;
     RECT  96.732 39.451 98.334 39.595 ;
     RECT  23.58 39.479 30.006 39.623 ;
     RECT  46.764 39.533 46.782 39.623 ;
     RECT  23.58 39.623 29.934 39.629 ;
     RECT  95.868 39.479 95.886 39.631 ;
     RECT  99.615 38.129 99.897 39.631 ;
     RECT  32.184 39.479 45.897 39.659 ;
     RECT  23.58 39.629 27.342 39.749 ;
     RECT  28.584 39.629 29.934 39.749 ;
     RECT  32.688 39.659 37.674 39.749 ;
     RECT  47.628 39.515 50.058 39.749 ;
     RECT  96.624 39.595 98.334 39.749 ;
     RECT  28.584 39.749 29.697 39.785 ;
     RECT  37.08 39.749 37.566 39.785 ;
     RECT  38.484 39.659 45.897 39.785 ;
     RECT  47.628 39.749 47.646 39.785 ;
     RECT  48.42 39.749 50.058 39.785 ;
     RECT  99.615 39.631 100.494 39.785 ;
     RECT  43.776 39.785 45.897 39.857 ;
     RECT  50.04 39.785 50.058 39.857 ;
     RECT  23.58 39.749 25.038 39.893 ;
     RECT  43.776 39.857 44.874 39.893 ;
     RECT  25.848 39.749 26.406 40.019 ;
     RECT  27.252 39.749 27.342 40.019 ;
     RECT  32.688 39.749 36.198 40.019 ;
     RECT  95.796 39.631 95.886 40.019 ;
     RECT  27.252 40.019 27.27 40.055 ;
     RECT  32.688 40.019 33.75 40.055 ;
     RECT  38.484 39.785 43.038 40.055 ;
     RECT  48.42 39.785 48.978 40.091 ;
     RECT  38.7 40.055 40.59 40.127 ;
     RECT  25.956 40.019 26.406 40.163 ;
     RECT  38.7 40.127 40.497 40.199 ;
     RECT  26.388 40.163 26.406 40.289 ;
     RECT  33.48 40.055 33.75 40.289 ;
     RECT  34.815 40.019 36.198 40.289 ;
     RECT  37.08 39.785 37.314 40.289 ;
     RECT  38.952 40.199 40.497 40.289 ;
     RECT  43.812 39.893 44.874 40.289 ;
     RECT  48.888 40.091 48.978 40.289 ;
     RECT  33.48 40.289 33.57 40.325 ;
     RECT  34.815 40.289 35.406 40.325 ;
     RECT  43.812 40.289 44.658 40.325 ;
     RECT  48.888 40.289 48.906 40.325 ;
     RECT  33.552 40.325 33.57 40.397 ;
     RECT  36.18 40.289 36.198 40.397 ;
     RECT  39.06 40.289 40.497 40.559 ;
     RECT  41.4 40.055 43.038 40.675 ;
     RECT  43.812 40.325 44.19 40.675 ;
     RECT  39.528 40.559 40.497 40.703 ;
     RECT  94.215 35.429 94.497 40.711 ;
     RECT  45.615 39.857 45.897 40.787 ;
     RECT  51.015 39.245 51.297 40.787 ;
     RECT  56.415 36.689 56.697 40.787 ;
     RECT  61.815 36.269 62.097 40.787 ;
     RECT  67.215 34.187 67.497 40.787 ;
     RECT  72.615 34.385 72.897 40.787 ;
     RECT  78.015 34.151 78.297 40.787 ;
     RECT  94.215 40.711 94.842 40.837 ;
     RECT  102.564 40.651 102.582 40.865 ;
     RECT  5.832 37.085 5.85 40.873 ;
     RECT  94.212 40.837 95.022 40.877 ;
     RECT  5.832 40.873 6.246 40.901 ;
     RECT  90.648 40.711 90.666 40.901 ;
     RECT  45.615 40.787 45.705 41.057 ;
     RECT  51.015 40.787 51.105 41.057 ;
     RECT  56.415 40.787 56.505 41.057 ;
     RECT  61.815 40.787 61.905 41.057 ;
     RECT  67.215 40.787 67.305 41.057 ;
     RECT  72.615 40.787 72.705 41.057 ;
     RECT  78.015 40.787 78.105 41.057 ;
     RECT  41.4 40.675 44.19 41.099 ;
     RECT  94.215 40.877 95.022 41.135 ;
     RECT  99.615 39.785 99.897 41.143 ;
     RECT  96.66 39.749 98.334 41.215 ;
     RECT  41.4 41.099 43.83 41.594 ;
     RECT  99.615 41.143 100.314 41.611 ;
     RECT  34.815 40.325 35.097 41.659 ;
     RECT  41.4 41.594 43.11 41.899 ;
     RECT  80.46 37.355 80.478 41.909 ;
     RECT  96.66 41.215 98.37 41.944 ;
     RECT  99.504 41.611 100.314 41.944 ;
     RECT  102.564 41.899 102.582 41.945 ;
     RECT  96.66 41.944 100.314 41.981 ;
     RECT  13.215 38.813 13.497 42.043 ;
     RECT  99.576 41.981 100.314 42.061 ;
     RECT  13.104 42.043 13.497 42.089 ;
     RECT  34.704 41.659 35.097 42.179 ;
     RECT  36.252 41.851 36.27 42.179 ;
     RECT  99.576 42.061 100.566 42.215 ;
     RECT  99.576 42.215 99.897 42.359 ;
     RECT  95.796 40.019 95.814 42.763 ;
     RECT  82.296 37.327 86.778 42.791 ;
     RECT  95.796 42.763 95.886 42.791 ;
     RECT  29.124 39.785 29.697 43.061 ;
     RECT  99.615 42.359 99.897 43.141 ;
     RECT  41.292 41.899 43.11 43.2 ;
     RECT  76.572 34.115 76.59 43.2 ;
     RECT  102.564 43.195 102.582 43.295 ;
     RECT  100.908 43.231 100.926 43.331 ;
     RECT  7.815 38.669 8.097 43.339 ;
     RECT  6.228 40.901 6.246 43.367 ;
     RECT  96.66 41.981 98.37 43.373 ;
     RECT  99.396 43.141 99.897 43.529 ;
     RECT  82.296 42.791 82.314 43.807 ;
     RECT  83.124 42.791 86.778 43.807 ;
     RECT  82.296 43.807 86.778 43.997 ;
     RECT  41.292 43.2 81 44.069 ;
     RECT  7.416 43.339 8.097 44.185 ;
     RECT  9.036 44.113 9.054 44.185 ;
     RECT  7.416 44.185 9.054 44.339 ;
     RECT  0.108 44.299 0.126 44.375 ;
     RECT  83.16 43.997 86.778 44.381 ;
     RECT  7.416 44.339 8.097 44.455 ;
     RECT  6.444 44.419 6.462 44.477 ;
     RECT  102.6 44.347 102.618 44.477 ;
     RECT  95.868 42.791 95.886 44.539 ;
     RECT  6.228 44.491 6.246 44.609 ;
     RECT  7.308 44.455 8.097 44.609 ;
     RECT  101.376 44.419 101.394 44.609 ;
     RECT  95.796 44.539 95.886 44.617 ;
     RECT  96.66 43.373 98.334 44.617 ;
     RECT  5.148 44.311 5.166 44.645 ;
     RECT  19.98 39.245 20.178 44.753 ;
     RECT  100.692 44.761 100.71 44.915 ;
     RECT  95.796 44.617 98.334 44.987 ;
     RECT  99.615 43.529 99.897 45.301 ;
     RECT  15.156 39.209 15.174 45.329 ;
     RECT  96.66 44.987 98.334 45.329 ;
     RECT  82.296 43.997 82.314 45.499 ;
     RECT  83.196 44.381 86.778 45.499 ;
     RECT  94.215 41.135 94.77 45.595 ;
     RECT  95.796 44.987 95.886 45.595 ;
     RECT  101.988 45.688 102.006 45.725 ;
     RECT  82.296 45.499 86.778 45.761 ;
     RECT  94.215 45.595 95.886 45.805 ;
     RECT  96.66 45.329 98.298 45.805 ;
     RECT  34.815 42.179 35.097 45.832 ;
     RECT  40.215 40.703 40.497 45.832 ;
     RECT  99.615 45.301 99.954 45.841 ;
     RECT  21.204 39.245 21.222 45.869 ;
     RECT  94.215 45.805 98.298 45.959 ;
     RECT  94.215 45.959 96.318 46.067 ;
     RECT  99.615 45.841 100.242 46.067 ;
     RECT  94.215 46.067 96.138 46.103 ;
     RECT  23.58 39.893 24.297 46.109 ;
     RECT  18.54 39.245 18.897 46.253 ;
     RECT  23.904 46.109 24.297 46.409 ;
     RECT  34.704 45.832 35.097 46.409 ;
     RECT  40.104 45.832 40.497 46.409 ;
     RECT  41.4 44.069 81 46.555 ;
     RECT  82.296 45.761 82.314 46.651 ;
     RECT  83.232 45.761 86.778 46.651 ;
     RECT  41.4 46.555 81.09 46.685 ;
     RECT  25.02 39.893 25.038 46.877 ;
     RECT  82.296 46.651 86.778 46.877 ;
     RECT  83.232 46.877 86.778 46.885 ;
     RECT  99.615 46.067 99.954 46.885 ;
     RECT  99.18 46.885 100.278 46.921 ;
     RECT  102.564 46.777 102.582 46.973 ;
     RECT  101.088 46.921 101.106 47.039 ;
     RECT  83.232 46.885 86.814 47.119 ;
     RECT  87.624 37.633 88.038 47.119 ;
     RECT  97.272 45.959 98.298 47.155 ;
     RECT  99.18 46.921 100.314 47.155 ;
     RECT  40.215 46.409 40.497 47.191 ;
     RECT  83.232 47.119 88.038 47.191 ;
     RECT  88.815 37.355 89.097 47.191 ;
     RECT  97.272 47.155 100.314 47.191 ;
     RECT  37.296 40.289 37.314 47.213 ;
     RECT  40.215 47.191 40.59 47.261 ;
     RECT  83.232 47.191 89.097 47.261 ;
     RECT  97.272 47.191 100.35 47.275 ;
     RECT  95.796 46.103 95.814 47.281 ;
     RECT  96.696 47.275 100.35 47.281 ;
     RECT  82.296 46.877 82.314 47.309 ;
     RECT  83.415 47.261 89.097 47.309 ;
     RECT  95.796 47.281 100.35 47.309 ;
     RECT  96.336 47.309 98.298 47.315 ;
     RECT  19.98 44.753 19.998 47.317 ;
     RECT  19.98 47.317 20.502 47.345 ;
     RECT  32.688 40.055 32.706 47.453 ;
     RECT  83.415 47.309 88.038 47.453 ;
     RECT  99.615 47.309 100.35 47.453 ;
     RECT  20.34 47.345 20.502 47.579 ;
     RECT  83.415 47.453 87.534 47.579 ;
     RECT  20.34 47.579 20.358 47.615 ;
     RECT  41.4 46.685 81 47.837 ;
     RECT  26.424 47.551 26.442 47.885 ;
     RECT  82.656 47.803 82.674 47.995 ;
     RECT  83.415 47.579 87.498 47.995 ;
     RECT  41.868 47.837 81 48.029 ;
     RECT  40.215 47.261 40.497 48.271 ;
     RECT  97.38 47.315 98.298 48.271 ;
     RECT  97.38 48.271 98.694 48.389 ;
     RECT  82.656 47.995 87.498 48.433 ;
     RECT  101.916 48.235 101.934 48.461 ;
     RECT  97.38 48.389 98.298 48.467 ;
     RECT  82.656 48.433 87.534 48.505 ;
     RECT  34.815 46.409 35.097 48.523 ;
     RECT  40.215 48.271 41.022 48.523 ;
     RECT  99.615 47.453 99.897 48.541 ;
     RECT  31.716 47.857 31.734 48.557 ;
     RECT  34.704 48.523 35.097 48.569 ;
     RECT  40.104 48.523 41.022 48.569 ;
     RECT  82.656 48.505 87.57 48.659 ;
     RECT  82.656 48.659 87.534 48.695 ;
     RECT  99.18 48.541 99.897 48.695 ;
     RECT  94.215 46.103 94.77 48.929 ;
     RECT  97.488 48.467 98.298 48.965 ;
     RECT  83.196 48.695 87.534 49.001 ;
     RECT  42.192 48.029 81 49.051 ;
     RECT  42.192 49.051 81.09 49.181 ;
     RECT  96.336 47.315 96.354 49.279 ;
     RECT  40.215 48.569 41.022 49.315 ;
     RECT  95.94 49.279 96.354 49.351 ;
     RECT  42.192 49.181 81 49.373 ;
     RECT  99.615 48.695 99.897 49.441 ;
     RECT  97.488 48.965 97.722 49.469 ;
     RECT  40.215 49.315 41.058 49.477 ;
     RECT  42.192 49.373 42.21 49.477 ;
     RECT  101.988 49.477 102.006 49.517 ;
     RECT  95.94 49.351 96.606 49.531 ;
     RECT  95.76 49.531 96.606 49.541 ;
     RECT  99.615 49.441 100.494 49.541 ;
     RECT  40.215 49.477 42.21 49.565 ;
     RECT  95.76 49.541 95.778 49.577 ;
     RECT  83.196 49.001 87.498 49.757 ;
     RECT  96.516 49.541 96.606 49.775 ;
     RECT  98.604 49.513 98.622 49.775 ;
     RECT  97.488 49.469 97.65 49.847 ;
     RECT  83.232 49.757 87.498 50.009 ;
     RECT  41.616 49.565 42.21 50.141 ;
     RECT  43.092 49.373 81 50.279 ;
     RECT  41.616 50.141 42.174 50.299 ;
     RECT  83.304 50.009 87.498 50.315 ;
     RECT  40.215 49.565 40.497 50.323 ;
     RECT  41.508 50.299 42.174 50.323 ;
     RECT  83.304 50.315 87.426 50.333 ;
     RECT  39.744 50.323 42.174 50.423 ;
     RECT  84.888 50.333 87.426 50.549 ;
     RECT  84.888 50.549 87.246 50.657 ;
     RECT  84.888 50.657 86.238 50.693 ;
     RECT  87.228 50.657 87.246 50.693 ;
     RECT  83.304 50.333 83.697 50.717 ;
     RECT  85.896 50.693 86.238 50.729 ;
     RECT  101.988 50.731 102.006 50.855 ;
     RECT  96.588 49.775 96.606 50.899 ;
     RECT  97.488 49.847 97.614 50.899 ;
     RECT  86.112 50.729 86.13 50.909 ;
     RECT  84.888 50.693 84.906 50.957 ;
     RECT  94.215 48.929 94.497 50.971 ;
     RECT  95.4 50.899 95.418 50.971 ;
     RECT  96.588 50.899 97.614 50.971 ;
     RECT  94.215 50.971 97.614 51.089 ;
     RECT  100.656 50.971 100.674 51.089 ;
     RECT  82.656 50.923 82.674 51.101 ;
     RECT  95.256 51.089 97.614 51.101 ;
     RECT  40.215 50.423 42.174 51.125 ;
     RECT  95.94 51.101 97.614 51.125 ;
     RECT  96.192 51.125 97.614 51.161 ;
     RECT  98.568 51.097 98.622 51.241 ;
     RECT  98.352 51.241 98.622 51.269 ;
     RECT  98.352 51.269 98.586 51.395 ;
     RECT  96.588 51.161 97.614 51.467 ;
     RECT  101.088 51.871 101.106 52.007 ;
     RECT  102.564 51.907 102.582 52.013 ;
     RECT  99.615 49.541 99.897 52.015 ;
     RECT  99.18 52.015 99.897 52.051 ;
     RECT  98.352 51.395 98.406 52.168 ;
     RECT  99.18 52.051 100.314 52.168 ;
     RECT  98.352 52.168 100.314 52.169 ;
     RECT  98.352 52.169 99.954 52.205 ;
     RECT  98.352 52.205 98.586 52.313 ;
     RECT  40.215 51.125 41.598 52.789 ;
     RECT  39.528 52.789 41.598 52.889 ;
     RECT  43.2 50.279 81 52.981 ;
     RECT  42.768 52.981 81 53.021 ;
     RECT  39.312 52.987 39.33 53.123 ;
     RECT  97.38 51.467 97.614 53.131 ;
     RECT  98.532 52.313 98.586 53.131 ;
     RECT  99.615 52.205 99.954 53.159 ;
     RECT  97.38 53.131 98.586 53.249 ;
     RECT  40.215 52.889 41.598 53.257 ;
     RECT  101.988 53.275 102.006 53.321 ;
     RECT  99.615 53.159 99.897 53.401 ;
     RECT  40.215 53.257 41.634 53.405 ;
     RECT  97.38 53.249 98.55 53.405 ;
     RECT  41.436 53.405 41.634 53.429 ;
     RECT  97.524 53.405 98.55 53.555 ;
     RECT  99.432 53.401 99.897 53.555 ;
     RECT  40.215 53.405 40.59 53.789 ;
     RECT  41.58 53.429 41.634 54.331 ;
     RECT  95.76 54.139 95.778 54.409 ;
     RECT  96.588 51.467 96.606 54.409 ;
     RECT  97.524 53.555 97.614 54.409 ;
     RECT  41.328 54.331 41.634 54.437 ;
     RECT  95.76 54.409 96.606 54.481 ;
     RECT  40.215 53.789 40.497 54.523 ;
     RECT  41.328 54.437 41.598 54.523 ;
     RECT  95.76 54.481 96.75 54.571 ;
     RECT  97.488 54.409 97.614 54.571 ;
     RECT  99.615 53.555 99.897 54.571 ;
     RECT  95.76 54.571 97.614 54.599 ;
     RECT  101.988 54.523 102.006 54.635 ;
     RECT  98.532 53.555 98.55 54.643 ;
     RECT  99.615 54.571 100.494 54.643 ;
     RECT  95.76 54.599 95.778 54.671 ;
     RECT  98.532 54.643 100.494 54.671 ;
     RECT  96.588 54.599 97.614 54.707 ;
     RECT  96.624 54.707 97.614 54.869 ;
     RECT  98.532 54.671 99.897 54.905 ;
     RECT  43.2 53.021 81 55.099 ;
     RECT  40.215 54.523 41.598 55.255 ;
     RECT  40.215 55.255 41.634 55.325 ;
     RECT  43.092 55.099 81 55.445 ;
     RECT  98.532 54.905 98.55 55.687 ;
     RECT  101.988 55.687 102.006 55.805 ;
     RECT  98.532 55.687 98.622 55.859 ;
     RECT  96.732 54.869 97.614 55.957 ;
     RECT  95.76 55.957 97.614 55.997 ;
     RECT  96.516 55.997 97.614 56.093 ;
     RECT  96.732 56.093 97.614 56.101 ;
     RECT  98.532 55.859 98.586 56.101 ;
     RECT  40.215 55.325 41.598 56.219 ;
     RECT  95.544 56.029 95.742 56.219 ;
     RECT  96.732 56.101 98.586 56.219 ;
     RECT  96.732 56.219 97.614 56.399 ;
     RECT  95.544 56.219 95.562 56.429 ;
     RECT  41.58 56.219 41.598 56.443 ;
     RECT  40.215 56.219 40.497 57.019 ;
     RECT  41.58 56.443 42.174 57.019 ;
     RECT  102.564 57.019 102.582 57.065 ;
     RECT  99.615 54.905 99.897 57.073 ;
     RECT  98.532 56.219 98.586 57.109 ;
     RECT  99.576 57.073 99.897 57.109 ;
     RECT  96.84 56.399 97.614 57.137 ;
     RECT  98.532 57.109 99.897 57.181 ;
     RECT  40.215 57.019 42.174 57.245 ;
     RECT  40.215 57.245 41.022 57.299 ;
     RECT  97.02 57.137 97.614 57.299 ;
     RECT  98.532 57.181 100.566 57.307 ;
     RECT  98.352 57.307 100.566 57.335 ;
     RECT  98.352 57.335 100.314 57.407 ;
     RECT  98.352 57.407 99.897 57.581 ;
     RECT  43.2 55.445 81 57.787 ;
     RECT  42.12 57.245 42.174 57.979 ;
     RECT  38.988 57.919 39.006 58.145 ;
     RECT  41.58 57.979 42.174 58.145 ;
     RECT  41.616 58.145 42.174 58.459 ;
     RECT  43.092 57.787 81 58.459 ;
     RECT  98.352 57.581 98.55 58.487 ;
     RECT  97.128 57.299 97.614 58.495 ;
     RECT  101.628 58.315 101.646 58.523 ;
     RECT  99.615 57.581 99.897 58.531 ;
     RECT  41.616 58.459 81 58.589 ;
     RECT  97.128 58.495 98.262 58.649 ;
     RECT  99 58.531 99.897 58.685 ;
     RECT  42.156 58.589 81 59.567 ;
     RECT  40.215 57.299 40.497 59.611 ;
     RECT  95.76 59.275 95.778 59.611 ;
     RECT  95.76 59.611 95.958 59.729 ;
     RECT  97.128 58.649 97.614 59.737 ;
     RECT  40.215 59.611 41.058 59.741 ;
     RECT  102.492 59.563 102.51 59.801 ;
     RECT  95.76 59.729 95.778 59.843 ;
     RECT  42.732 59.567 81 59.933 ;
     RECT  96.588 59.737 97.614 60.035 ;
     RECT  98.604 59.809 98.622 60.349 ;
     RECT  97.056 60.035 97.614 60.377 ;
     RECT  83.415 50.717 83.697 60.385 ;
     RECT  99.615 58.685 99.897 60.385 ;
     RECT  41.58 60.091 41.598 60.475 ;
     RECT  41.58 60.475 42.174 60.575 ;
     RECT  43.092 59.933 81 60.667 ;
     RECT  83.415 60.385 84.366 60.667 ;
     RECT  97.092 60.377 97.614 60.691 ;
     RECT  98.604 60.349 98.694 60.691 ;
     RECT  97.092 60.691 98.694 60.809 ;
     RECT  94.215 51.089 94.497 60.817 ;
     RECT  95.328 60.691 95.346 60.817 ;
     RECT  102.564 60.808 102.582 60.845 ;
     RECT  94.215 60.817 95.922 60.853 ;
     RECT  40.215 59.741 40.497 60.859 ;
     RECT  41.58 60.575 41.634 60.859 ;
     RECT  94.215 60.853 96.138 60.893 ;
     RECT  99.615 60.385 100.314 60.961 ;
     RECT  97.128 60.809 98.694 61.079 ;
     RECT  40.215 60.859 41.634 61.085 ;
     RECT  95.904 60.893 95.922 61.115 ;
     RECT  99.615 60.961 100.494 61.115 ;
     RECT  43.056 60.667 81 61.147 ;
     RECT  83.232 60.667 84.366 61.181 ;
     RECT  43.056 61.147 81.09 61.243 ;
     RECT  42.732 61.243 81.09 61.277 ;
     RECT  10.044 42.427 10.062 61.349 ;
     RECT  42.732 61.277 81 61.429 ;
     RECT  42.156 61.429 81 61.469 ;
     RECT  9.9 61.465 9.918 61.619 ;
     RECT  42.732 61.469 81 61.655 ;
     RECT  83.232 61.181 83.934 61.661 ;
     RECT  0.108 61.627 0.126 61.664 ;
     RECT  9.036 44.339 9.054 61.727 ;
     RECT  83.232 61.661 83.697 61.735 ;
     RECT  7.815 44.609 8.097 61.771 ;
     RECT  8.928 61.735 8.946 61.771 ;
     RECT  83.196 61.735 83.697 61.819 ;
     RECT  7.815 61.771 8.946 61.889 ;
     RECT  40.215 61.085 41.022 61.889 ;
     RECT  5.76 61.771 5.778 61.925 ;
     RECT  99.615 61.115 100.314 62.159 ;
     RECT  43.092 61.655 81 62.195 ;
     RECT  102.564 62.059 102.582 62.195 ;
     RECT  98.676 61.079 98.694 62.275 ;
     RECT  99.615 62.159 99.897 62.275 ;
     RECT  100.764 62.311 100.782 62.465 ;
     RECT  42.156 62.203 42.174 62.587 ;
     RECT  98.676 62.275 99.897 62.683 ;
     RECT  97.128 61.079 97.614 62.731 ;
     RECT  42.156 62.587 42.21 62.779 ;
     RECT  41.58 62.779 42.21 62.816 ;
     RECT  42.192 62.816 42.21 62.879 ;
     RECT  96.912 62.731 97.614 62.969 ;
     RECT  40.215 61.889 40.626 62.971 ;
     RECT  82.656 61.819 83.697 63.005 ;
     RECT  40.215 62.971 41.058 63.121 ;
     RECT  43.2 62.195 81 63.163 ;
     RECT  83.232 63.005 83.697 63.211 ;
     RECT  39.636 63.121 41.058 63.275 ;
     RECT  40.215 63.275 41.058 63.389 ;
     RECT  102.024 63.247 102.042 63.389 ;
     RECT  43.092 63.163 81 63.509 ;
     RECT  100.836 63.391 100.854 63.509 ;
     RECT  97.056 62.969 97.614 63.517 ;
     RECT  98.568 62.683 99.897 63.517 ;
     RECT  97.056 63.517 99.897 63.545 ;
     RECT  43.2 63.509 81 63.595 ;
     RECT  83.232 63.211 84.366 63.595 ;
     RECT  42.156 63.547 42.174 63.661 ;
     RECT  43.2 63.595 81.09 63.773 ;
     RECT  97.128 63.545 99.897 63.779 ;
     RECT  42.156 63.661 42.21 63.815 ;
     RECT  97.128 63.779 98.874 63.815 ;
     RECT  40.215 63.389 41.022 64.049 ;
     RECT  83.232 63.595 84.654 64.085 ;
     RECT  42.192 63.815 42.21 64.157 ;
     RECT  43.2 63.773 81 64.315 ;
     RECT  83.232 64.085 84.15 64.319 ;
     RECT  97.128 63.815 97.614 64.597 ;
     RECT  101.988 64.597 102.006 64.637 ;
     RECT  95.76 64.669 95.778 64.733 ;
     RECT  96.516 64.597 97.614 64.741 ;
     RECT  99.615 63.779 99.897 64.741 ;
     RECT  41.4 64.507 41.418 64.891 ;
     RECT  95.94 64.741 97.614 64.895 ;
     RECT  99.615 64.741 100.062 64.895 ;
     RECT  95.94 64.895 95.958 64.967 ;
     RECT  43.092 64.315 81 64.987 ;
     RECT  83.232 64.319 84.006 65.021 ;
     RECT  43.092 64.987 81.09 65.117 ;
     RECT  43.092 65.117 81 65.129 ;
     RECT  41.4 64.891 41.634 65.273 ;
     RECT  40.215 64.049 40.497 65.275 ;
     RECT  41.4 65.273 41.598 65.275 ;
     RECT  83.232 65.021 83.697 65.275 ;
     RECT  82.692 65.275 83.697 65.467 ;
     RECT  40.215 65.275 41.598 65.705 ;
     RECT  40.215 65.705 41.022 65.975 ;
     RECT  102.564 65.851 102.582 65.975 ;
     RECT  97.056 64.895 97.614 66.181 ;
     RECT  98.568 65.947 98.622 66.181 ;
     RECT  97.056 66.181 98.622 66.209 ;
     RECT  82.656 65.467 83.697 66.245 ;
     RECT  96.264 66.091 96.282 66.245 ;
     RECT  97.056 66.209 97.146 66.253 ;
     RECT  83.196 66.245 83.697 66.317 ;
     RECT  96.516 66.253 97.146 66.317 ;
     RECT  97.992 66.209 98.622 66.325 ;
     RECT  97.056 66.317 97.146 66.353 ;
     RECT  97.992 66.325 98.694 66.361 ;
     RECT  99.615 64.895 99.897 66.361 ;
     RECT  95.544 66.289 95.742 66.365 ;
     RECT  95.724 66.365 95.742 66.479 ;
     RECT  97.992 66.361 99.897 66.479 ;
     RECT  43.2 65.129 81 66.984 ;
     RECT  102.564 67.099 102.582 67.325 ;
     RECT  98.676 66.479 99.897 67.441 ;
     RECT  98.676 67.441 100.566 67.595 ;
     RECT  98.676 67.595 100.314 67.667 ;
     RECT  97.128 66.353 97.146 67.819 ;
     RECT  97.128 67.819 97.398 68.251 ;
     RECT  97.128 68.251 97.578 68.369 ;
     RECT  98.676 67.667 99.897 68.369 ;
     RECT  97.128 68.369 97.398 68.405 ;
     RECT  102.6 68.377 102.618 68.429 ;
     RECT  99.18 68.369 99.897 68.639 ;
     RECT  98.136 68.377 98.298 68.675 ;
     RECT  96.3 68.377 96.318 68.755 ;
     RECT  97.128 68.405 97.146 68.755 ;
     RECT  99.216 68.639 99.897 68.783 ;
     RECT  96.3 68.755 97.146 68.791 ;
     RECT  2.415 30.179 2.697 68.867 ;
     RECT  7.815 61.889 8.097 68.867 ;
     RECT  13.215 42.089 13.497 68.867 ;
     RECT  18.615 46.253 18.897 68.867 ;
     RECT  24.015 46.409 24.297 68.867 ;
     RECT  29.415 43.061 29.697 68.867 ;
     RECT  34.815 48.569 35.097 68.867 ;
     RECT  40.215 65.975 40.497 68.867 ;
     RECT  83.415 66.317 83.697 68.867 ;
     RECT  88.815 47.309 89.097 68.867 ;
     RECT  94.215 60.893 94.497 68.867 ;
     RECT  99.615 68.783 99.897 68.867 ;
     RECT  95.94 68.791 97.146 68.875 ;
     RECT  95.796 68.875 97.146 68.909 ;
     RECT  98.28 68.675 98.298 68.909 ;
     RECT  95.796 68.909 95.814 68.915 ;
     RECT  96.552 68.909 96.642 68.945 ;
     RECT  96.552 68.945 96.57 68.981 ;
     RECT  2.415 68.867 2.505 69.137 ;
     RECT  7.815 68.867 7.905 69.137 ;
     RECT  13.215 68.867 13.305 69.137 ;
     RECT  18.615 68.867 18.705 69.137 ;
     RECT  24.015 68.867 24.105 69.137 ;
     RECT  29.415 68.867 29.505 69.137 ;
     RECT  34.815 68.867 34.905 69.137 ;
     RECT  40.215 68.867 40.305 69.137 ;
     RECT  83.415 68.867 83.505 69.137 ;
     RECT  88.815 68.867 88.905 69.137 ;
     RECT  94.215 68.867 94.305 69.137 ;
     RECT  99.615 68.867 99.705 69.137 ;
     RECT  100.8 68.917 100.818 69.677 ;
    LAYER M4 ;
     RECT  2.365 5.184 2.408 5.208 ;
     RECT  2.365 11.664 2.408 11.688 ;
     RECT  2.365 13.68 2.408 13.704 ;
     RECT  2.365 15.984 2.408 16.008 ;
     RECT  2.329 29.04 2.408 29.064 ;
     RECT  2.408 2.148 2.512 69.132 ;
     RECT  2.401 0.576 2.653 0.6 ;
     RECT  2.512 2.418 2.704 68.862 ;
     RECT  2.704 10.32 2.819 13.704 ;
     RECT  2.653 0.576 2.873 0.648 ;
     RECT  2.873 0.576 2.981 0.6 ;
     RECT  2.704 2.736 3.169 2.76 ;
     RECT  2.704 21.216 3.539 25.56 ;
     RECT  3.539 24.48 3.629 25.56 ;
     RECT  2.704 29.04 3.665 29.064 ;
     RECT  2.704 15.984 3.697 16.008 ;
     RECT  3.697 15.36 3.737 16.008 ;
     RECT  2.704 6.288 3.773 9.24 ;
     RECT  2.704 4.56 3.777 5.256 ;
     RECT  3.773 6.288 3.777 6.312 ;
     RECT  3.539 21.216 3.781 22.776 ;
     RECT  2.704 26.736 3.845 27.912 ;
     RECT  3.697 19.584 3.913 19.608 ;
     RECT  3.781 20.976 3.913 22.776 ;
     RECT  3.777 4.56 4.021 6.312 ;
     RECT  2.819 12.096 4.061 12.984 ;
     RECT  3.913 19.584 4.061 22.776 ;
     RECT  2.704 30.144 4.061 30.168 ;
     RECT  4.061 12.24 4.097 12.984 ;
     RECT  4.021 29.088 4.129 29.112 ;
     RECT  3.949 3.408 4.229 3.432 ;
     RECT  4.061 19.584 4.241 21.24 ;
     RECT  3.773 7.344 4.261 9.24 ;
     RECT  2.819 10.32 4.261 10.68 ;
     RECT  4.229 3.36 4.313 3.432 ;
     RECT  4.313 3.408 4.345 3.432 ;
     RECT  4.021 4.512 4.345 6.312 ;
     RECT  3.737 15.36 4.345 15.384 ;
     RECT  4.241 19.584 4.453 20.328 ;
     RECT  4.453 18.816 4.529 20.328 ;
     RECT  4.093 32.544 4.561 32.568 ;
     RECT  4.097 12.336 4.597 12.984 ;
     RECT  3.845 26.928 4.637 27.768 ;
     RECT  3.629 25.44 4.709 25.56 ;
     RECT  4.345 14.832 4.777 15.384 ;
     RECT  4.709 25.536 4.885 25.56 ;
     RECT  4.813 26.736 4.885 26.76 ;
     RECT  4.561 32.448 4.933 32.568 ;
     RECT  4.933 32.448 5.02 33.24 ;
     RECT  4.061 22.224 5.065 22.776 ;
     RECT  4.129 29.088 5.105 29.16 ;
     RECT  4.345 3.408 5.132 6.312 ;
     RECT  4.261 7.344 5.132 10.68 ;
     RECT  4.597 12.336 5.213 13.032 ;
     RECT  4.529 20.304 5.425 20.328 ;
     RECT  5.065 21.984 5.461 22.776 ;
     RECT  5.132 3.408 5.465 10.68 ;
     RECT  5.425 20.304 5.465 20.52 ;
     RECT  5.465 3.408 5.533 10.296 ;
     RECT  3.913 17.04 5.533 17.064 ;
     RECT  4.529 18.816 5.573 19.272 ;
     RECT  4.237 31.296 5.609 31.32 ;
     RECT  4.777 14.832 5.681 15.864 ;
     RECT  4.885 25.536 5.713 26.76 ;
     RECT  4.637 27.744 5.713 27.768 ;
     RECT  5.573 19.248 5.789 19.272 ;
     RECT  5.713 25.536 5.893 27.768 ;
     RECT  5.893 24.624 6.133 27.768 ;
     RECT  5.461 21.984 6.143 22.968 ;
     RECT  5.02 32.448 6.145 32.472 ;
     RECT  5.497 29.568 6.253 30.072 ;
     RECT  5.533 3.312 6.257 10.296 ;
     RECT  5.533 17.04 6.257 17.64 ;
     RECT  6.133 24.624 6.289 27.912 ;
     RECT  5.213 12.336 6.361 12.36 ;
     RECT  5.461 13.44 6.361 13.56 ;
     RECT  6.428 36.144 6.515 36.168 ;
     RECT  6.428 44.448 6.515 44.472 ;
     RECT  5.465 20.496 6.541 20.52 ;
     RECT  6.253 29.568 6.613 30.744 ;
     RECT  6.257 3.312 6.689 3.672 ;
     RECT  6.361 12.336 6.696 13.56 ;
     RECT  6.145 32.448 6.757 33.144 ;
     RECT  5.681 15.216 6.853 15.864 ;
     RECT  6.613 29.568 6.853 30.792 ;
     RECT  6.257 4.944 6.865 10.296 ;
     RECT  6.289 24.624 6.865 28.488 ;
     RECT  6.541 19.344 6.973 20.52 ;
     RECT  6.143 21.984 6.973 23.16 ;
     RECT  6.973 19.344 7.081 23.16 ;
     RECT  7.081 19.296 7.297 23.16 ;
     RECT  6.865 24.624 7.297 28.584 ;
     RECT  6.853 15.216 7.333 16.392 ;
     RECT  6.853 29.568 7.381 30.84 ;
     RECT  6.757 32.448 7.381 33.624 ;
     RECT  6.037 34.8 7.549 34.824 ;
     RECT  6.696 12.096 7.657 13.56 ;
     RECT  7.381 29.568 7.657 33.624 ;
     RECT  7.549 34.8 7.657 35.016 ;
     RECT  7.333 14.736 7.693 16.392 ;
     RECT  6.257 17.616 7.693 17.64 ;
     RECT  6.689 3.408 7.729 3.672 ;
     RECT  6.865 4.944 7.729 10.776 ;
     RECT  7.729 3.408 7.808 10.776 ;
     RECT  7.657 12 7.808 13.56 ;
     RECT  7.693 14.736 7.808 17.688 ;
     RECT  7.297 19.296 7.808 28.584 ;
     RECT  7.657 29.568 7.808 35.016 ;
     RECT  6.793 36.624 7.808 36.792 ;
     RECT  6.469 42.048 7.808 42.072 ;
     RECT  6.469 61.68 7.808 61.704 ;
     RECT  7.808 2.148 7.912 69.132 ;
     RECT  7.912 2.418 8.104 68.862 ;
     RECT  8.104 14.736 8.165 20.376 ;
     RECT  8.165 16.368 8.201 20.376 ;
     RECT  8.201 16.512 8.345 19.944 ;
     RECT  8.104 30.048 8.345 32.52 ;
     RECT  8.104 27.792 8.453 28.152 ;
     RECT  8.165 14.736 8.525 14.76 ;
     RECT  8.104 36.624 8.561 37.608 ;
     RECT  8.104 3.936 8.597 13.56 ;
     RECT  8.597 3.936 8.813 7.464 ;
     RECT  8.597 8.688 8.813 13.56 ;
     RECT  8.813 3.936 8.957 7.416 ;
     RECT  8.561 37.104 9.133 37.608 ;
     RECT  8.104 34.128 9.173 35.16 ;
     RECT  8.813 8.736 9.205 13.56 ;
     RECT  8.104 21.792 9.565 26.376 ;
     RECT  9.205 8.736 9.601 14.184 ;
     RECT  9.565 21.792 9.601 26.76 ;
     RECT  8.453 27.888 9.601 28.152 ;
     RECT  9.601 21.792 9.709 28.152 ;
     RECT  8.345 30.048 9.709 32.328 ;
     RECT  9.709 21.792 9.733 29.016 ;
     RECT  8.345 17.952 9.788 19.944 ;
     RECT  9.733 21.408 9.788 29.016 ;
     RECT  9.788 17.952 9.877 29.016 ;
     RECT  9.709 30.048 9.877 32.616 ;
     RECT  9.601 8.736 9.961 14.952 ;
     RECT  9.173 34.128 9.997 34.152 ;
     RECT  8.104 42.048 10.033 42.072 ;
     RECT  9.269 1.728 10.069 1.752 ;
     RECT  10.069 1.152 10.105 1.752 ;
     RECT  8.345 16.512 10.105 16.92 ;
     RECT  9.877 17.952 10.105 32.616 ;
     RECT  10.105 16.512 10.109 32.616 ;
     RECT  10.109 20.928 10.177 32.616 ;
     RECT  9.997 33.6 10.177 34.152 ;
     RECT  10.105 0.576 10.325 1.752 ;
     RECT  10.325 0.576 10.355 0.6 ;
     RECT  9.173 35.136 10.393 35.16 ;
     RECT  10.177 20.928 10.429 34.152 ;
     RECT  10.393 35.136 10.429 35.544 ;
     RECT  10.109 16.512 10.433 19.944 ;
     RECT  8.957 4.176 10.645 7.416 ;
     RECT  9.961 8.736 10.645 15.384 ;
     RECT  10.429 20.928 10.681 35.544 ;
     RECT  9.133 37.104 10.681 37.704 ;
     RECT  10.645 4.176 10.717 15.384 ;
     RECT  10.681 20.928 10.829 37.704 ;
     RECT  10.717 3.888 10.837 15.384 ;
     RECT  10.433 16.512 10.837 16.92 ;
     RECT  10.829 20.928 10.865 34.344 ;
     RECT  10.865 20.928 10.901 33.288 ;
     RECT  10.901 27.84 11.009 33.288 ;
     RECT  10.829 35.424 11.009 37.704 ;
     RECT  11.009 30.192 11.045 33.288 ;
     RECT  10.837 3.888 11.077 16.92 ;
     RECT  10.433 17.952 11.189 19.944 ;
     RECT  11.189 18.48 11.221 19.944 ;
     RECT  10.901 20.928 11.221 26.808 ;
     RECT  11.077 3.408 11.411 16.92 ;
     RECT  11.045 30.672 11.411 33.288 ;
     RECT  11.411 3.408 11.441 14.424 ;
     RECT  11.221 18.48 11.441 26.808 ;
     RECT  11.009 35.52 11.473 37.704 ;
     RECT  10.865 34.32 11.548 34.344 ;
     RECT  11.473 35.52 11.653 38.04 ;
     RECT  11.441 3.408 11.657 13.224 ;
     RECT  11.657 3.408 11.725 10.92 ;
     RECT  11.411 15.984 11.729 16.92 ;
     RECT  11.657 12 11.747 13.224 ;
     RECT  11.009 27.84 12.013 29.016 ;
     RECT  12.013 27.84 12.085 29.688 ;
     RECT  11.411 30.672 12.085 33.048 ;
     RECT  12.085 27.84 12.188 33.048 ;
     RECT  11.653 35.52 12.193 38.184 ;
     RECT  12.193 35.328 12.229 38.184 ;
     RECT  12.229 34.944 12.265 38.184 ;
     RECT  11.941 0.576 12.371 0.6 ;
     RECT  11.441 18.48 12.373 25.56 ;
     RECT  12.373 18.192 12.445 25.56 ;
     RECT  12.188 27.792 12.517 33.048 ;
     RECT  12.517 27.792 12.553 33.624 ;
     RECT  12.265 34.944 12.553 38.664 ;
     RECT  11.725 2.88 12.805 10.92 ;
     RECT  11.441 14.4 12.877 14.424 ;
     RECT  12.445 17.952 13.045 25.56 ;
     RECT  11.441 26.736 13.045 26.808 ;
     RECT  11.747 12.336 13.093 13.224 ;
     RECT  11.729 16.416 13.093 16.92 ;
     RECT  13.045 17.952 13.093 26.808 ;
     RECT  10.325 1.728 13.165 1.752 ;
     RECT  13.165 1.728 13.208 1.848 ;
     RECT  12.805 2.88 13.208 10.968 ;
     RECT  13.093 12.288 13.208 13.224 ;
     RECT  12.877 14.4 13.208 14.664 ;
     RECT  13.093 16.368 13.208 26.808 ;
     RECT  12.553 27.792 13.208 38.664 ;
     RECT  10.033 42.048 13.208 42.456 ;
     RECT  13.208 1.728 13.312 69.132 ;
     RECT  13.312 1.728 13.504 68.862 ;
     RECT  13.504 14.256 13.601 14.664 ;
     RECT  13.504 3.408 13.619 13.128 ;
     RECT  13.619 4.656 13.709 13.128 ;
     RECT  13.504 15.792 13.709 29.544 ;
     RECT  13.709 28.368 13.781 29.544 ;
     RECT  13.504 31.872 14.393 37.608 ;
     RECT  13.601 14.256 14.497 14.424 ;
     RECT  13.709 15.792 14.533 27.24 ;
     RECT  13.504 30.576 14.569 30.696 ;
     RECT  14.569 29.808 14.605 30.696 ;
     RECT  14.393 31.872 14.605 33.384 ;
     RECT  13.709 4.656 14.677 12.888 ;
     RECT  14.497 13.968 14.677 14.424 ;
     RECT  14.533 15.696 14.677 27.24 ;
     RECT  14.677 4.656 14.713 14.424 ;
     RECT  14.677 15.696 14.713 27.336 ;
     RECT  13.619 3.408 14.821 3.48 ;
     RECT  13.781 28.368 14.893 28.824 ;
     RECT  14.605 29.808 14.893 33.384 ;
     RECT  14.749 0.096 14.963 0.12 ;
     RECT  14.713 4.656 15.109 27.336 ;
     RECT  15.109 4.608 15.253 27.336 ;
     RECT  14.893 28.368 15.253 33.384 ;
     RECT  15.253 4.608 15.325 33.384 ;
     RECT  15.325 4.512 15.401 33.384 ;
     RECT  14.821 3.264 15.433 3.48 ;
     RECT  14.393 34.464 15.469 37.608 ;
     RECT  15.433 3.216 15.473 3.48 ;
     RECT  15.401 4.512 15.617 13.08 ;
     RECT  15.473 3.216 15.685 3.432 ;
     RECT  15.401 14.16 15.793 33.384 ;
     RECT  15.469 34.464 15.793 37.704 ;
     RECT  15.685 2.88 15.941 3.432 ;
     RECT  15.941 2.928 15.971 3.432 ;
     RECT  15.793 14.16 16.364 37.704 ;
     RECT  14.929 38.688 16.364 38.712 ;
     RECT  15.617 4.608 16.369 13.08 ;
     RECT  16.364 14.16 16.369 38.712 ;
     RECT  15.971 3.264 16.661 3.432 ;
     RECT  16.369 4.608 16.873 38.712 ;
     RECT  13.504 1.728 17.021 1.752 ;
     RECT  16.873 3.936 17.129 38.712 ;
     RECT  17.129 21.984 17.221 38.712 ;
     RECT  17.221 21.984 17.273 38.904 ;
     RECT  17.273 21.984 17.309 33.576 ;
     RECT  17.273 34.608 17.309 38.904 ;
     RECT  17.221 2.88 17.345 2.904 ;
     RECT  17.309 34.656 17.345 38.904 ;
     RECT  17.345 34.656 17.453 38.808 ;
     RECT  17.129 3.936 17.809 20.952 ;
     RECT  17.809 3.36 18.565 20.952 ;
     RECT  17.309 22.272 18.565 33.576 ;
     RECT  18.565 3.36 18.608 33.576 ;
     RECT  17.453 34.944 18.608 38.808 ;
     RECT  13.504 42.048 18.608 42.456 ;
     RECT  18.529 46.224 18.608 46.248 ;
     RECT  18.608 2.148 18.712 69.132 ;
     RECT  18.712 2.418 18.904 68.862 ;
     RECT  18.904 36.864 19.181 38.808 ;
     RECT  18.904 3.312 19.379 35.448 ;
     RECT  19.379 27.888 19.505 35.448 ;
     RECT  19.379 3.312 19.973 26.904 ;
     RECT  18.904 46.368 20.329 46.392 ;
     RECT  19.181 36.864 20.341 38.472 ;
     RECT  20.341 36.864 20.401 38.952 ;
     RECT  20.329 46.368 20.413 47.352 ;
     RECT  19.973 3.36 20.473 26.904 ;
     RECT  19.505 27.888 20.473 35.304 ;
     RECT  20.473 3.36 20.541 35.304 ;
     RECT  20.541 31.344 20.572 35.304 ;
     RECT  20.572 31.872 20.801 35.304 ;
     RECT  20.401 36.624 20.873 38.952 ;
     RECT  20.873 36.624 20.977 37.656 ;
     RECT  20.413 46.368 21.193 46.392 ;
     RECT  20.541 3.36 21.685 29.928 ;
     RECT  20.801 31.872 21.731 35.064 ;
     RECT  21.685 3.36 21.805 30.312 ;
     RECT  21.731 32.208 22.165 35.064 ;
     RECT  20.977 36.432 22.165 37.656 ;
     RECT  21.805 3.36 22.277 31.176 ;
     RECT  22.165 32.208 22.925 37.656 ;
     RECT  22.277 6.672 23.065 31.176 ;
     RECT  22.277 3.36 23.317 5.544 ;
     RECT  23.065 6.672 23.317 31.224 ;
     RECT  22.925 32.544 23.677 37.656 ;
     RECT  20.873 38.928 23.677 38.952 ;
     RECT  23.317 3.36 24.008 31.224 ;
     RECT  23.677 32.544 24.008 38.952 ;
     RECT  18.904 42.048 24.008 42.456 ;
     RECT  21.193 45.84 24.008 46.392 ;
     RECT  24.008 2.148 24.112 69.132 ;
     RECT  24.112 2.418 24.304 68.862 ;
     RECT  24.304 34.32 24.365 39 ;
     RECT  24.365 34.32 24.401 37.608 ;
     RECT  24.304 2.88 25.085 30.216 ;
     RECT  24.401 34.32 25.513 37.56 ;
     RECT  24.365 38.784 25.513 39 ;
     RECT  25.085 3.36 25.585 30.216 ;
     RECT  25.585 3.36 25.621 30.408 ;
     RECT  24.304 31.536 25.621 33.288 ;
     RECT  25.621 3.36 25.801 33.288 ;
     RECT  25.513 34.32 25.801 39 ;
     RECT  25.801 3.36 26.197 39 ;
     RECT  26.197 2.832 26.237 39 ;
     RECT  26.237 2.832 26.281 33.672 ;
     RECT  26.237 34.704 26.309 39 ;
     RECT  26.281 2.88 26.381 33.672 ;
     RECT  26.381 2.88 27.209 30.12 ;
     RECT  27.209 3.312 27.421 30.12 ;
     RECT  26.381 31.104 27.421 33.672 ;
     RECT  26.309 34.704 27.457 37.56 ;
     RECT  27.421 3.312 27.497 33.672 ;
     RECT  27.497 3.36 27.683 33.672 ;
     RECT  27.683 20.304 27.733 33.672 ;
     RECT  27.457 34.704 27.733 37.608 ;
     RECT  27.733 20.304 27.965 37.608 ;
     RECT  27.709 0.576 27.971 0.6 ;
     RECT  27.965 30.816 27.997 37.608 ;
     RECT  27.997 30.816 28.213 37.992 ;
     RECT  26.377 39.216 28.213 39.624 ;
     RECT  25.225 1.728 28.453 1.752 ;
     RECT  27.683 3.36 28.693 19.32 ;
     RECT  28.453 1.152 28.793 1.752 ;
     RECT  27.965 20.304 28.933 29.64 ;
     RECT  28.213 30.816 28.933 39.624 ;
     RECT  28.693 2.88 29.041 19.32 ;
     RECT  28.933 20.304 29.041 39.624 ;
     RECT  28.793 1.68 29.408 1.752 ;
     RECT  29.041 2.88 29.408 39.624 ;
     RECT  24.304 42.048 29.408 42.456 ;
     RECT  24.304 45.84 29.408 46.872 ;
     RECT  29.408 1.68 29.507 69.132 ;
     RECT  29.507 1.728 29.512 69.132 ;
     RECT  29.512 1.728 29.704 68.862 ;
     RECT  29.545 0.576 29.747 0.6 ;
     RECT  29.704 2.832 30.377 39.24 ;
     RECT  30.377 2.832 30.557 39.096 ;
     RECT  30.557 2.832 30.845 37.32 ;
     RECT  30.757 0.096 30.899 0.12 ;
     RECT  29.704 1.728 30.899 1.752 ;
     RECT  31.057 0.576 31.237 0.6 ;
     RECT  30.557 38.4 31.241 39.096 ;
     RECT  31.241 38.448 31.34 39.096 ;
     RECT  31.34 38.448 31.381 39.288 ;
     RECT  30.845 2.832 31.421 30.504 ;
     RECT  31.237 0.576 31.961 1.176 ;
     RECT  30.845 31.728 31.997 37.32 ;
     RECT  31.961 0.576 32.051 0.6 ;
     RECT  32.273 1.728 32.569 1.752 ;
     RECT  31.997 31.728 32.645 33.816 ;
     RECT  29.704 45.84 32.677 46.872 ;
     RECT  31.997 34.944 32.713 37.32 ;
     RECT  31.381 38.448 32.713 39.912 ;
     RECT  32.569 1.728 32.819 1.8 ;
     RECT  32.713 34.944 32.933 39.912 ;
     RECT  31.421 2.832 33.037 30.456 ;
     RECT  32.645 31.728 33.037 33.288 ;
     RECT  32.933 34.944 33.109 39.048 ;
     RECT  32.819 1.728 33.625 1.752 ;
     RECT  33.037 2.832 33.757 33.288 ;
     RECT  33.109 34.464 33.757 39.048 ;
     RECT  33.757 2.832 33.937 39.048 ;
     RECT  33.937 2.736 34.189 39.048 ;
     RECT  34.189 2.736 34.261 39.336 ;
     RECT  29.704 42.048 34.693 42.456 ;
     RECT  34.261 2.736 34.729 39.528 ;
     RECT  34.729 2.736 34.808 39.624 ;
     RECT  34.693 41.664 34.808 42.456 ;
     RECT  32.677 45.84 34.808 47.448 ;
     RECT  31.705 48.528 34.808 48.552 ;
     RECT  34.808 2.148 34.912 69.132 ;
     RECT  34.912 2.418 35.104 68.862 ;
     RECT  35.104 2.784 35.219 39.624 ;
     RECT  35.219 3.12 35.453 39.624 ;
     RECT  35.104 41.664 35.459 42.456 ;
     RECT  35.453 3.12 35.993 39.528 ;
     RECT  35.993 28.272 36.029 39.528 ;
     RECT  35.459 41.856 36.323 42.456 ;
     RECT  35.993 3.12 36.889 27.096 ;
     RECT  36.889 2.304 36.961 27.096 ;
     RECT  36.029 28.272 36.997 34.872 ;
     RECT  36.029 36 36.997 39.528 ;
     RECT  36.997 28.272 37.001 39.528 ;
     RECT  36.961 2.304 37.033 27.192 ;
     RECT  37.001 33.888 37.109 39.528 ;
     RECT  37.001 28.272 37.541 32.856 ;
     RECT  37.033 2.304 37.649 27.24 ;
     RECT  37.541 28.416 38.077 32.856 ;
     RECT  37.109 33.888 38.077 34.872 ;
     RECT  37.649 2.88 38.369 27.24 ;
     RECT  38.077 28.416 38.617 34.872 ;
     RECT  37.109 36 38.617 39.528 ;
     RECT  38.617 28.416 38.653 39.528 ;
     RECT  38.653 28.416 38.941 39.864 ;
     RECT  38.369 3.12 39.053 27.24 ;
     RECT  38.941 28.416 39.059 40.248 ;
     RECT  39.059 28.416 39.161 39.864 ;
     RECT  39.161 28.416 39.203 39.624 ;
     RECT  39.053 3.36 39.781 27.24 ;
     RECT  39.203 28.416 39.781 37.944 ;
     RECT  39.781 3.36 40.208 37.944 ;
     RECT  39.203 38.928 40.208 39.624 ;
     RECT  36.323 42.432 40.208 42.456 ;
     RECT  35.104 45.84 40.208 47.448 ;
     RECT  35.104 48.528 40.208 48.552 ;
     RECT  40.208 2.148 40.312 69.132 ;
     RECT  40.312 2.418 40.504 68.862 ;
     RECT  40.504 15.312 40.601 39.672 ;
     RECT  40.504 45.888 41.497 49.56 ;
     RECT  40.504 50.88 41.497 57.048 ;
     RECT  41.497 45.888 41.569 57.048 ;
     RECT  40.504 59.712 41.569 59.736 ;
     RECT  40.504 60.864 41.569 65.88 ;
     RECT  41.569 45.888 41.605 58.008 ;
     RECT  40.601 15.312 41.713 27.24 ;
     RECT  40.601 28.272 41.713 39.672 ;
     RECT  40.504 2.928 41.929 14.232 ;
     RECT  41.713 15.312 41.929 39.672 ;
     RECT  41.605 45.888 42.001 58.584 ;
     RECT  42.001 44.928 42.037 58.584 ;
     RECT  40.504 41.904 42.073 42.456 ;
     RECT  42.037 44.736 42.145 58.584 ;
     RECT  41.569 59.712 42.145 65.88 ;
     RECT  41.929 2.928 42.149 39.672 ;
     RECT  42.145 44.736 42.181 65.88 ;
     RECT  42.149 2.928 42.229 14.28 ;
     RECT  41.989 1.152 42.293 1.176 ;
     RECT  42.149 15.36 42.541 39.672 ;
     RECT  42.229 2.88 42.761 14.28 ;
     RECT  42.577 0.576 42.803 0.6 ;
     RECT  42.541 15.36 42.805 39.912 ;
     RECT  42.181 44.16 42.805 65.88 ;
     RECT  42.073 41.904 42.901 42.744 ;
     RECT  42.997 1.728 43.217 1.752 ;
     RECT  42.805 15.36 43.225 40.728 ;
     RECT  42.761 3.168 43.265 14.28 ;
     RECT  42.901 41.904 43.272 42.84 ;
     RECT  42.805 43.968 43.272 65.88 ;
     RECT  43.225 15.36 43.309 40.92 ;
     RECT  43.265 3.168 43.409 14.232 ;
     RECT  43.309 15.36 43.409 40.824 ;
     RECT  43.409 15.36 43.445 33.816 ;
     RECT  43.445 15.36 43.481 33.576 ;
     RECT  43.409 34.896 43.553 40.824 ;
     RECT  43.409 3.168 43.733 14.184 ;
     RECT  43.217 1.728 43.765 1.8 ;
     RECT  43.553 34.896 43.877 39.912 ;
     RECT  43.481 16.08 43.913 33.576 ;
     RECT  43.913 16.08 44.129 30.888 ;
     RECT  44.129 29.52 44.345 30.888 ;
     RECT  43.765 1.152 44.453 1.8 ;
     RECT  43.913 31.92 44.588 33.576 ;
     RECT  43.877 34.896 44.588 39.528 ;
     RECT  44.413 14.448 44.593 14.472 ;
     RECT  44.129 16.08 44.593 28.488 ;
     RECT  44.593 14.448 44.633 28.488 ;
     RECT  44.453 1.2 44.777 1.8 ;
     RECT  43.733 3.168 45.025 13.176 ;
     RECT  44.633 14.448 45.025 19.32 ;
     RECT  45.025 3.168 45.301 19.32 ;
     RECT  44.777 1.632 45.608 1.8 ;
     RECT  45.301 2.88 45.608 19.32 ;
     RECT  44.633 20.352 45.608 28.488 ;
     RECT  44.345 29.568 45.608 30.888 ;
     RECT  44.588 31.92 45.608 39.528 ;
     RECT  43.272 41.904 45.608 66.984 ;
     RECT  45.608 1.632 45.712 66.984 ;
     RECT  45.712 1.632 45.785 40.782 ;
     RECT  45.785 1.68 45.904 40.782 ;
     RECT  45.904 1.68 45.965 1.752 ;
     RECT  45.904 37.584 45.965 39.528 ;
     RECT  45.904 32.4 46.469 36.6 ;
     RECT  45.965 37.728 46.829 39.528 ;
     RECT  46.829 37.728 47.077 39.48 ;
     RECT  45.904 3.36 47.293 31.416 ;
     RECT  47.077 37.632 47.369 39.48 ;
     RECT  47.293 3.168 47.605 31.416 ;
     RECT  45.965 1.728 47.825 1.752 ;
     RECT  47.605 2.88 47.891 31.416 ;
     RECT  47.825 1.152 47.909 1.752 ;
     RECT  47.369 38.64 47.939 39.48 ;
     RECT  47.891 15.456 47.941 31.416 ;
     RECT  46.469 32.496 47.941 36.6 ;
     RECT  47.891 2.88 48.233 14.472 ;
     RECT  48.233 3.168 48.341 14.472 ;
     RECT  48.341 3.36 48.449 14.472 ;
     RECT  47.941 15.456 48.481 36.6 ;
     RECT  47.369 37.632 48.481 37.656 ;
     RECT  47.939 38.64 48.485 39.336 ;
     RECT  48.481 15.456 48.521 37.656 ;
     RECT  48.521 15.456 48.809 37.08 ;
     RECT  48.449 10.512 48.913 14.472 ;
     RECT  48.809 15.456 48.913 20.424 ;
     RECT  48.449 3.36 49.169 9.528 ;
     RECT  48.485 38.736 49.493 39.336 ;
     RECT  48.913 10.512 49.777 20.424 ;
     RECT  48.809 21.408 49.777 37.08 ;
     RECT  49.777 10.512 49.781 37.08 ;
     RECT  49.493 38.784 49.889 39.336 ;
     RECT  49.781 10.512 49.907 26.28 ;
     RECT  49.169 3.36 50.137 9.288 ;
     RECT  49.907 10.512 50.137 20.424 ;
     RECT  47.909 1.728 50.177 1.752 ;
     RECT  49.781 27.36 50.569 37.08 ;
     RECT  49.889 38.784 50.569 38.808 ;
     RECT  50.54 0.096 50.627 0.12 ;
     RECT  50.137 3.36 50.749 20.424 ;
     RECT  50.749 3.312 51.008 20.424 ;
     RECT  49.907 21.456 51.008 26.28 ;
     RECT  50.569 27.36 51.008 38.808 ;
     RECT  45.712 41.904 51.008 66.984 ;
     RECT  51.008 2.148 51.112 66.984 ;
     RECT  51.112 2.418 51.304 40.782 ;
     RECT  51.304 14.448 51.365 27.528 ;
     RECT  51.304 28.704 51.401 29.64 ;
     RECT  51.401 28.944 51.437 29.64 ;
     RECT  51.365 24.144 51.545 27.528 ;
     RECT  51.304 31.872 52.067 36.84 ;
     RECT  51.437 28.992 52.364 29.64 ;
     RECT  51.304 3.12 52.449 13.128 ;
     RECT  51.365 14.448 52.449 23.16 ;
     RECT  52.364 28.992 52.517 29.928 ;
     RECT  52.517 29.52 52.621 29.928 ;
     RECT  52.067 33.36 52.837 36.84 ;
     RECT  51.304 37.872 52.837 37.896 ;
     RECT  51.545 24.144 53.125 27.384 ;
     RECT  53.125 24.144 53.269 27.624 ;
     RECT  52.067 31.872 53.345 31.896 ;
     RECT  52.449 3.12 53.413 23.16 ;
     RECT  53.269 24.144 53.413 28.488 ;
     RECT  53.413 3.12 53.521 28.488 ;
     RECT  52.621 29.52 53.521 30.744 ;
     RECT  52.837 33.36 53.885 37.896 ;
     RECT  53.885 34.416 53.921 37.896 ;
     RECT  53.921 35.952 54.173 37.896 ;
     RECT  53.885 33.36 54.205 33.432 ;
     RECT  54.173 35.952 54.353 36.648 ;
     RECT  54.205 33.312 54.371 33.432 ;
     RECT  53.521 3.12 54.373 30.744 ;
     RECT  54.173 37.872 54.419 37.896 ;
     RECT  54.373 3.12 54.493 31.128 ;
     RECT  54.371 33.36 54.497 33.432 ;
     RECT  53.921 34.416 54.677 34.68 ;
     RECT  54.493 2.88 54.713 31.128 ;
     RECT  54.713 22.224 54.749 31.128 ;
     RECT  54.497 33.408 54.749 33.432 ;
     RECT  54.749 22.224 54.821 28.056 ;
     RECT  54.821 28.032 54.857 28.056 ;
     RECT  54.353 35.952 55.181 35.976 ;
     RECT  54.713 2.88 55.325 21.144 ;
     RECT  54.749 29.568 55.717 31.128 ;
     RECT  55.325 18.816 55.753 21.144 ;
     RECT  54.821 22.224 55.753 26.808 ;
     RECT  54.925 34.128 55.753 34.152 ;
     RECT  55.753 18.816 55.861 26.808 ;
     RECT  55.717 29.52 56.077 31.128 ;
     RECT  54.097 32.256 56.365 32.28 ;
     RECT  55.753 33.36 56.365 34.152 ;
     RECT  55.325 2.88 56.408 17.64 ;
     RECT  55.861 18.816 56.408 27.384 ;
     RECT  56.077 28.8 56.408 31.128 ;
     RECT  56.365 32.256 56.408 34.152 ;
     RECT  55.295 35.184 56.408 35.208 ;
     RECT  56.329 36.24 56.408 36.264 ;
     RECT  51.112 41.904 56.408 66.984 ;
     RECT  56.408 2.148 56.512 66.984 ;
     RECT  56.512 2.418 56.704 40.782 ;
     RECT  56.704 3.12 56.765 23.16 ;
     RECT  56.704 27.936 57.089 34.824 ;
     RECT  57.089 27.936 57.161 33.672 ;
     RECT  57.161 28.992 57.197 33.672 ;
     RECT  57.197 28.992 57.233 32.616 ;
     RECT  57.089 34.8 57.673 34.824 ;
     RECT  56.765 3.312 57.877 23.16 ;
     RECT  57.233 32.544 57.989 32.616 ;
     RECT  57.197 33.648 58.061 33.672 ;
     RECT  57.877 3.216 58.093 23.16 ;
     RECT  56.704 24.432 58.093 26.28 ;
     RECT  58.093 3.216 58.301 26.28 ;
     RECT  58.301 2.88 58.385 26.28 ;
     RECT  58.385 3.216 58.417 26.28 ;
     RECT  57.161 27.936 58.597 27.96 ;
     RECT  57.233 28.992 58.597 31.176 ;
     RECT  58.417 3.216 58.741 26.616 ;
     RECT  58.597 27.936 58.745 31.176 ;
     RECT  58.741 3.216 58.835 26.904 ;
     RECT  58.835 3.216 58.889 21.528 ;
     RECT  58.835 22.512 58.993 26.904 ;
     RECT  58.745 27.936 58.993 29.592 ;
     RECT  57.989 32.592 59.069 32.616 ;
     RECT  59.209 34.224 59.321 34.248 ;
     RECT  59.317 33.216 59.425 33.24 ;
     RECT  56.704 36.24 59.461 36.264 ;
     RECT  58.889 3.216 59.497 10.728 ;
     RECT  59.425 33.216 59.565 33.864 ;
     RECT  59.497 2.88 59.651 10.728 ;
     RECT  58.745 30.576 59.677 31.176 ;
     RECT  58.993 22.512 59.756 29.592 ;
     RECT  59.677 30.576 59.756 31.416 ;
     RECT  58.889 11.76 59.861 21.528 ;
     RECT  59.651 3.216 59.893 10.728 ;
     RECT  59.861 11.76 59.893 13.416 ;
     RECT  59.756 22.512 60.077 31.416 ;
     RECT  60.077 30.816 60.217 31.416 ;
     RECT  59.461 35.904 60.257 36.264 ;
     RECT  59.861 14.4 60.289 21.528 ;
     RECT  60.077 22.512 60.289 29.736 ;
     RECT  59.893 3.216 60.581 13.416 ;
     RECT  58.597 1.728 60.721 1.752 ;
     RECT  60.581 3.312 61.045 13.416 ;
     RECT  60.289 14.4 61.045 29.736 ;
     RECT  59.565 33.84 61.081 33.864 ;
     RECT  60.217 30.816 61.261 31.464 ;
     RECT  61.045 3.312 61.369 29.736 ;
     RECT  61.261 30.816 61.441 31.512 ;
     RECT  61.441 30.816 61.549 32.04 ;
     RECT  61.081 33.024 61.549 33.864 ;
     RECT  60.721 1.728 61.669 1.8 ;
     RECT  61.669 1.152 61.693 1.8 ;
     RECT  61.693 0.576 61.808 1.8 ;
     RECT  61.369 3.312 61.808 29.784 ;
     RECT  61.549 30.816 61.808 33.864 ;
     RECT  60.257 36.24 61.808 36.264 ;
     RECT  56.512 41.904 61.808 66.984 ;
     RECT  61.808 0.576 61.912 66.984 ;
     RECT  61.912 0.576 62.104 40.782 ;
     RECT  62.104 0.576 62.195 1.752 ;
     RECT  62.104 2.736 62.345 33.576 ;
     RECT  62.195 0.576 62.677 0.6 ;
     RECT  62.677 0.096 62.819 0.6 ;
     RECT  62.819 0.576 63.205 0.6 ;
     RECT  62.195 1.728 63.205 1.752 ;
     RECT  62.345 3.36 63.313 33.576 ;
     RECT  63.313 3.36 63.457 33.816 ;
     RECT  63.205 0.576 63.491 1.752 ;
     RECT  63.457 2.88 63.889 33.816 ;
     RECT  63.491 1.152 63.893 1.752 ;
     RECT  63.889 2.832 64.181 33.816 ;
     RECT  64.181 2.832 65.441 33.576 ;
     RECT  63.893 1.728 65.509 1.752 ;
     RECT  65.509 1.152 65.729 1.752 ;
     RECT  65.441 3.648 65.905 33.576 ;
     RECT  65.729 1.728 66.485 1.752 ;
     RECT  65.905 3.648 67.208 33.912 ;
     RECT  62.104 36.24 67.208 36.264 ;
     RECT  61.912 41.904 67.208 66.984 ;
     RECT  67.208 2.148 67.312 66.984 ;
     RECT  67.312 2.418 67.504 40.782 ;
     RECT  67.504 3.552 68.573 33.672 ;
     RECT  68.573 3.552 68.963 33.624 ;
     RECT  68.963 26.256 69.113 33.624 ;
     RECT  68.963 3.552 69.325 25.128 ;
     RECT  69.325 3.12 69.925 25.128 ;
     RECT  69.925 3.12 70.009 25.224 ;
     RECT  70.009 3.024 70.081 25.224 ;
     RECT  69.113 26.304 70.081 33.624 ;
     RECT  70.081 3.024 70.405 33.624 ;
     RECT  70.405 3.024 70.477 34.104 ;
     RECT  70.477 2.832 70.589 34.104 ;
     RECT  70.589 2.88 71.057 34.104 ;
     RECT  71.057 21.504 71.453 34.104 ;
     RECT  71.453 31.92 71.633 34.104 ;
     RECT  71.057 2.88 72.349 20.52 ;
     RECT  71.453 21.504 72.349 30.936 ;
     RECT  72.349 2.88 72.608 30.936 ;
     RECT  71.633 31.92 72.608 33.672 ;
     RECT  67.504 36.24 72.608 36.264 ;
     RECT  67.312 41.904 72.608 66.984 ;
     RECT  72.608 2.148 72.712 66.984 ;
     RECT  72.712 2.418 72.904 40.782 ;
     RECT  72.904 2.88 73.001 34.344 ;
     RECT  74.401 0.528 74.437 0.552 ;
     RECT  73.001 3.648 74.531 34.344 ;
     RECT  74.531 3.648 74.585 34.248 ;
     RECT  74.437 0.096 74.653 0.552 ;
     RECT  74.653 0.096 74.723 1.128 ;
     RECT  74.723 0.528 75.251 1.128 ;
     RECT  74.585 3.648 76.021 34.104 ;
     RECT  75.445 1.152 76.097 1.752 ;
     RECT  76.021 3.264 76.133 34.104 ;
     RECT  76.133 3.264 76.213 33.96 ;
     RECT  76.213 2.88 76.853 33.96 ;
     RECT  76.853 2.976 76.997 33.96 ;
     RECT  76.097 1.2 77.065 1.752 ;
     RECT  77.065 1.152 77.965 1.752 ;
     RECT  77.965 1.104 78.008 1.752 ;
     RECT  76.997 3.264 78.008 33.96 ;
     RECT  72.904 36.24 78.008 36.264 ;
     RECT  72.712 41.904 78.008 66.984 ;
     RECT  78.008 1.104 78.112 66.984 ;
     RECT  78.112 1.104 78.304 40.782 ;
     RECT  78.304 1.104 78.323 1.752 ;
     RECT  78.323 1.2 78.419 1.752 ;
     RECT  78.304 3.408 78.977 33.624 ;
     RECT  78.419 1.728 79.333 1.752 ;
     RECT  79.333 1.728 79.571 1.8 ;
     RECT  78.977 26.688 79.729 33.624 ;
     RECT  79.729 26.688 79.945 33.672 ;
     RECT  78.977 3.408 80.017 25.512 ;
     RECT  79.945 26.592 80.017 33.672 ;
     RECT  80.017 3.408 80.021 33.672 ;
     RECT  79.571 1.728 80.197 1.752 ;
     RECT  80.021 3.408 80.773 33.624 ;
     RECT  80.197 1.152 80.867 1.752 ;
     RECT  78.112 41.904 80.928 66.984 ;
     RECT  80.773 2.88 80.957 33.624 ;
     RECT  80.928 43.968 81 65.88 ;
     RECT  81 43.968 81.299 51.288 ;
     RECT  80.957 3.408 81.893 33.624 ;
     RECT  81.889 0.576 82.115 0.6 ;
     RECT  80.867 1.728 82.469 1.752 ;
     RECT  82.597 1.152 82.793 1.176 ;
     RECT  81.893 3.648 83.408 33.624 ;
     RECT  78.304 36.24 83.408 36.264 ;
     RECT  80.928 41.904 83.408 42.456 ;
     RECT  81.299 43.968 83.408 51.096 ;
     RECT  81 60.672 83.408 65.88 ;
     RECT  83.408 2.148 83.512 69.132 ;
     RECT  83.512 2.418 83.704 68.862 ;
     RECT  83.704 60.864 83.801 61.656 ;
     RECT  83.704 3.264 83.945 33.624 ;
     RECT  83.801 61.152 83.945 61.656 ;
     RECT  83.704 63.36 83.945 65.016 ;
     RECT  83.945 64.992 84.017 65.016 ;
     RECT  83.704 46.56 84.233 50.952 ;
     RECT  83.945 61.152 84.377 61.176 ;
     RECT  83.945 63.36 84.377 63.624 ;
     RECT  83.704 41.904 84.563 42.312 ;
     RECT  84.233 47.952 84.629 50.952 ;
     RECT  84.563 41.904 84.659 41.928 ;
     RECT  84.233 46.56 84.665 46.584 ;
     RECT  84.377 63.6 84.665 63.624 ;
     RECT  84.629 48.96 84.917 50.952 ;
     RECT  84.629 47.952 85.201 47.976 ;
     RECT  83.945 3.264 85.237 33.384 ;
     RECT  85.237 3.264 85.324 33.816 ;
     RECT  84.917 48.96 85.385 50.904 ;
     RECT  85.201 47.904 85.637 47.976 ;
     RECT  85.324 3.264 86.101 33.336 ;
     RECT  86.101 2.928 86.105 33.336 ;
     RECT  85.385 49.056 86.141 50.904 ;
     RECT  83.704 36.24 86.293 36.264 ;
     RECT  86.105 18.768 86.393 33.336 ;
     RECT  86.393 18.816 86.465 33.336 ;
     RECT  86.105 2.928 86.497 17.784 ;
     RECT  86.465 19.008 86.537 33.336 ;
     RECT  86.141 49.056 86.645 50.616 ;
     RECT  86.293 35.952 87.109 36.264 ;
     RECT  87.109 35.904 87.193 36.264 ;
     RECT  86.645 49.056 87.221 50.376 ;
     RECT  86.537 19.872 87.257 33.336 ;
     RECT  85.637 47.904 87.293 47.928 ;
     RECT  87.257 20.112 87.329 33.336 ;
     RECT  87.221 50.352 87.329 50.376 ;
     RECT  87.221 49.056 87.365 49.368 ;
     RECT  87.365 49.056 87.437 49.08 ;
     RECT  86.497 2.784 87.793 17.784 ;
     RECT  87.793 2.784 88.153 18.456 ;
     RECT  87.329 21.984 88.213 33.336 ;
     RECT  87.329 20.112 88.369 20.376 ;
     RECT  88.153 2.784 88.808 18.552 ;
     RECT  88.369 20.112 88.808 20.712 ;
     RECT  88.213 21.984 88.808 33.768 ;
     RECT  87.193 35.952 88.808 36.264 ;
     RECT  88.808 2.148 88.912 69.132 ;
     RECT  88.912 2.418 89.104 68.862 ;
     RECT  89.104 3.648 90.101 20.712 ;
     RECT  89.104 21.888 90.173 33.336 ;
     RECT  90.173 21.888 90.497 29.304 ;
     RECT  90.497 21.888 90.529 24.744 ;
     RECT  90.529 21.744 90.565 24.744 ;
     RECT  90.101 3.648 90.673 20.136 ;
     RECT  86.785 0.048 90.949 0.072 ;
     RECT  90.949 0.048 90.995 0.168 ;
     RECT  90.497 25.824 91.141 29.304 ;
     RECT  90.173 30.576 91.141 33.336 ;
     RECT  90.673 3.408 91.145 20.136 ;
     RECT  91.141 25.824 91.217 29.448 ;
     RECT  91.217 25.824 91.253 25.848 ;
     RECT  91.145 3.408 91.285 17.496 ;
     RECT  91.145 18.816 91.433 20.136 ;
     RECT  90.565 21.6 91.465 24.744 ;
     RECT  91.141 30.576 91.724 33.48 ;
     RECT  89.104 35.952 91.765 36.264 ;
     RECT  91.724 30.576 91.811 34.008 ;
     RECT  91.765 35.952 91.811 36.456 ;
     RECT  90.995 0.096 91.813 0.168 ;
     RECT  91.525 1.152 91.813 1.176 ;
     RECT  91.217 26.832 91.825 29.448 ;
     RECT  91.811 30.576 91.825 33.144 ;
     RECT  91.285 2.976 92.041 17.496 ;
     RECT  91.811 36.24 92.051 36.456 ;
     RECT  92.041 2.928 92.153 17.496 ;
     RECT  91.813 0.096 92.405 1.176 ;
     RECT  92.153 2.976 92.509 17.496 ;
     RECT  91.433 19.104 92.509 20.136 ;
     RECT  91.825 26.832 92.509 33.144 ;
     RECT  92.509 26.304 92.657 33.144 ;
     RECT  92.509 2.976 92.801 20.136 ;
     RECT  92.801 18.816 92.905 20.136 ;
     RECT  91.465 21.216 93.049 24.744 ;
     RECT  92.801 2.976 93.053 17.496 ;
     RECT  93.053 2.976 93.197 8.52 ;
     RECT  93.049 21.216 93.265 25.032 ;
     RECT  92.657 26.304 93.265 31.128 ;
     RECT  92.905 18.816 93.337 20.184 ;
     RECT  93.265 21.216 93.337 31.128 ;
     RECT  92.405 0.096 93.548 0.12 ;
     RECT  92.405 1.152 93.548 1.176 ;
     RECT  93.548 0.096 93.881 1.176 ;
     RECT  93.337 18.816 94.031 31.128 ;
     RECT  92.657 32.304 94.031 33.144 ;
     RECT  93.197 3.12 94.208 8.52 ;
     RECT  93.053 9.504 94.208 17.496 ;
     RECT  94.031 18.816 94.208 33.144 ;
     RECT  92.051 36.24 94.208 36.264 ;
     RECT  94.201 40.848 94.208 40.872 ;
     RECT  92.005 47.136 94.208 47.16 ;
     RECT  94.208 2.148 94.312 69.132 ;
     RECT  94.312 2.418 94.504 68.862 ;
     RECT  94.504 47.136 94.601 47.304 ;
     RECT  94.504 30.576 94.691 34.248 ;
     RECT  94.504 18.768 94.931 18.84 ;
     RECT  93.881 0.096 95.027 0.6 ;
     RECT  94.691 30.576 95.033 33.048 ;
     RECT  94.504 2.736 95.105 17.352 ;
     RECT  95.027 0.528 95.125 0.6 ;
     RECT  94.504 35.328 95.177 36.264 ;
     RECT  95.105 3.312 95.321 17.352 ;
     RECT  95.125 0.528 95.365 1.176 ;
     RECT  94.931 18.816 95.429 18.84 ;
     RECT  95.033 30.576 95.465 32.568 ;
     RECT  95.321 9.072 95.569 17.352 ;
     RECT  94.504 20.112 95.653 29.352 ;
     RECT  95.465 30.576 95.717 32.088 ;
     RECT  94.504 40.848 95.741 40.872 ;
     RECT  95.533 56.4 95.749 56.424 ;
     RECT  94.691 34.224 95.789 34.248 ;
     RECT  95.569 9.072 95.795 17.448 ;
     RECT  95.708 49.536 95.795 49.56 ;
     RECT  94.504 51.072 95.795 51.096 ;
     RECT  95.749 55.968 95.795 56.424 ;
     RECT  95.756 68.88 95.797 68.904 ;
     RECT  95.741 39.888 95.825 40.872 ;
     RECT  94.504 45.6 95.825 45.624 ;
     RECT  95.749 58.464 95.833 59.832 ;
     RECT  95.749 64.704 95.843 64.728 ;
     RECT  95.533 66.336 95.843 66.36 ;
     RECT  95.717 30.96 95.933 32.088 ;
     RECT  95.653 19.968 96.037 29.352 ;
     RECT  96.037 19.872 96.077 29.352 ;
     RECT  96.077 22.176 96.145 29.352 ;
     RECT  95.749 54.144 96.277 54.168 ;
     RECT  95.795 55.968 96.293 55.992 ;
     RECT  96.277 53.376 96.323 54.168 ;
     RECT  95.785 44.544 96.325 44.568 ;
     RECT  96.145 22.176 96.365 29.688 ;
     RECT  95.795 9.072 96.437 9.096 ;
     RECT  96.365 22.176 96.437 26.184 ;
     RECT  95.797 68.4 96.517 68.904 ;
     RECT  96.476 66.288 96.563 66.312 ;
     RECT  96.517 68.4 96.604 68.952 ;
     RECT  96.365 27.312 96.617 29.688 ;
     RECT  96.077 19.872 96.689 21.192 ;
     RECT  95.365 0.528 96.707 1.224 ;
     RECT  95.797 63.264 96.709 63.288 ;
     RECT  96.709 62.736 96.757 63.288 ;
     RECT  96.284 46.032 96.803 46.056 ;
     RECT  95.833 59.808 96.803 59.832 ;
     RECT  94.504 60.864 96.803 60.888 ;
     RECT  96.517 64.656 96.803 64.68 ;
     RECT  96.617 29.328 96.833 29.688 ;
     RECT  96.707 0.528 96.893 0.552 ;
     RECT  95.933 30.96 96.893 31.176 ;
     RECT  95.177 36.24 96.901 36.264 ;
     RECT  95.321 3.312 96.905 7.656 ;
     RECT  96.689 19.872 96.941 20.424 ;
     RECT  96.757 62.736 96.941 63.576 ;
     RECT  96.833 29.328 96.947 29.352 ;
     RECT  96.901 36.24 96.947 37.032 ;
     RECT  94.601 47.28 96.949 47.304 ;
     RECT  95.795 10.176 96.973 17.448 ;
     RECT  96.893 0.096 96.977 0.552 ;
     RECT  96.893 30.912 96.977 31.176 ;
     RECT  96.941 63.264 97.085 63.576 ;
     RECT  96.973 10.176 97.121 17.592 ;
     RECT  96.977 30.96 97.148 31.176 ;
     RECT  97.121 14.4 97.157 17.592 ;
     RECT  96.901 1.728 97.187 1.752 ;
     RECT  97.121 10.176 97.193 13.128 ;
     RECT  97.157 14.592 97.225 17.592 ;
     RECT  97.148 30.96 97.229 31.56 ;
     RECT  97.229 31.104 97.235 31.56 ;
     RECT  96.905 3.456 97.244 7.656 ;
     RECT  97.244 3.456 97.333 7.8 ;
     RECT  96.949 47.28 97.369 47.352 ;
     RECT  95.833 58.464 97.369 58.488 ;
     RECT  96.604 68.4 97.369 68.424 ;
     RECT  97.225 14.592 97.373 18.264 ;
     RECT  95.825 40.848 97.379 40.872 ;
     RECT  96.325 44.544 97.379 44.664 ;
     RECT  97.189 33.072 97.409 33.096 ;
     RECT  97.369 47.184 97.409 47.352 ;
     RECT  95.749 48.432 97.409 48.456 ;
     RECT  96.323 53.376 97.409 53.4 ;
     RECT  97.369 57.552 97.409 58.488 ;
     RECT  97.333 43.296 97.42 43.32 ;
     RECT  97.369 67.824 97.429 68.424 ;
     RECT  97.373 14.592 97.445 16.248 ;
     RECT  97.373 17.424 97.445 18.264 ;
     RECT  97.381 38.064 97.468 38.088 ;
     RECT  97.429 67.392 97.475 68.424 ;
     RECT  97.333 3.456 97.481 8.568 ;
     RECT  96.437 22.8 97.481 26.184 ;
     RECT  97.481 22.8 97.525 25.128 ;
     RECT  97.193 10.272 97.553 13.128 ;
     RECT  97.525 24.864 97.564 25.128 ;
     RECT  97.481 26.16 97.585 26.184 ;
     RECT  96.617 27.312 97.585 27.336 ;
     RECT  97.445 14.832 97.589 16.248 ;
     RECT  97.589 14.832 97.697 16.152 ;
     RECT  96.977 0.528 97.715 0.552 ;
     RECT  97.525 22.8 97.837 23.832 ;
     RECT  96.941 19.872 97.873 20.136 ;
     RECT  97.553 10.272 97.949 13.08 ;
     RECT  97.585 26.16 97.949 27.336 ;
     RECT  97.729 21.264 98.089 21.288 ;
     RECT  97.837 22.272 98.089 23.832 ;
     RECT  97.409 47.184 98.093 47.304 ;
     RECT  97.481 3.84 98.165 8.568 ;
     RECT  97.475 67.392 98.197 67.416 ;
     RECT  97.909 1.104 98.237 1.176 ;
     RECT  98.089 21.264 98.237 23.832 ;
     RECT  97.085 63.552 98.265 63.576 ;
     RECT  97.475 68.4 98.265 68.424 ;
     RECT  98.165 3.888 98.273 8.568 ;
     RECT  97.333 41.952 98.341 41.976 ;
     RECT  98.237 21.264 98.345 23.208 ;
     RECT  98.3 43.344 98.387 43.368 ;
     RECT  97.379 44.64 98.387 44.664 ;
     RECT  97.873 19.632 98.449 20.136 ;
     RECT  98.345 21.264 98.449 23.112 ;
     RECT  98.197 0.096 98.489 0.12 ;
     RECT  97.949 10.272 98.489 10.296 ;
     RECT  98.305 28.464 98.521 28.488 ;
     RECT  97.564 24.864 98.557 24.984 ;
     RECT  98.197 62.256 98.557 62.28 ;
     RECT  97.949 11.376 98.593 13.08 ;
     RECT  97.445 17.424 98.629 17.976 ;
     RECT  98.521 28.464 98.629 28.776 ;
     RECT  98.237 1.104 98.723 1.128 ;
     RECT  98.629 17.424 98.725 18.552 ;
     RECT  98.449 19.632 98.725 23.112 ;
     RECT  98.557 24.864 98.773 25.08 ;
     RECT  97.981 27.456 99.025 27.48 ;
     RECT  98.629 28.464 99.025 29.64 ;
     RECT  98.593 11.376 99.397 13.704 ;
     RECT  97.697 14.832 99.397 15.384 ;
     RECT  97.949 26.16 99.493 26.232 ;
     RECT  99.025 27.456 99.493 29.64 ;
     RECT  98.273 3.888 99.608 8.184 ;
     RECT  99.397 11.376 99.608 15.384 ;
     RECT  98.725 17.424 99.608 23.112 ;
     RECT  98.773 24.48 99.608 25.08 ;
     RECT  99.493 26.16 99.608 29.64 ;
     RECT  97.235 31.104 99.608 31.128 ;
     RECT  96.947 37.008 99.608 37.032 ;
     RECT  98.341 41.616 99.608 41.976 ;
     RECT  98.093 47.28 99.608 47.304 ;
     RECT  95.749 52.176 99.608 52.2 ;
     RECT  97.409 57.552 99.608 57.576 ;
     RECT  98.557 62.256 99.608 62.808 ;
     RECT  98.197 67.344 99.608 67.416 ;
     RECT  99.608 2.148 99.712 69.132 ;
     RECT  99.712 2.418 99.904 68.862 ;
     RECT  99.904 13.68 99.965 14.856 ;
     RECT  99.904 22.752 100.001 22.776 ;
     RECT  99.965 13.968 100.019 14.856 ;
     RECT  99.904 27.312 100.073 28.488 ;
     RECT  99.904 17.088 100.109 18.552 ;
     RECT  99.904 41.616 100.115 41.64 ;
     RECT  99.904 4.464 100.145 6.84 ;
     RECT  100.019 14.832 100.145 14.856 ;
     RECT  100.109 17.088 100.289 17.64 ;
     RECT  100.289 17.616 100.361 17.64 ;
     RECT  99.904 19.632 100.361 20.616 ;
     RECT  100.073 27.312 100.397 28.2 ;
     RECT  100.397 28.176 100.469 28.2 ;
     RECT  100.145 4.464 100.721 5.88 ;
     RECT  100.721 5.184 100.829 5.88 ;
     RECT  100.829 5.856 101.081 5.88 ;
    LAYER M5 ;
     RECT  91.08 0.016 91.296 0.037 ;
     RECT  91.32 0.016 91.536 0.037 ;
     RECT  91.56 0.016 91.824 0.037 ;
     RECT  91.848 0.016 92.064 0.037 ;
     RECT  92.088 0.016 92.304 0.037 ;
     RECT  92.328 0.016 92.592 0.037 ;
     RECT  92.616 0.016 92.832 0.037 ;
     RECT  92.856 0.016 93.072 0.037 ;
     RECT  93.096 0.016 93.36 0.037 ;
     RECT  93.384 0.016 93.6 0.037 ;
     RECT  93.624 0.016 93.84 0.037 ;
     RECT  93.864 0.016 94.128 0.037 ;
     RECT  94.152 0.016 94.368 0.037 ;
     RECT  94.392 0.016 94.608 0.037 ;
     RECT  94.632 0.016 94.896 0.037 ;
     RECT  94.92 0.016 95.136 0.037 ;
     RECT  95.16 0.016 95.376 0.037 ;
     RECT  95.4 0.016 95.664 0.037 ;
     RECT  95.688 0.016 95.904 0.037 ;
     RECT  95.928 0.016 96.144 0.037 ;
     RECT  96.168 0.016 96.432 0.037 ;
     RECT  96.456 0.016 96.672 0.037 ;
     RECT  96.696 0.016 96.912 0.037 ;
     RECT  96.936 0.016 97.152 0.037 ;
     RECT  97.176 0.016 97.44 0.037 ;
     RECT  97.464 0.016 97.68 0.037 ;
     RECT  97.704 0.016 97.92 0.037 ;
     RECT  97.944 0.016 98.208 0.037 ;
     RECT  98.232 0.016 98.448 0.037 ;
     RECT  98.472 0.016 98.688 0.037 ;
     RECT  98.712 0.016 98.976 0.037 ;
     RECT  42.024 0.016 42.24 0.084 ;
     RECT  42.264 0.016 42.48 0.084 ;
     RECT  42.504 0.016 42.768 0.084 ;
     RECT  42.792 0.016 43.008 0.084 ;
     RECT  43.032 0.016 43.248 0.084 ;
     RECT  43.272 0.016 43.536 0.084 ;
     RECT  43.56 0.016 43.776 0.084 ;
     RECT  43.8 0.016 44.016 0.084 ;
     RECT  44.04 0.016 44.304 0.084 ;
     RECT  44.328 0.016 44.544 0.084 ;
     RECT  44.568 0.016 44.784 0.084 ;
     RECT  44.808 0.016 45.072 0.084 ;
     RECT  45.096 0.016 45.312 0.084 ;
     RECT  45.336 0.016 45.552 0.084 ;
     RECT  45.576 0.016 45.84 0.084 ;
     RECT  45.864 0.016 46.08 0.084 ;
     RECT  46.104 0.016 46.32 0.084 ;
     RECT  46.344 0.016 46.608 0.084 ;
     RECT  46.632 0.016 46.848 0.084 ;
     RECT  46.872 0.016 47.088 0.084 ;
     RECT  47.112 0.016 47.376 0.084 ;
     RECT  47.4 0.016 47.616 0.084 ;
     RECT  47.64 0.016 47.856 0.084 ;
     RECT  47.88 0.016 48.144 0.084 ;
     RECT  48.168 0.016 48.384 0.084 ;
     RECT  48.408 0.016 48.624 0.084 ;
     RECT  48.648 0.016 48.912 0.084 ;
     RECT  48.936 0.016 49.152 0.084 ;
     RECT  49.176 0.016 49.392 0.084 ;
     RECT  49.416 0.016 49.68 0.084 ;
     RECT  49.704 0.016 49.92 0.084 ;
     RECT  42 0.084 49.944 0.085 ;
     RECT  74.712 0.016 74.928 0.084 ;
     RECT  74.952 0.016 75.216 0.084 ;
     RECT  75.24 0.016 75.456 0.084 ;
     RECT  75.48 0.016 75.696 0.084 ;
     RECT  75.72 0.016 75.984 0.084 ;
     RECT  76.008 0.016 76.224 0.084 ;
     RECT  76.248 0.016 76.464 0.084 ;
     RECT  76.488 0.016 76.752 0.084 ;
     RECT  76.776 0.016 76.992 0.084 ;
     RECT  77.016 0.016 77.232 0.084 ;
     RECT  77.256 0.016 77.52 0.084 ;
     RECT  77.544 0.016 77.76 0.084 ;
     RECT  77.784 0.016 78 0.084 ;
     RECT  78.024 0.016 78.288 0.084 ;
     RECT  78.312 0.016 78.528 0.084 ;
     RECT  78.552 0.016 78.768 0.084 ;
     RECT  78.792 0.016 79.056 0.084 ;
     RECT  79.08 0.016 79.296 0.084 ;
     RECT  79.32 0.016 79.536 0.084 ;
     RECT  79.56 0.016 79.824 0.084 ;
     RECT  79.848 0.016 80.064 0.084 ;
     RECT  80.088 0.016 80.304 0.084 ;
     RECT  80.328 0.016 80.592 0.084 ;
     RECT  80.616 0.016 80.832 0.084 ;
     RECT  80.856 0.016 81.072 0.084 ;
     RECT  81.096 0.016 81.36 0.084 ;
     RECT  81.384 0.016 81.6 0.084 ;
     RECT  81.624 0.016 81.84 0.084 ;
     RECT  81.864 0.016 82.08 0.084 ;
     RECT  82.104 0.016 82.368 0.084 ;
     RECT  82.392 0.016 82.608 0.084 ;
     RECT  74.688 0.084 82.632 0.131 ;
     RECT  90.96 0.037 91.056 0.084 ;
     RECT  91.08 0.037 91.296 0.084 ;
     RECT  91.32 0.037 91.536 0.084 ;
     RECT  91.56 0.037 91.824 0.084 ;
     RECT  91.848 0.037 92.064 0.084 ;
     RECT  92.088 0.037 92.304 0.084 ;
     RECT  92.328 0.037 92.592 0.084 ;
     RECT  92.616 0.037 92.832 0.084 ;
     RECT  92.856 0.037 93.072 0.084 ;
     RECT  93.096 0.037 93.36 0.084 ;
     RECT  93.384 0.037 93.6 0.084 ;
     RECT  93.624 0.037 93.84 0.084 ;
     RECT  93.864 0.037 94.128 0.084 ;
     RECT  94.152 0.037 94.368 0.084 ;
     RECT  94.392 0.037 94.608 0.084 ;
     RECT  94.632 0.037 94.896 0.084 ;
     RECT  94.92 0.037 95.136 0.084 ;
     RECT  95.16 0.037 95.376 0.084 ;
     RECT  95.4 0.037 95.664 0.084 ;
     RECT  95.688 0.037 95.904 0.084 ;
     RECT  95.928 0.037 96.144 0.084 ;
     RECT  96.168 0.037 96.432 0.084 ;
     RECT  96.456 0.037 96.672 0.084 ;
     RECT  96.696 0.037 96.912 0.084 ;
     RECT  96.936 0.037 97.152 0.084 ;
     RECT  97.176 0.037 97.44 0.084 ;
     RECT  97.464 0.037 97.68 0.084 ;
     RECT  97.704 0.037 97.92 0.084 ;
     RECT  97.944 0.037 98.208 0.084 ;
     RECT  98.232 0.037 98.448 0.084 ;
     RECT  98.472 0.037 98.688 0.084 ;
     RECT  98.712 0.037 98.976 0.084 ;
     RECT  90.96 0.084 99 0.179 ;
     RECT  91.536 0.179 99 0.659 ;
     RECT  58.344 0.016 58.608 0.084 ;
     RECT  58.632 0.016 58.848 0.084 ;
     RECT  58.872 0.016 59.088 0.084 ;
     RECT  59.112 0.016 59.376 0.084 ;
     RECT  59.4 0.016 59.616 0.084 ;
     RECT  59.64 0.016 59.856 0.084 ;
     RECT  59.88 0.016 60.144 0.084 ;
     RECT  60.168 0.016 60.384 0.084 ;
     RECT  60.408 0.016 60.624 0.084 ;
     RECT  60.648 0.016 60.912 0.084 ;
     RECT  60.936 0.016 61.152 0.084 ;
     RECT  61.176 0.016 61.392 0.084 ;
     RECT  61.416 0.016 61.68 0.084 ;
     RECT  61.704 0.016 61.92 0.084 ;
     RECT  61.944 0.016 62.16 0.084 ;
     RECT  62.184 0.016 62.448 0.084 ;
     RECT  62.472 0.016 62.688 0.084 ;
     RECT  62.712 0.016 62.928 0.084 ;
     RECT  62.952 0.016 63.216 0.084 ;
     RECT  63.24 0.016 63.456 0.084 ;
     RECT  63.48 0.016 63.696 0.084 ;
     RECT  63.72 0.016 63.984 0.084 ;
     RECT  64.008 0.016 64.224 0.084 ;
     RECT  64.248 0.016 64.464 0.084 ;
     RECT  64.488 0.016 64.752 0.084 ;
     RECT  64.776 0.016 64.992 0.084 ;
     RECT  65.016 0.016 65.232 0.084 ;
     RECT  65.256 0.016 65.52 0.084 ;
     RECT  65.544 0.016 65.76 0.084 ;
     RECT  65.784 0.016 66 0.084 ;
     RECT  66.024 0.016 66.24 0.084 ;
     RECT  58.32 0.084 66.264 1.139 ;
     RECT  74.928 0.131 82.632 1.139 ;
     RECT  96.672 0.659 99 1.139 ;
     RECT  25.656 0.016 25.92 0.084 ;
     RECT  25.944 0.016 26.16 0.084 ;
     RECT  26.184 0.016 26.4 0.084 ;
     RECT  26.424 0.016 26.64 0.084 ;
     RECT  26.664 0.016 26.928 0.084 ;
     RECT  26.952 0.016 27.168 0.084 ;
     RECT  27.192 0.016 27.408 0.084 ;
     RECT  27.432 0.016 27.696 0.084 ;
     RECT  27.72 0.016 27.936 0.084 ;
     RECT  27.96 0.016 28.176 0.084 ;
     RECT  28.2 0.016 28.464 0.084 ;
     RECT  28.488 0.016 28.704 0.084 ;
     RECT  28.728 0.016 28.944 0.084 ;
     RECT  28.968 0.016 29.232 0.084 ;
     RECT  29.256 0.016 29.472 0.084 ;
     RECT  29.496 0.016 29.712 0.084 ;
     RECT  29.736 0.016 30 0.084 ;
     RECT  30.024 0.016 30.24 0.084 ;
     RECT  30.264 0.016 30.48 0.084 ;
     RECT  30.504 0.016 30.768 0.084 ;
     RECT  30.792 0.016 31.008 0.084 ;
     RECT  31.032 0.016 31.248 0.084 ;
     RECT  31.272 0.016 31.536 0.084 ;
     RECT  31.56 0.016 31.776 0.084 ;
     RECT  31.8 0.016 32.016 0.084 ;
     RECT  32.04 0.016 32.304 0.084 ;
     RECT  32.328 0.016 32.544 0.084 ;
     RECT  32.568 0.016 32.784 0.084 ;
     RECT  32.808 0.016 33.072 0.084 ;
     RECT  33.096 0.016 33.312 0.084 ;
     RECT  33.336 0.016 33.552 0.084 ;
     RECT  25.632 0.084 33.576 1.187 ;
     RECT  42 0.085 50.616 1.187 ;
     RECT  62.928 1.139 66.264 1.187 ;
     RECT  75.456 1.139 82.632 1.187 ;
     RECT  91.536 0.659 95.4 1.187 ;
     RECT  97.152 1.139 97.944 1.187 ;
     RECT  93.84 1.187 95.4 1.235 ;
     RECT  9.336 0.016 9.552 0.084 ;
     RECT  9.576 0.016 9.792 0.084 ;
     RECT  9.816 0.016 10.08 0.084 ;
     RECT  10.104 0.016 10.32 0.084 ;
     RECT  10.344 0.016 10.56 0.084 ;
     RECT  10.584 0.016 10.848 0.084 ;
     RECT  10.872 0.016 11.088 0.084 ;
     RECT  11.112 0.016 11.328 0.084 ;
     RECT  11.352 0.016 11.568 0.084 ;
     RECT  11.592 0.016 11.856 0.084 ;
     RECT  11.88 0.016 12.096 0.084 ;
     RECT  12.12 0.016 12.336 0.084 ;
     RECT  12.36 0.016 12.624 0.084 ;
     RECT  12.648 0.016 12.864 0.084 ;
     RECT  12.888 0.016 13.104 0.084 ;
     RECT  13.128 0.016 13.392 0.084 ;
     RECT  13.416 0.016 13.632 0.084 ;
     RECT  13.656 0.016 13.872 0.084 ;
     RECT  13.896 0.016 14.16 0.084 ;
     RECT  14.184 0.016 14.4 0.084 ;
     RECT  14.424 0.016 14.64 0.084 ;
     RECT  14.664 0.016 14.928 0.084 ;
     RECT  14.952 0.016 15.168 0.084 ;
     RECT  15.192 0.016 15.408 0.084 ;
     RECT  15.432 0.016 15.696 0.084 ;
     RECT  15.72 0.016 15.936 0.084 ;
     RECT  15.96 0.016 16.176 0.084 ;
     RECT  16.2 0.016 16.464 0.084 ;
     RECT  16.488 0.016 16.704 0.084 ;
     RECT  16.728 0.016 16.944 0.084 ;
     RECT  16.968 0.016 17.232 0.084 ;
     RECT  9.312 0.084 17.256 1.763 ;
     RECT  25.632 1.187 31.032 1.763 ;
     RECT  32.304 1.187 33.576 1.763 ;
     RECT  42.24 1.187 50.616 1.763 ;
     RECT  58.32 1.139 61.944 1.763 ;
     RECT  62.928 1.187 62.952 1.763 ;
     RECT  63.984 1.187 66.264 1.763 ;
     RECT  75.456 1.187 82.392 1.763 ;
     RECT  97.152 1.187 97.176 1.763 ;
     RECT  32.784 1.763 33.096 1.811 ;
     RECT  42.24 1.763 45.912 1.811 ;
     RECT  60.912 1.763 61.944 1.811 ;
     RECT  79.536 1.763 79.56 1.811 ;
     RECT  50.592 1.763 50.616 2.137 ;
     RECT  98.976 1.139 99 2.137 ;
     RECT  2.4 2.137 2.52 2.151 ;
     RECT  7.8 2.137 7.92 2.151 ;
     RECT  18.6 2.137 18.72 2.151 ;
     RECT  24 2.137 24.12 2.151 ;
     RECT  34.8 2.137 34.92 2.151 ;
     RECT  40.2 2.137 40.32 2.151 ;
     RECT  50.592 2.137 51.12 2.151 ;
     RECT  56.4 2.137 56.52 2.151 ;
     RECT  61.8 1.811 61.944 2.151 ;
     RECT  67.2 2.137 67.32 2.151 ;
     RECT  72.6 2.137 72.72 2.151 ;
     RECT  83.4 2.137 83.52 2.151 ;
     RECT  88.8 2.137 88.92 2.151 ;
     RECT  98.976 2.137 99.72 2.151 ;
     RECT  2.4 2.151 2.712 2.725 ;
     RECT  34.8 2.151 35.112 2.773 ;
     RECT  26.4 1.763 26.952 2.821 ;
     RECT  11.856 1.763 13.512 2.915 ;
     RECT  15.696 1.763 15.96 2.915 ;
     RECT  17.232 1.763 17.256 2.915 ;
     RECT  26.208 2.821 26.952 2.915 ;
     RECT  28.704 1.763 30.024 2.915 ;
     RECT  31.008 1.763 31.032 2.915 ;
     RECT  33.072 1.811 33.096 2.915 ;
     RECT  42.24 1.811 42.504 2.915 ;
     RECT  45.312 1.811 45.912 2.915 ;
     RECT  47.616 1.763 48.168 2.915 ;
     RECT  58.32 1.763 58.344 2.915 ;
     RECT  59.616 1.763 59.64 2.915 ;
     RECT  64.224 1.763 64.776 2.915 ;
     RECT  76.224 1.763 76.776 2.915 ;
     RECT  15.936 2.915 15.96 2.963 ;
     RECT  64.464 2.915 64.488 3.011 ;
     RECT  83.4 2.151 83.712 3.349 ;
     RECT  61.8 2.151 62.112 3.445 ;
     RECT  26.208 2.915 26.232 3.587 ;
     RECT  83.4 3.349 83.832 3.587 ;
     RECT  92.544 1.187 92.856 3.637 ;
     RECT  34.8 2.773 35.208 3.731 ;
     RECT  91.632 3.637 92.856 3.829 ;
     RECT  45.6 2.915 45.912 3.877 ;
     RECT  69.456 3.301 69.48 3.971 ;
     RECT  93.84 1.235 94.92 4.019 ;
     RECT  18.6 2.151 18.912 4.117 ;
     RECT  49.104 4.021 49.128 4.117 ;
     RECT  40.2 2.151 40.512 4.165 ;
     RECT  48.192 4.117 49.128 4.259 ;
     RECT  24 2.151 24.312 4.261 ;
     RECT  49.104 4.259 49.128 4.403 ;
     RECT  13.2 2.915 13.512 4.405 ;
     RECT  2.4 2.725 3.144 4.501 ;
     RECT  4.272 3.349 4.296 4.501 ;
     RECT  21.648 3.829 21.672 4.595 ;
     RECT  45.6 3.877 46.008 4.597 ;
     RECT  28.32 4.645 28.344 4.693 ;
     RECT  29.4 2.915 29.712 4.693 ;
     RECT  78 1.763 78.408 4.693 ;
     RECT  56.4 2.151 56.712 4.741 ;
     RECT  83.4 3.587 83.712 4.741 ;
     RECT  11.52 4.645 11.544 4.789 ;
     RECT  28.32 4.693 29.712 4.883 ;
     RECT  52.512 4.837 53.016 4.979 ;
     RECT  10.704 4.789 11.544 5.027 ;
     RECT  52.512 4.979 52.536 5.027 ;
     RECT  7.8 2.151 8.112 5.029 ;
     RECT  45.6 4.597 46.104 5.029 ;
     RECT  29.4 4.883 29.712 5.077 ;
     RECT  56.4 4.741 56.808 5.077 ;
     RECT  61.68 3.445 62.112 5.077 ;
     RECT  72.6 2.151 72.912 5.077 ;
     RECT  93.936 4.019 94.92 5.123 ;
     RECT  36.576 5.029 36.6 5.125 ;
     RECT  11.376 5.027 11.544 5.173 ;
     RECT  24 4.261 24.456 5.173 ;
     RECT  77.712 4.693 78.408 5.219 ;
     RECT  40.2 4.165 40.92 5.269 ;
     RECT  61.68 5.077 62.28 5.269 ;
     RECT  72.336 5.077 73.56 5.365 ;
     RECT  29.4 5.077 30.168 5.411 ;
     RECT  39.888 5.269 41.016 5.459 ;
     RECT  36.576 5.125 36.696 5.461 ;
     RECT  7.8 5.029 8.424 5.507 ;
     RECT  36.528 5.461 36.696 5.507 ;
     RECT  76.128 5.317 76.152 5.555 ;
     RECT  93.984 5.123 94.92 5.651 ;
     RECT  91.2 3.829 92.856 5.699 ;
     RECT  13.2 4.405 13.608 5.701 ;
     RECT  72.336 5.365 73.656 5.747 ;
     RECT  91.632 5.699 92.856 5.747 ;
     RECT  94.08 5.651 94.92 5.747 ;
     RECT  42.144 4.501 42.168 5.941 ;
     RECT  85.392 5.797 85.416 5.989 ;
     RECT  13.104 5.701 13.608 6.037 ;
     RECT  24 5.173 25.128 6.133 ;
     RECT  85.392 5.989 85.896 6.179 ;
     RECT  53.76 5.605 53.784 6.227 ;
     RECT  2.4 4.501 4.296 6.229 ;
     RECT  33.072 5.989 33.096 6.275 ;
     RECT  45.6 5.029 46.152 6.275 ;
     RECT  87.216 4.549 87.24 6.275 ;
     RECT  60.576 5.941 60.6 6.277 ;
     RECT  61.584 5.269 62.28 6.277 ;
     RECT  17.712 4.117 18.912 6.323 ;
     RECT  24 6.133 25.176 6.323 ;
     RECT  45.6 6.275 46.056 6.323 ;
     RECT  83.232 4.741 83.712 6.371 ;
     RECT  94.2 5.747 94.728 6.371 ;
     RECT  56.4 5.077 57.624 6.515 ;
     RECT  24 6.323 25.128 6.563 ;
     RECT  60.576 6.277 62.28 6.563 ;
     RECT  77.712 5.219 78.312 6.563 ;
     RECT  2.4 6.229 4.536 6.565 ;
     RECT  5.952 5.077 5.976 6.565 ;
     RECT  39.888 5.459 40.92 6.611 ;
     RECT  83.28 6.371 83.712 6.757 ;
     RECT  85.392 6.179 85.464 6.757 ;
     RECT  60.576 6.563 62.112 6.803 ;
     RECT  91.632 5.747 92.376 6.803 ;
     RECT  2.4 6.565 5.976 6.805 ;
     RECT  17.904 6.323 18.912 6.805 ;
     RECT  20.064 4.645 20.088 6.805 ;
     RECT  36.528 5.507 36.552 6.805 ;
     RECT  37.92 5.749 37.944 6.805 ;
     RECT  56.4 6.515 56.712 6.805 ;
     RECT  13.056 6.037 13.608 6.851 ;
     RECT  36.528 6.805 37.944 6.851 ;
     RECT  42.144 5.941 42.648 6.899 ;
     RECT  28.32 4.883 28.344 6.901 ;
     RECT  29.4 5.411 29.712 6.901 ;
     RECT  17.904 6.805 20.088 6.995 ;
     RECT  76.848 6.853 76.872 7.139 ;
     RECT  24 6.563 25.08 7.235 ;
     RECT  54.816 6.037 54.84 7.237 ;
     RECT  2.4 6.805 6.168 7.331 ;
     RECT  65.28 4.693 65.304 7.379 ;
     RECT  28.32 6.901 29.712 7.381 ;
     RECT  45.6 6.323 45.912 7.381 ;
     RECT  54.672 7.237 54.84 7.381 ;
     RECT  56.016 6.805 56.712 7.381 ;
     RECT  83.28 6.757 85.464 7.427 ;
     RECT  11.376 5.173 11.736 7.475 ;
     RECT  2.4 7.331 5.304 7.571 ;
     RECT  50.592 2.151 51.312 7.717 ;
     RECT  97.344 5.461 97.368 7.765 ;
     RECT  11.664 7.475 11.736 7.957 ;
     RECT  33.552 6.709 33.576 7.957 ;
     RECT  72.6 5.747 73.656 7.957 ;
     RECT  11.664 7.957 12.072 8.003 ;
     RECT  31.776 7.237 31.8 8.003 ;
     RECT  36.528 6.851 37.032 8.003 ;
     RECT  70.656 7.093 70.68 8.003 ;
     RECT  28.08 7.381 29.712 8.051 ;
     RECT  36.672 8.003 37.032 8.051 ;
     RECT  50.592 7.717 52.296 8.051 ;
     RECT  11.712 8.003 12.072 8.099 ;
     RECT  40.2 6.611 40.92 8.149 ;
     RECT  98.976 2.151 99.912 8.195 ;
     RECT  47.904 7.957 47.928 8.197 ;
     RECT  28.32 8.051 29.712 8.291 ;
     RECT  45.504 7.381 45.912 8.435 ;
     RECT  40.2 8.149 41.112 8.437 ;
     RECT  65.328 7.957 65.352 8.485 ;
     RECT  61.344 6.803 62.112 8.533 ;
     RECT  97.296 7.765 97.368 8.579 ;
     RECT  40.2 8.437 41.64 8.581 ;
     RECT  42.624 6.899 42.648 8.581 ;
     RECT  48.96 6.229 48.984 8.581 ;
     RECT  40.2 8.581 42.648 8.629 ;
     RECT  36.672 8.051 36.792 8.675 ;
     RECT  47.376 8.197 47.928 8.677 ;
     RECT  75.504 7.429 75.528 8.723 ;
     RECT  65.328 8.485 65.544 8.725 ;
     RECT  39.936 8.629 42.648 8.819 ;
     RECT  47.232 8.677 47.928 8.819 ;
     RECT  64.8 8.725 66.168 8.867 ;
     RECT  18.6 6.995 20.088 8.917 ;
     RECT  51 8.051 52.296 8.963 ;
     RECT  65.328 8.867 66.168 8.965 ;
     RECT  67.2 2.151 67.512 8.965 ;
     RECT  65.328 8.965 67.512 9.011 ;
     RECT  83.4 7.427 85.464 9.011 ;
     RECT  51 8.963 51.48 9.013 ;
     RECT  58.368 8.485 58.392 9.013 ;
     RECT  59.52 5.701 59.544 9.013 ;
     RECT  61.104 8.533 62.112 9.013 ;
     RECT  70.704 8.389 70.728 9.013 ;
     RECT  29.136 8.291 29.712 9.059 ;
     RECT  18.48 8.917 20.088 9.061 ;
     RECT  92.352 6.803 92.376 9.061 ;
     RECT  15.936 8.965 15.96 9.107 ;
     RECT  48.96 8.581 49.608 9.155 ;
     RECT  70.56 9.013 70.728 9.155 ;
     RECT  48.96 9.155 48.984 9.203 ;
     RECT  58.368 9.013 59.544 9.203 ;
     RECT  2.4 7.571 4.536 9.251 ;
     RECT  54.672 7.381 56.712 9.251 ;
     RECT  31.344 9.013 31.368 9.299 ;
     RECT  95.76 9.061 95.784 9.299 ;
     RECT  24 7.235 24.696 9.349 ;
     RECT  26.256 9.061 26.28 9.349 ;
     RECT  33.552 7.957 33.672 9.349 ;
     RECT  34.8 3.731 35.112 9.349 ;
     RECT  39.936 8.819 41.64 9.349 ;
     RECT  94.2 6.371 94.512 9.349 ;
     RECT  78 6.563 78.312 9.397 ;
     RECT  4.272 9.251 4.536 9.443 ;
     RECT  33.552 9.349 35.544 9.539 ;
     RECT  33.552 9.539 35.208 9.587 ;
     RECT  24 9.349 26.28 9.589 ;
     RECT  70.56 9.155 70.584 9.589 ;
     RECT  61.104 9.013 62.808 9.637 ;
     RECT  17.664 9.061 20.088 9.731 ;
     RECT  21.648 9.013 21.672 9.731 ;
     RECT  65.328 9.011 65.544 9.731 ;
     RECT  83.4 9.011 84.984 9.731 ;
     RECT  24 9.589 26.808 9.779 ;
     RECT  17.664 9.731 19.56 9.875 ;
     RECT  4.512 9.443 4.536 9.923 ;
     RECT  58.704 9.203 59.544 9.923 ;
     RECT  88.8 2.151 89.112 9.925 ;
     RECT  42.624 8.819 42.648 9.971 ;
     RECT  92.304 9.061 92.376 9.971 ;
     RECT  72.096 7.957 73.656 9.973 ;
     RECT  65.52 9.731 65.544 10.019 ;
     RECT  33.552 9.587 35.112 10.069 ;
     RECT  50.832 9.013 51.48 10.069 ;
     RECT  83.4 9.731 84.648 10.069 ;
     RECT  92.352 9.971 92.376 10.069 ;
     RECT  94.2 9.349 95.16 10.069 ;
     RECT  11.712 8.099 11.736 10.213 ;
     RECT  50.64 10.069 51.48 10.213 ;
     RECT  69.264 5.605 69.288 10.213 ;
     RECT  71.76 9.973 73.656 10.213 ;
     RECT  74.736 9.349 74.76 10.213 ;
     RECT  32.928 10.069 35.112 10.259 ;
     RECT  6.288 8.485 6.312 10.261 ;
     RECT  61.008 9.637 62.808 10.261 ;
     RECT  6.288 10.261 6.792 10.307 ;
     RECT  24 9.779 25.608 10.307 ;
     RECT  61.008 10.261 62.952 10.355 ;
     RECT  42.72 10.213 42.744 10.453 ;
     RECT  43.92 9.925 43.944 10.453 ;
     RECT  68.976 10.213 69.288 10.501 ;
     RECT  70.464 9.589 70.584 10.501 ;
     RECT  29.184 9.059 29.712 10.595 ;
     RECT  42.72 10.453 43.944 10.597 ;
     RECT  45.6 8.435 45.912 10.597 ;
     RECT  47.232 8.819 47.4 10.597 ;
     RECT  88.8 9.925 89.352 10.597 ;
     RECT  93.84 10.069 95.16 10.645 ;
     RECT  2.4 9.251 2.712 10.693 ;
     RECT  24 10.307 24.504 10.693 ;
     RECT  45.6 10.597 47.4 10.741 ;
     RECT  23.856 10.693 24.504 10.835 ;
     RECT  39.312 9.349 41.64 10.883 ;
     RECT  71.76 10.213 74.76 10.883 ;
     RECT  11.712 10.213 12.024 10.931 ;
     RECT  14.928 10.261 14.952 10.933 ;
     RECT  14.928 10.933 15.336 10.981 ;
     RECT  68.976 10.501 70.584 11.027 ;
     RECT  54.672 9.251 54.696 11.173 ;
     RECT  55.728 9.251 56.712 11.173 ;
     RECT  58.848 9.923 59.544 11.173 ;
     RECT  42.72 10.597 44.472 11.267 ;
     RECT  14.928 10.981 16.152 11.365 ;
     RECT  66.528 9.011 67.512 11.365 ;
     RECT  99.6 8.195 99.912 11.365 ;
     RECT  78 9.397 79.08 11.411 ;
     RECT  45.6 10.741 47.688 11.459 ;
     RECT  66.528 11.365 68.28 11.459 ;
     RECT  69.264 11.027 70.584 11.459 ;
     RECT  97.296 8.579 97.32 11.459 ;
     RECT  54.672 11.173 56.712 11.461 ;
     RECT  14.88 11.365 16.152 11.507 ;
     RECT  76.08 10.597 76.584 11.509 ;
     RECT  78 11.411 78.312 11.509 ;
     RECT  64.896 11.365 64.92 11.555 ;
     RECT  42.72 11.267 43.944 11.603 ;
     RECT  92.352 10.069 92.712 11.603 ;
     RECT  50.544 10.213 51.48 11.701 ;
     RECT  82.608 10.069 84.648 11.701 ;
     RECT  86.064 11.365 86.088 11.701 ;
     RECT  92.688 11.603 92.712 11.797 ;
     RECT  93.792 10.645 95.16 11.797 ;
     RECT  20.544 11.701 20.568 11.843 ;
     RECT  33.552 10.259 35.112 11.941 ;
     RECT  54.672 11.461 57.48 11.941 ;
     RECT  58.656 11.173 59.544 11.941 ;
     RECT  61.584 10.355 62.952 11.941 ;
     RECT  33.552 11.941 35.208 11.987 ;
     RECT  88.8 10.597 90.12 11.987 ;
     RECT  11.712 10.931 11.736 12.035 ;
     RECT  69.264 11.459 69.288 12.035 ;
     RECT  6.768 10.307 6.792 12.131 ;
     RECT  53.424 11.173 53.448 12.181 ;
     RECT  52.464 12.181 53.448 12.275 ;
     RECT  34.8 11.987 35.208 12.325 ;
     RECT  71.76 10.883 73.656 12.325 ;
     RECT  97.584 11.941 97.608 12.469 ;
     RECT  36.768 10.741 36.792 12.515 ;
     RECT  42.72 11.603 43.128 12.517 ;
     RECT  66.624 11.459 68.28 12.517 ;
     RECT  88.8 11.987 89.496 12.517 ;
     RECT  9.456 11.941 9.48 12.563 ;
     RECT  22.896 11.365 22.92 12.563 ;
     RECT  26.784 9.779 26.808 12.563 ;
     RECT  82.608 11.701 86.088 12.563 ;
     RECT  98.64 11.365 99.912 12.563 ;
     RECT  13.2 6.851 13.512 12.565 ;
     RECT  29.4 10.595 29.712 12.565 ;
     RECT  38.88 11.941 38.904 12.755 ;
     RECT  96.864 12.469 97.608 12.757 ;
     RECT  91.2 12.517 91.224 12.805 ;
     RECT  34.8 12.325 35.592 12.853 ;
     RECT  66.624 12.517 68.856 12.899 ;
     RECT  88.704 12.517 89.496 12.947 ;
     RECT  42.624 12.517 43.128 12.997 ;
     RECT  49.968 11.701 51.48 12.997 ;
     RECT  17.232 12.421 17.256 13.043 ;
     RECT  29.088 12.565 29.712 13.043 ;
     RECT  14.88 11.507 15.336 13.045 ;
     RECT  61.008 11.941 62.952 13.045 ;
     RECT  92.688 11.797 95.16 13.045 ;
     RECT  96.624 12.757 97.608 13.045 ;
     RECT  24 10.835 24.504 13.091 ;
     RECT  54.672 11.941 59.544 13.093 ;
     RECT  61.008 13.045 63.816 13.139 ;
     RECT  13.104 12.565 13.512 13.235 ;
     RECT  71.76 12.325 74.568 13.285 ;
     RECT  14.832 13.045 15.336 13.331 ;
     RECT  61.584 13.139 63.816 13.331 ;
     RECT  16.992 13.285 17.016 13.427 ;
     RECT  25.584 10.307 25.608 13.525 ;
     RECT  92.688 13.045 97.608 13.619 ;
     RECT  40.032 10.883 41.112 13.621 ;
     RECT  81.264 8.821 81.288 13.621 ;
     RECT  52.464 12.275 52.488 13.667 ;
     RECT  2.4 10.693 2.808 13.715 ;
     RECT  66.624 12.899 68.28 13.715 ;
     RECT  99.6 12.563 99.912 13.957 ;
     RECT  25.584 13.525 26.232 14.099 ;
     RECT  71.76 13.285 75.096 14.099 ;
     RECT  22.992 12.853 23.016 14.147 ;
     RECT  54.672 13.093 59.64 14.197 ;
     RECT  66.624 13.715 67.512 14.197 ;
     RECT  81.264 13.621 81.528 14.197 ;
     RECT  76.08 11.509 78.312 14.291 ;
     RECT  49.92 12.997 51.48 14.293 ;
     RECT  49.392 14.293 51.48 14.339 ;
     RECT  80.64 14.197 81.528 14.339 ;
     RECT  24 13.091 24.312 14.389 ;
     RECT  99.6 13.957 100.008 14.485 ;
     RECT  61.584 13.331 62.952 14.627 ;
     RECT  93.744 13.619 97.608 14.627 ;
     RECT  76.224 14.291 78.312 14.629 ;
     RECT  25.728 14.099 26.232 14.675 ;
     RECT  54.672 14.197 59.736 14.725 ;
     RECT  76.224 14.629 79.272 14.771 ;
     RECT  47.376 11.459 47.688 14.773 ;
     RECT  70.56 11.459 70.584 14.773 ;
     RECT  20.784 13.669 20.808 14.819 ;
     RECT  70.464 14.773 70.584 14.819 ;
     RECT  34.8 12.853 36.408 14.821 ;
     RECT  14.928 13.331 15.336 14.867 ;
     RECT  99.408 14.485 100.008 14.867 ;
     RECT  99.408 14.867 99.912 14.917 ;
     RECT  88.704 12.947 89.352 15.013 ;
     RECT  90.48 12.805 91.224 15.013 ;
     RECT  54.288 14.725 59.736 15.203 ;
     RECT  88.704 15.013 91.224 15.203 ;
     RECT  88.704 15.203 89.352 15.253 ;
     RECT  24 14.389 24.408 15.301 ;
     RECT  25.728 14.675 25.752 15.301 ;
     RECT  11.376 13.669 11.4 15.349 ;
     RECT  10.848 15.349 11.4 15.395 ;
     RECT  82.896 12.563 85.464 15.397 ;
     RECT  87.792 15.253 89.352 15.397 ;
     RECT  34.56 14.821 36.408 15.443 ;
     RECT  93.984 14.627 97.608 15.443 ;
     RECT  49.392 14.339 49.416 15.491 ;
     RECT  87.744 15.397 89.352 15.683 ;
     RECT  76.224 14.771 78.312 15.733 ;
     RECT  82.656 15.397 85.464 15.733 ;
     RECT  80.64 14.339 81.288 15.781 ;
     RECT  82.656 15.733 86.424 15.781 ;
     RECT  7.8 5.507 8.112 15.829 ;
     RECT  61.584 14.627 62.808 15.829 ;
     RECT  66.24 14.197 67.512 15.829 ;
     RECT  16.896 15.013 16.92 15.877 ;
     RECT  76.224 15.733 78.408 15.877 ;
     RECT  16.56 15.877 16.92 15.923 ;
     RECT  80.64 15.781 86.424 15.923 ;
     RECT  65.28 15.829 67.512 15.925 ;
     RECT  10.848 15.395 10.872 16.019 ;
     RECT  18.48 9.875 19.56 16.019 ;
     RECT  60.624 15.829 62.808 16.021 ;
     RECT  70.464 14.819 70.488 16.021 ;
     RECT  6.864 15.829 8.112 16.403 ;
     RECT  16.56 15.923 16.584 16.403 ;
     RECT  69.888 16.021 70.488 16.405 ;
     RECT  33.552 11.987 33.576 16.453 ;
     RECT  47.376 14.773 47.88 16.453 ;
     RECT  88.8 15.683 89.352 16.453 ;
     RECT  90.336 15.203 91.224 16.453 ;
     RECT  47.328 16.453 47.88 16.499 ;
     RECT  33.504 16.453 33.576 16.501 ;
     RECT  52.944 15.877 52.968 16.595 ;
     RECT  93.984 15.443 96.936 16.595 ;
     RECT  60.624 16.021 63.48 16.597 ;
     RECT  60.624 16.597 63.624 16.739 ;
     RECT  69.696 16.405 70.488 16.835 ;
     RECT  75.744 15.877 78.408 16.835 ;
     RECT  87.744 15.683 87.816 16.837 ;
     RECT  88.8 16.453 91.224 16.837 ;
     RECT  69.888 16.835 70.488 16.883 ;
     RECT  45.6 11.459 45.912 16.981 ;
     RECT  45.024 16.981 45.912 17.029 ;
     RECT  24 15.301 25.752 17.075 ;
     RECT  93.984 16.595 96.648 17.075 ;
     RECT  82.896 15.923 86.424 17.171 ;
     RECT  87.744 16.837 91.224 17.219 ;
     RECT  21.072 17.077 21.096 17.267 ;
     RECT  32.832 16.501 33.576 17.459 ;
     RECT  87.84 17.219 91.224 17.459 ;
     RECT  90.336 17.459 91.224 17.461 ;
     RECT  65.088 15.925 67.512 17.509 ;
     RECT  68.592 16.837 68.616 17.509 ;
     RECT  42.576 12.997 43.128 17.605 ;
     RECT  45.024 17.029 46.104 17.605 ;
     RECT  75.744 16.835 78.312 17.605 ;
     RECT  80.64 15.923 81.528 17.605 ;
     RECT  75.552 17.605 78.312 17.699 ;
     RECT  82.896 17.171 85.464 17.843 ;
     RECT  65.088 17.509 68.616 17.845 ;
     RECT  64.992 17.845 68.616 17.893 ;
     RECT  24 17.075 25.368 17.987 ;
     RECT  64.992 17.893 69.336 17.987 ;
     RECT  80.352 17.605 81.528 18.131 ;
     RECT  7.008 16.403 8.112 18.133 ;
     RECT  18.48 16.019 19.224 18.133 ;
     RECT  13.2 13.235 13.512 18.181 ;
     RECT  71.76 14.099 74.568 18.229 ;
     RECT  75.552 17.699 75.768 18.229 ;
     RECT  45.024 17.605 46.248 18.275 ;
     RECT  71.76 18.229 75.768 18.275 ;
     RECT  87.84 17.459 89.112 18.275 ;
     RECT  12.48 18.181 14.184 18.467 ;
     RECT  27.6 17.653 27.624 18.515 ;
     RECT  33.504 17.459 33.576 18.517 ;
     RECT  98.64 14.917 99.912 18.563 ;
     RECT  77.088 17.699 78.312 18.659 ;
     RECT  88.8 18.275 89.112 18.757 ;
     RECT  90.336 17.461 91.368 18.757 ;
     RECT  7.008 18.133 8.376 18.851 ;
     RECT  47.328 16.499 47.688 18.851 ;
     RECT  42.432 17.605 43.368 18.853 ;
     RECT  48.96 18.181 48.984 18.899 ;
     RECT  39.792 13.621 41.112 18.949 ;
     RECT  38.352 16.981 38.376 18.995 ;
     RECT  65.376 17.987 69.336 18.995 ;
     RECT  70.464 16.883 70.488 18.995 ;
     RECT  80.352 18.131 81.288 18.995 ;
     RECT  54.288 15.203 59.64 18.997 ;
     RECT  60.624 16.739 62.808 18.997 ;
     RECT  12.48 18.467 13.896 19.091 ;
     RECT  18.48 18.133 19.512 19.091 ;
     RECT  42.432 18.853 43.512 19.091 ;
     RECT  98.736 18.563 99.912 19.235 ;
     RECT  24 17.987 24.312 19.237 ;
     RECT  25.344 17.987 25.368 19.237 ;
     RECT  50.688 14.339 51.48 19.237 ;
     RECT  42.432 19.091 43.128 19.283 ;
     RECT  88.8 18.757 91.368 19.571 ;
     RECT  93.984 17.075 96.12 19.811 ;
     RECT  32.928 18.517 33.576 19.861 ;
     RECT  34.8 15.443 36.408 19.861 ;
     RECT  83.184 17.843 85.464 19.861 ;
     RECT  54.288 18.997 62.808 20.051 ;
     RECT  17.472 19.909 17.592 20.053 ;
     RECT  18.6 19.091 19.512 20.053 ;
     RECT  17.472 20.053 19.512 20.099 ;
     RECT  83.184 19.861 86.232 20.099 ;
     RECT  94.2 19.811 96.12 20.099 ;
     RECT  12.48 19.091 13.512 20.149 ;
     RECT  66.672 18.995 69.336 20.197 ;
     RECT  71.76 18.275 75.576 20.243 ;
     RECT  75.552 20.243 75.576 20.389 ;
     RECT  42.576 19.283 43.128 20.437 ;
     RECT  71.76 20.243 74.376 20.485 ;
     RECT  99.504 19.235 99.912 20.485 ;
     RECT  9.84 19.909 9.864 20.579 ;
     RECT  12.48 20.149 13.608 20.579 ;
     RECT  32.928 19.861 36.408 20.579 ;
     RECT  66.672 20.197 69.96 20.579 ;
     RECT  86.208 20.099 86.232 20.579 ;
     RECT  24 19.237 25.368 20.627 ;
     RECT  27.648 19.765 27.672 20.725 ;
     RECT  50.544 19.237 51.48 20.725 ;
     RECT  15.984 18.181 16.008 20.867 ;
     RECT  42.576 20.437 43.368 20.869 ;
     RECT  75.552 20.389 76.344 20.869 ;
     RECT  77.856 18.659 78.312 20.869 ;
     RECT  27.648 20.725 28.344 20.917 ;
     RECT  29.4 13.043 29.712 20.917 ;
     RECT  71.472 20.485 74.376 20.963 ;
     RECT  83.184 20.099 84.648 20.965 ;
     RECT  27.648 20.917 30.504 21.059 ;
     RECT  65.376 18.995 65.544 21.061 ;
     RECT  34.8 20.579 36.408 21.109 ;
     RECT  39.792 18.949 41.448 21.109 ;
     RECT  42.576 20.869 43.464 21.203 ;
     RECT  2.4 13.715 2.712 21.205 ;
     RECT  3.792 20.965 3.816 21.205 ;
     RECT  27.648 21.059 28.344 21.251 ;
     RECT  82.272 20.965 84.648 21.347 ;
     RECT  65.28 21.061 65.544 21.395 ;
     RECT  17.568 20.099 19.512 21.493 ;
     RECT  39.696 21.109 41.448 21.539 ;
     RECT  47.328 18.851 47.352 21.637 ;
     RECT  49.872 20.725 51.48 21.637 ;
     RECT  69.312 20.579 69.96 21.637 ;
     RECT  7.008 18.851 8.112 21.683 ;
     RECT  28.32 21.251 28.344 21.683 ;
     RECT  32.928 20.579 33.624 21.733 ;
     RECT  34.8 21.109 37.176 21.733 ;
     RECT  39.696 21.539 40.512 21.875 ;
     RECT  80.544 18.995 81.288 21.877 ;
     RECT  55.824 20.051 62.808 21.923 ;
     RECT  2.4 21.205 3.816 22.019 ;
     RECT  29.4 21.059 30.504 22.069 ;
     RECT  57.888 21.923 62.808 22.165 ;
     RECT  80.4 21.877 81.288 22.165 ;
     RECT  82.272 21.347 82.296 22.165 ;
     RECT  9.744 21.397 9.768 22.211 ;
     RECT  72.6 20.963 74.376 22.211 ;
     RECT  45.6 18.275 46.248 22.213 ;
     RECT  94.2 20.099 96.072 22.259 ;
     RECT  32.928 21.733 37.176 22.451 ;
     RECT  69.312 21.637 70.104 22.499 ;
     RECT  69.312 22.499 69.96 22.597 ;
     RECT  17.568 21.493 19.896 22.691 ;
     RECT  39.792 21.875 40.512 22.741 ;
     RECT  80.4 22.165 82.296 22.741 ;
     RECT  49.776 21.637 51.48 22.787 ;
     RECT  57.888 22.165 62.904 22.789 ;
     RECT  47.328 21.637 47.736 22.835 ;
     RECT  54.288 20.051 54.312 22.835 ;
     RECT  7.8 21.683 8.112 22.885 ;
     RECT  75.552 20.869 78.312 22.885 ;
     RECT  12.48 20.579 13.512 22.981 ;
     RECT  71.472 20.963 71.496 22.981 ;
     RECT  28.464 22.069 30.504 23.029 ;
     RECT  31.824 22.597 31.848 23.029 ;
     RECT  55.824 21.923 56.712 23.029 ;
     RECT  6.192 22.789 6.216 23.171 ;
     RECT  57.888 22.789 63.24 23.173 ;
     RECT  34.8 22.451 37.176 23.219 ;
     RECT  28.464 23.029 31.848 23.221 ;
     RECT  32.928 22.451 33.624 23.221 ;
     RECT  16.56 22.213 16.584 23.315 ;
     RECT  25.344 20.627 25.368 23.317 ;
     RECT  26.4 22.789 26.712 23.317 ;
     RECT  66.672 20.579 67.608 23.317 ;
     RECT  68.976 22.597 69.96 23.317 ;
     RECT  88.8 19.571 90.936 23.317 ;
     RECT  88.8 23.317 91.656 23.363 ;
     RECT  91.632 23.363 91.656 23.365 ;
     RECT  92.688 13.619 92.712 23.365 ;
     RECT  28.464 23.221 33.624 23.411 ;
     RECT  79.488 22.741 82.296 23.411 ;
     RECT  71.328 22.981 71.496 23.509 ;
     RECT  72.6 22.211 74.328 23.509 ;
     RECT  45.504 22.213 46.248 23.557 ;
     RECT  65.28 21.395 65.448 23.557 ;
     RECT  87.792 22.453 87.816 23.557 ;
     RECT  88.8 23.363 90.36 23.557 ;
     RECT  91.632 23.365 92.712 23.557 ;
     RECT  94.2 22.259 94.92 23.557 ;
     RECT  25.344 23.317 26.712 23.653 ;
     RECT  66.672 23.317 69.96 23.653 ;
     RECT  71.328 23.509 74.328 23.653 ;
     RECT  80.88 23.411 82.296 23.653 ;
     RECT  14.784 23.029 14.808 23.699 ;
     RECT  75.456 22.885 78.312 23.699 ;
     RECT  64.992 23.557 65.448 23.701 ;
     RECT  87.792 23.557 90.36 23.797 ;
     RECT  29.4 23.411 33.624 23.843 ;
     RECT  64.896 23.701 65.448 23.843 ;
     RECT  80.88 23.653 82.392 23.843 ;
     RECT  98.16 22.789 98.184 23.843 ;
     RECT  66.672 23.653 74.328 23.845 ;
     RECT  75.456 23.699 76.488 23.845 ;
     RECT  77.616 23.699 78.312 23.845 ;
     RECT  79.488 23.411 79.848 23.845 ;
     RECT  25.344 23.653 26.76 23.891 ;
     RECT  82.368 23.843 82.392 23.893 ;
     RECT  83.4 21.347 84.648 23.893 ;
     RECT  17.568 22.691 19.032 23.939 ;
     RECT  55.632 23.029 56.712 23.939 ;
     RECT  87.024 23.797 90.36 23.939 ;
     RECT  66.672 23.845 76.488 23.987 ;
     RECT  64.992 23.843 65.448 23.989 ;
     RECT  66.672 23.987 71.352 23.989 ;
     RECT  64.992 23.989 71.352 24.227 ;
     RECT  64.992 24.227 65.016 24.371 ;
     RECT  66.144 24.227 71.352 24.419 ;
     RECT  12.24 22.981 13.512 24.421 ;
     RECT  57.888 23.173 63.72 24.563 ;
     RECT  77.616 23.845 79.848 24.563 ;
     RECT  91.632 23.557 94.92 24.611 ;
     RECT  61.584 24.563 63.72 24.659 ;
     RECT  31.824 23.843 33.624 24.709 ;
     RECT  34.8 23.219 36.408 24.709 ;
     RECT  25.344 23.891 26.712 24.851 ;
     RECT  39.792 22.741 41.256 24.899 ;
     RECT  45.024 23.557 46.248 25.139 ;
     RECT  57.888 24.563 60.216 25.139 ;
     RECT  97.488 24.469 97.512 25.139 ;
     RECT  42.576 21.203 43.128 25.141 ;
     RECT  7.2 22.885 8.112 25.187 ;
     RECT  69.936 24.419 71.352 25.235 ;
     RECT  45.024 25.139 45.912 25.237 ;
     RECT  72.6 23.987 76.488 25.283 ;
     RECT  24 20.627 24.312 25.429 ;
     RECT  25.344 24.851 25.8 25.429 ;
     RECT  2.4 22.019 3.528 25.475 ;
     RECT  49.872 22.787 51.48 25.477 ;
     RECT  31.824 24.709 36.408 25.523 ;
     RECT  2.4 25.475 3.432 25.571 ;
     RECT  24 25.429 25.8 25.571 ;
     RECT  29.4 23.843 30.504 25.571 ;
     RECT  70.08 25.235 71.352 25.573 ;
     RECT  72.6 25.283 75.24 25.573 ;
     RECT  42.576 25.141 43.32 25.619 ;
     RECT  87.024 23.939 90.024 25.715 ;
     RECT  42.576 25.619 43.128 25.717 ;
     RECT  41.856 25.717 43.128 25.859 ;
     RECT  86.016 23.653 86.04 25.861 ;
     RECT  87.024 25.715 87.048 25.861 ;
     RECT  16.272 24.757 16.296 26.005 ;
     RECT  33.408 25.523 36.408 26.051 ;
     RECT  57.888 25.139 58.152 26.099 ;
     RECT  17.568 23.939 18.912 26.101 ;
     RECT  19.92 24.853 19.944 26.101 ;
     RECT  49.872 25.477 52.056 26.101 ;
     RECT  56.4 23.939 56.712 26.101 ;
     RECT  15.696 26.005 16.296 26.147 ;
     RECT  5.952 26.149 5.976 26.197 ;
     RECT  44.976 25.237 45.912 26.197 ;
     RECT  38.016 25.621 38.04 26.243 ;
     RECT  58.128 26.099 58.152 26.243 ;
     RECT  88.272 25.715 90.024 26.339 ;
     RECT  17.568 26.101 19.944 26.531 ;
     RECT  24 25.571 24.312 26.533 ;
     RECT  25.344 25.571 25.8 26.533 ;
     RECT  70.08 25.573 75.24 26.579 ;
     RECT  44.448 26.197 45.912 26.581 ;
     RECT  42.576 25.859 43.128 26.629 ;
     RECT  7.488 25.187 8.112 26.675 ;
     RECT  44.448 26.581 46.248 26.723 ;
     RECT  31.824 25.523 32.328 26.725 ;
     RECT  31.824 26.725 32.376 26.773 ;
     RECT  17.568 26.531 19.368 26.819 ;
     RECT  44.448 26.723 45.912 26.819 ;
     RECT  71.76 26.579 75.24 26.867 ;
     RECT  26.784 26.773 26.808 26.915 ;
     RECT  97.632 26.197 97.656 26.915 ;
     RECT  99.504 20.485 100.104 26.915 ;
     RECT  75.216 26.867 75.24 26.917 ;
     RECT  24 26.533 25.8 26.963 ;
     RECT  42.576 26.629 43.272 27.203 ;
     RECT  88.8 26.339 90.024 27.205 ;
     RECT  4.56 25.525 4.584 27.395 ;
     RECT  5.952 26.197 6.168 27.395 ;
     RECT  33.552 26.051 36.408 27.395 ;
     RECT  49.632 26.101 52.056 27.395 ;
     RECT  55.872 26.101 56.712 27.395 ;
     RECT  71.76 26.867 74.184 27.395 ;
     RECT  80.88 23.843 81.288 27.395 ;
     RECT  93.168 24.611 94.92 27.395 ;
     RECT  86.016 25.861 87.048 27.491 ;
     RECT  70.08 26.579 70.536 27.587 ;
     RECT  82.368 23.893 84.648 27.587 ;
     RECT  29.4 25.571 30.264 27.635 ;
     RECT  31.296 26.773 32.376 27.635 ;
     RECT  77.616 24.563 79.32 27.635 ;
     RECT  77.712 27.635 79.32 27.683 ;
     RECT  88.8 27.205 90.648 27.731 ;
     RECT  11.472 24.421 13.512 27.827 ;
     RECT  6.144 27.395 6.168 27.877 ;
     RECT  17.856 26.819 19.368 27.877 ;
     RECT  44.976 26.819 45.912 27.877 ;
     RECT  59.52 25.139 60.216 27.877 ;
     RECT  93.168 27.395 94.512 27.877 ;
     RECT  6.144 27.877 6.264 27.923 ;
     RECT  66.144 24.419 68.952 27.923 ;
     RECT  71.856 27.395 74.184 27.923 ;
     RECT  17.856 27.877 19.608 27.925 ;
     RECT  24 26.963 25.368 27.971 ;
     RECT  39.792 24.899 40.512 27.971 ;
     RECT  76.464 25.283 76.488 28.211 ;
     RECT  33.84 27.395 36.408 28.259 ;
     RECT  42.576 27.203 43.128 28.357 ;
     RECT  66.144 27.923 68.184 28.403 ;
     RECT  44.976 27.877 46.488 28.405 ;
     RECT  90.624 27.731 90.648 28.499 ;
     RECT  59.328 27.877 60.216 28.547 ;
     RECT  92.928 27.877 94.512 28.643 ;
     RECT  96.048 22.259 96.072 28.931 ;
     RECT  17.04 27.925 19.608 28.979 ;
     RECT  17.76 28.979 19.608 28.981 ;
     RECT  61.632 24.659 63.72 28.981 ;
     RECT  17.76 28.981 19.992 29.027 ;
     RECT  15.696 26.147 15.72 29.029 ;
     RECT  29.4 27.635 29.712 29.029 ;
     RECT  40.08 27.971 40.512 29.029 ;
     RECT  61.632 28.981 63.864 29.029 ;
     RECT  17.76 29.027 18.912 29.075 ;
     RECT  83.04 27.587 84.648 29.075 ;
     RECT  33.84 28.259 35.352 29.077 ;
     RECT  31.68 27.635 32.376 29.123 ;
     RECT  4.608 27.733 4.632 29.171 ;
     RECT  75.216 26.917 75.432 29.173 ;
     RECT  93.168 28.643 94.512 29.363 ;
     RECT  78 27.683 79.32 29.413 ;
     RECT  29.4 29.029 29.928 29.507 ;
     RECT  11.472 27.827 11.496 29.509 ;
     RECT  12.624 27.827 13.512 29.509 ;
     RECT  33.696 29.077 35.352 29.605 ;
     RECT  99.6 26.915 100.104 29.605 ;
     RECT  33.024 29.605 35.352 29.651 ;
     RECT  6.24 27.923 6.264 29.699 ;
     RECT  38.352 28.981 38.376 29.699 ;
     RECT  66.48 28.403 68.184 29.747 ;
     RECT  56.4 27.395 56.712 29.749 ;
     RECT  19.968 29.027 19.992 29.795 ;
     RECT  61.584 29.029 63.864 29.795 ;
     RECT  17.856 29.075 18.912 29.843 ;
     RECT  49.872 27.395 52.056 29.893 ;
     RECT  53.328 24.133 53.352 29.893 ;
     RECT  7.8 26.675 8.112 30.037 ;
     RECT  86.88 27.491 87.048 30.037 ;
     RECT  88.8 27.731 89.256 30.037 ;
     RECT  9.888 29.605 9.912 30.083 ;
     RECT  61.632 29.795 63.864 30.083 ;
     RECT  16.8 29.989 16.824 30.131 ;
     RECT  77.856 29.413 79.32 30.181 ;
     RECT  44.976 28.405 46.632 30.227 ;
     RECT  33.024 29.651 35.304 30.275 ;
     RECT  22.176 29.893 22.2 30.277 ;
     RECT  42.576 28.357 43.32 30.323 ;
     RECT  71.952 27.923 74.184 30.325 ;
     RECT  75.216 29.173 75.864 30.325 ;
     RECT  56.112 29.749 56.712 30.371 ;
     RECT  29.4 29.507 29.712 30.373 ;
     RECT  86.88 30.037 89.256 30.421 ;
     RECT  54.672 27.301 54.696 30.517 ;
     RECT  70.368 27.587 70.536 30.517 ;
     RECT  71.952 30.325 75.864 30.517 ;
     RECT  54.384 30.517 54.696 30.563 ;
     RECT  42.576 30.323 43.128 30.565 ;
     RECT  40.08 29.029 40.968 30.611 ;
     RECT  59.328 28.547 59.832 30.709 ;
     RECT  61.632 30.083 63.72 30.755 ;
     RECT  40.08 30.611 40.512 30.803 ;
     RECT  42.288 30.565 43.128 30.803 ;
     RECT  70.368 30.517 75.864 30.803 ;
     RECT  6.864 30.037 8.112 30.851 ;
     RECT  86.544 30.421 89.256 30.851 ;
     RECT  59.328 30.709 59.88 30.899 ;
     RECT  69.36 29.365 69.384 30.899 ;
     RECT  70.368 30.803 71.4 30.899 ;
     RECT  70.368 30.899 70.392 30.947 ;
     RECT  96.912 29.317 96.936 30.947 ;
     RECT  98.64 29.605 100.104 31.139 ;
     RECT  21.696 30.277 22.2 31.187 ;
     RECT  86.544 30.851 87.144 31.237 ;
     RECT  11.472 29.509 13.512 31.283 ;
     RECT  20.496 30.757 20.52 31.379 ;
     RECT  37.44 30.613 37.464 31.379 ;
     RECT  91.632 24.611 91.656 31.379 ;
     RECT  82.272 29.605 82.296 31.475 ;
     RECT  24 27.971 25.128 31.525 ;
     RECT  49.872 29.893 53.352 31.525 ;
     RECT  24 31.525 25.464 31.571 ;
     RECT  14.976 29.029 15.72 31.619 ;
     RECT  83.4 29.075 84.648 31.621 ;
     RECT  94.08 29.363 94.512 31.715 ;
     RECT  36.384 28.259 36.408 31.763 ;
     RECT  77.568 30.181 79.32 31.813 ;
     RECT  18.6 29.843 18.912 31.861 ;
     RECT  49.584 31.525 53.352 31.907 ;
     RECT  63.12 30.755 63.72 31.955 ;
     RECT  71.376 30.899 71.4 31.955 ;
     RECT  88.8 30.851 89.256 32.053 ;
     RECT  10.224 31.333 10.248 32.195 ;
     RECT  63.312 31.955 63.72 32.195 ;
     RECT  77.472 31.813 79.32 32.195 ;
     RECT  83.28 31.621 84.648 32.293 ;
     RECT  18.48 31.861 18.912 32.339 ;
     RECT  11.472 31.283 11.496 32.437 ;
     RECT  12.528 31.283 13.512 32.483 ;
     RECT  33.84 30.275 35.304 32.485 ;
     RECT  49.584 31.907 52.056 32.531 ;
     RECT  79.296 32.195 79.32 32.723 ;
     RECT  83.28 32.293 85.272 32.723 ;
     RECT  15.312 31.619 15.72 32.725 ;
     RECT  77.472 32.195 78.312 32.771 ;
     RECT  71.472 31.957 71.496 32.917 ;
     RECT  17.088 32.821 17.208 32.963 ;
     RECT  88.464 32.053 89.256 33.013 ;
     RECT  94.2 31.715 94.512 33.013 ;
     RECT  17.088 32.963 17.112 33.061 ;
     RECT  7.392 30.851 8.112 33.107 ;
     RECT  16.992 33.061 17.112 33.107 ;
     RECT  63.312 32.195 63.336 33.107 ;
     RECT  72.6 30.803 75.864 33.107 ;
     RECT  97.2 31.525 97.224 33.107 ;
     RECT  66.48 29.747 67.944 33.155 ;
     RECT  94.08 33.013 94.512 33.155 ;
     RECT  72.6 33.107 75.432 33.203 ;
     RECT  4.944 32.437 4.968 33.251 ;
     RECT  59.328 30.899 59.544 33.251 ;
     RECT  11.376 32.437 11.496 33.299 ;
     RECT  25.44 31.571 25.464 33.299 ;
     RECT  70.752 32.917 71.496 33.299 ;
     RECT  54.384 30.563 54.408 33.301 ;
     RECT  88.224 33.013 89.256 33.347 ;
     RECT  94.2 33.155 94.512 33.397 ;
     RECT  28.944 30.373 29.712 33.445 ;
     RECT  44.976 30.227 46.44 33.541 ;
     RECT  61.632 30.755 62.112 33.587 ;
     RECT  12.768 32.483 13.512 33.589 ;
     RECT  69.36 32.869 69.384 33.635 ;
     RECT  56.4 30.371 56.712 33.637 ;
     RECT  42.576 30.803 43.128 33.683 ;
     RECT  59.472 33.251 59.544 33.683 ;
     RECT  67.2 33.155 67.944 33.683 ;
     RECT  88.224 33.347 89.112 33.779 ;
     RECT  83.4 32.723 85.272 33.827 ;
     RECT  33.84 32.485 35.352 33.973 ;
     RECT  70.752 33.299 70.776 34.115 ;
     RECT  72.6 33.203 74.52 34.115 ;
     RECT  54.336 33.301 54.408 34.117 ;
     RECT  94.2 33.397 94.68 34.213 ;
     RECT  74.016 34.115 74.52 34.259 ;
     RECT  7.8 33.107 8.112 34.309 ;
     RECT  53.328 31.907 53.352 34.309 ;
     RECT  11.472 33.299 11.496 34.355 ;
     RECT  28.944 33.445 29.832 34.355 ;
     RECT  53.04 34.309 53.352 34.355 ;
     RECT  74.496 34.259 74.52 34.355 ;
     RECT  16.992 33.107 17.016 34.357 ;
     RECT  40.2 30.803 40.512 34.357 ;
     RECT  22.992 34.117 23.016 34.451 ;
     RECT  40.08 34.357 40.512 34.597 ;
     RECT  15.312 32.725 16.008 34.643 ;
     RECT  16.992 34.357 17.112 34.691 ;
     RECT  54.336 34.117 55.368 34.691 ;
     RECT  7.8 34.309 8.472 34.741 ;
     RECT  12.528 33.589 13.704 34.787 ;
     RECT  21.696 31.187 21.72 34.835 ;
     RECT  49.584 32.531 51.48 34.835 ;
     RECT  56.4 33.637 57.624 34.835 ;
     RECT  44.64 33.541 46.44 34.931 ;
     RECT  24 31.571 24.312 35.029 ;
     RECT  42.624 33.683 43.128 35.077 ;
     RECT  7.8 34.741 8.664 35.171 ;
     RECT  23.904 35.029 24.312 35.219 ;
     RECT  54.384 34.691 55.368 35.219 ;
     RECT  49.584 34.835 51.312 35.267 ;
     RECT  12.528 34.787 13.512 35.363 ;
     RECT  27.744 33.013 27.768 35.363 ;
     RECT  40.08 34.597 40.92 35.363 ;
     RECT  44.64 34.931 45.912 35.363 ;
     RECT  94.2 34.213 95.16 35.363 ;
     RECT  15.312 34.643 15.72 35.411 ;
     RECT  25.824 33.589 25.848 35.603 ;
     RECT  29.4 34.355 29.832 35.605 ;
     RECT  31.68 29.123 31.704 35.747 ;
     RECT  29.088 35.605 29.832 35.795 ;
     RECT  59.472 33.683 59.496 35.939 ;
     RECT  86.304 31.237 87.144 35.939 ;
     RECT  86.304 35.939 86.328 35.987 ;
     RECT  49.584 35.267 49.896 36.083 ;
     RECT  45.168 35.363 45.912 36.227 ;
     RECT  33.84 33.973 35.88 36.421 ;
     RECT  91.776 33.973 91.8 36.421 ;
     RECT  49.584 36.083 49.608 36.467 ;
     RECT  91.776 36.421 92.04 36.467 ;
     RECT  33.84 36.421 36.216 36.469 ;
     RECT  22.176 35.509 22.2 36.515 ;
     RECT  53.04 34.355 53.064 36.851 ;
     RECT  29.4 35.795 29.832 36.853 ;
     RECT  16.992 34.691 17.016 36.949 ;
     RECT  29.04 36.853 29.832 36.995 ;
     RECT  15.696 35.411 15.72 36.997 ;
     RECT  16.992 36.949 17.112 36.997 ;
     RECT  40.08 35.363 40.512 36.997 ;
     RECT  96.912 36.229 96.936 36.997 ;
     RECT  33.024 36.469 36.216 37.043 ;
     RECT  96.912 36.997 97.416 37.043 ;
     RECT  15.696 36.997 17.112 37.091 ;
     RECT  16.416 37.091 17.112 37.093 ;
     RECT  16.416 37.093 17.256 37.477 ;
     RECT  16.416 37.477 17.304 37.573 ;
     RECT  22.8 37.381 22.824 37.619 ;
     RECT  39.12 36.997 40.512 37.619 ;
     RECT  40.08 37.619 40.512 37.667 ;
     RECT  33.84 37.043 36.216 37.859 ;
     RECT  54.384 35.219 54.408 37.907 ;
     RECT  16.416 37.573 17.544 38.099 ;
     RECT  97.392 37.043 97.416 38.099 ;
     RECT  33.84 37.859 35.88 38.243 ;
     RECT  17.232 38.099 17.544 38.675 ;
     RECT  30.912 37.141 30.936 38.677 ;
     RECT  38.736 37.669 39.048 38.677 ;
     RECT  47.712 22.835 47.736 38.773 ;
     RECT  17.232 38.675 17.304 38.819 ;
     RECT  17.232 38.819 17.256 38.915 ;
     RECT  38.736 38.677 39.192 38.963 ;
     RECT  44.448 37.957 44.472 39.061 ;
     RECT  30.816 38.677 30.936 39.107 ;
     RECT  39.024 38.963 39.192 39.107 ;
     RECT  29.4 36.995 29.832 39.251 ;
     RECT  44.448 39.061 44.568 39.251 ;
     RECT  47.712 38.773 47.928 39.251 ;
     RECT  32.736 38.437 32.76 39.395 ;
     RECT  47.904 39.251 47.928 39.491 ;
     RECT  34.8 38.243 35.88 39.493 ;
     RECT  28.224 38.725 28.248 39.635 ;
     RECT  31.392 39.253 31.416 39.923 ;
     RECT  39.024 39.107 39.048 40.259 ;
     RECT  95.76 39.877 95.784 40.883 ;
     RECT  42.624 35.077 43.272 40.931 ;
     RECT  99.6 31.139 100.104 41.651 ;
     RECT  34.8 39.493 36.312 41.699 ;
     RECT  36.288 41.699 36.312 41.891 ;
     RECT  83.4 33.827 84.648 41.939 ;
     RECT  83.4 41.939 84.552 42.323 ;
     RECT  42.624 40.931 43.128 42.707 ;
     RECT  97.344 40.837 97.368 44.533 ;
     RECT  42.624 42.707 43.08 44.579 ;
     RECT  96.96 44.533 97.368 44.579 ;
     RECT  96.96 44.579 96.984 44.629 ;
     RECT  98.352 41.605 98.376 44.675 ;
     RECT  96.336 44.629 96.984 46.067 ;
     RECT  43.056 44.579 43.08 47.075 ;
     RECT  92.016 36.467 92.04 47.171 ;
     RECT  96.768 46.067 96.984 47.269 ;
     RECT  20.352 38.917 20.376 47.363 ;
     RECT  96.72 47.269 96.984 47.363 ;
     RECT  83.4 42.323 84.168 47.987 ;
     RECT  96.72 47.363 96.792 48.421 ;
     RECT  81.264 27.395 81.288 51.299 ;
     RECT  95.76 48.421 96.792 52.211 ;
     RECT  96.72 52.211 96.792 53.365 ;
     RECT  96.288 53.365 96.792 54.179 ;
     RECT  96.72 54.179 96.792 56.389 ;
     RECT  95.76 56.389 96.792 59.315 ;
     RECT  6.48 36.133 6.504 61.715 ;
     RECT  98.208 62.245 98.232 62.581 ;
     RECT  99.6 41.651 99.912 62.581 ;
     RECT  98.208 62.581 99.912 62.819 ;
     RECT  98.208 62.819 98.232 63.587 ;
     RECT  95.808 59.315 96.792 64.691 ;
     RECT  95.808 64.691 96.552 67.381 ;
     RECT  98.208 67.333 98.232 67.381 ;
     RECT  95.808 67.381 98.232 67.859 ;
     RECT  98.208 67.859 98.232 68.435 ;
     RECT  95.808 67.859 96.552 68.915 ;
     RECT  96.528 68.915 96.552 68.963 ;
     RECT  2.4 25.571 2.712 69.129 ;
     RECT  7.8 35.171 8.112 69.129 ;
     RECT  13.2 35.363 13.512 69.129 ;
     RECT  18.6 32.339 18.912 69.129 ;
     RECT  24 35.219 24.312 69.129 ;
     RECT  29.4 39.251 29.712 69.129 ;
     RECT  34.8 41.699 35.112 69.129 ;
     RECT  40.2 37.667 40.512 69.129 ;
     RECT  45.6 36.227 45.912 69.129 ;
     RECT  51 35.267 51.312 69.129 ;
     RECT  56.4 34.835 56.712 69.129 ;
     RECT  61.8 33.587 62.112 69.129 ;
     RECT  67.2 33.683 67.512 69.129 ;
     RECT  72.6 34.115 72.912 69.129 ;
     RECT  78 32.771 78.312 69.129 ;
     RECT  83.4 47.987 83.712 69.129 ;
     RECT  88.8 33.779 89.112 69.129 ;
     RECT  94.2 35.363 94.512 69.129 ;
     RECT  99.6 62.819 99.912 69.129 ;
     RECT  2.4 69.129 2.52 69.143 ;
     RECT  7.8 69.129 7.92 69.143 ;
     RECT  13.2 69.129 13.32 69.143 ;
     RECT  18.6 69.129 18.72 69.143 ;
     RECT  24 69.129 24.12 69.143 ;
     RECT  29.4 69.129 29.52 69.143 ;
     RECT  34.8 69.129 34.92 69.143 ;
     RECT  40.2 69.129 40.32 69.143 ;
     RECT  83.4 69.129 83.52 69.143 ;
     RECT  88.8 69.129 88.92 69.143 ;
     RECT  94.2 69.129 94.32 69.143 ;
     RECT  99.6 69.129 99.72 69.143 ;
     RECT  95.4 0.659 96.672 1.139 ;
     RECT  61.944 1.139 62.928 1.763 ;
     RECT  97.944 1.139 98.976 1.187 ;
     RECT  31.032 1.187 32.304 1.763 ;
     RECT  62.952 1.187 63.984 1.763 ;
     RECT  92.856 1.187 93.84 4.019 ;
     RECT  15.96 1.763 17.232 2.915 ;
     RECT  26.208 1.763 26.4 2.821 ;
     RECT  30.024 1.763 31.008 2.915 ;
     RECT  58.344 1.763 59.616 2.915 ;
     RECT  59.64 1.763 60.912 1.811 ;
     RECT  61.944 1.763 62.112 2.151 ;
     RECT  76.776 1.763 78 2.915 ;
     RECT  78.408 1.763 79.536 1.811 ;
     RECT  17.256 2.137 18.6 2.915 ;
     RECT  17.712 2.915 18.6 4.117 ;
     RECT  3.144 3.349 4.272 4.501 ;
     RECT  35.112 3.731 35.208 5.029 ;
     RECT  92.856 4.019 93.936 5.123 ;
     RECT  49.128 4.021 50.592 4.403 ;
     RECT  40.92 4.501 42.144 5.269 ;
     RECT  18.912 4.645 20.064 6.805 ;
     RECT  28.344 4.645 29.4 4.693 ;
     RECT  51.312 4.837 52.512 5.027 ;
     RECT  28.344 4.883 29.4 6.901 ;
     RECT  35.112 5.029 36.576 5.461 ;
     RECT  92.856 5.123 93.984 5.651 ;
     RECT  11.736 5.173 13.2 5.701 ;
     RECT  41.016 5.269 42.144 5.459 ;
     RECT  40.92 5.459 42.144 6.899 ;
     RECT  35.112 5.461 36.528 8.003 ;
     RECT  36.552 5.507 36.696 5.749 ;
     RECT  92.856 5.651 94.08 5.747 ;
     RECT  11.736 5.701 13.104 6.037 ;
     RECT  36.552 5.749 37.92 6.805 ;
     RECT  59.544 5.941 60.576 6.803 ;
     RECT  60.6 5.941 61.584 6.277 ;
     RECT  85.896 5.989 87.216 6.179 ;
     RECT  11.736 6.037 13.056 6.851 ;
     RECT  53.784 6.037 54.816 6.227 ;
     RECT  54.672 6.227 54.816 7.237 ;
     RECT  4.536 6.229 5.952 6.565 ;
     RECT  77.712 6.563 78 6.853 ;
     RECT  33.576 6.709 34.8 7.957 ;
     RECT  54.84 6.805 56.016 7.381 ;
     RECT  11.736 6.851 13.2 7.957 ;
     RECT  76.872 6.853 78 7.139 ;
     RECT  40.92 6.899 42.624 8.149 ;
     RECT  69.288 7.093 70.656 8.003 ;
     RECT  65.28 7.379 65.304 7.957 ;
     RECT  12.072 7.957 13.2 8.099 ;
     RECT  33.672 7.957 34.8 9.349 ;
     RECT  47.928 7.957 48.96 8.819 ;
     RECT  65.28 7.957 65.328 8.725 ;
     RECT  70.68 7.957 72.096 8.003 ;
     RECT  35.112 8.003 36.672 8.675 ;
     RECT  69.288 8.003 72.096 8.389 ;
     RECT  50.592 8.051 51 8.581 ;
     RECT  11.736 8.099 13.2 10.213 ;
     RECT  41.112 8.149 42.624 8.437 ;
     RECT  45.912 8.197 47.376 8.677 ;
     RECT  69.288 8.389 70.704 9.013 ;
     RECT  70.728 8.389 72.096 9.155 ;
     RECT  41.64 8.437 42.624 8.581 ;
     RECT  6.312 8.485 7.8 10.261 ;
     RECT  58.392 8.485 59.52 9.013 ;
     RECT  49.608 8.581 51 9.013 ;
     RECT  35.112 8.675 35.544 9.349 ;
     RECT  45.912 8.677 47.232 10.597 ;
     RECT  66.168 8.725 67.2 8.965 ;
     RECT  41.64 8.819 42.624 9.971 ;
     RECT  65.544 9.011 66.528 10.019 ;
     RECT  49.608 9.013 50.832 9.155 ;
     RECT  69.288 9.013 70.56 9.589 ;
     RECT  94.512 9.061 95.76 9.299 ;
     RECT  95.784 9.061 97.296 9.299 ;
     RECT  50.544 9.155 50.832 10.069 ;
     RECT  70.584 9.155 72.096 9.973 ;
     RECT  2.712 9.251 4.272 9.443 ;
     RECT  54.696 9.251 55.728 11.173 ;
     RECT  94.512 9.299 95.16 9.349 ;
     RECT  73.656 9.349 74.736 10.213 ;
     RECT  2.712 9.443 2.808 10.693 ;
     RECT  69.288 9.589 70.464 10.501 ;
     RECT  59.544 9.637 61.008 10.355 ;
     RECT  25.608 9.779 26.784 12.563 ;
     RECT  58.704 9.923 58.848 11.173 ;
     RECT  42.648 9.925 43.92 9.971 ;
     RECT  41.64 9.971 43.92 10.213 ;
     RECT  70.584 9.973 71.76 14.819 ;
     RECT  50.544 10.069 50.64 10.213 ;
     RECT  81.288 10.069 82.608 12.563 ;
     RECT  92.712 10.069 93.84 10.645 ;
     RECT  12.024 10.213 13.2 10.931 ;
     RECT  41.64 10.213 42.72 10.883 ;
     RECT  42.744 10.213 43.92 10.453 ;
     RECT  67.512 10.213 68.976 11.027 ;
     RECT  6.792 10.261 7.8 12.131 ;
     RECT  13.512 10.261 14.928 11.365 ;
     RECT  24.504 10.307 25.584 13.091 ;
     RECT  44.472 10.597 45.6 11.267 ;
     RECT  74.76 10.597 76.08 10.883 ;
     RECT  76.584 10.597 78 11.509 ;
     RECT  92.712 10.645 93.792 11.797 ;
     RECT  23.856 10.835 24 11.365 ;
     RECT  39.312 10.883 40.032 11.941 ;
     RECT  73.656 10.883 76.08 12.325 ;
     RECT  11.736 10.931 13.2 12.035 ;
     RECT  67.512 11.027 69.264 11.365 ;
     RECT  53.448 11.173 54.672 12.275 ;
     RECT  13.512 11.365 14.88 13.045 ;
     RECT  22.92 11.365 24 12.563 ;
     RECT  68.28 11.365 69.264 12.035 ;
     RECT  84.648 11.365 86.064 11.701 ;
     RECT  97.32 11.365 98.64 11.459 ;
     RECT  45.912 11.459 47.376 16.453 ;
     RECT  69.288 11.459 70.56 12.035 ;
     RECT  97.296 11.459 98.64 11.941 ;
     RECT  57.48 11.461 58.656 11.941 ;
     RECT  92.352 11.603 92.688 12.517 ;
     RECT  19.56 11.701 20.544 11.843 ;
     RECT  8.112 11.941 9.456 12.563 ;
     RECT  38.904 11.941 40.032 12.755 ;
     RECT  59.544 11.941 61.008 13.093 ;
     RECT  97.296 11.941 97.584 12.469 ;
     RECT  97.608 11.941 98.64 12.563 ;
     RECT  33.576 11.987 34.8 14.821 ;
     RECT  89.496 11.987 90.12 12.517 ;
     RECT  13.104 12.035 13.2 12.565 ;
     RECT  68.28 12.035 68.856 12.517 ;
     RECT  51.48 12.181 52.464 13.667 ;
     RECT  35.592 12.325 36.768 12.515 ;
     RECT  74.568 12.325 76.08 13.285 ;
     RECT  17.256 12.421 18.48 13.043 ;
     RECT  35.592 12.515 36.408 12.853 ;
     RECT  41.112 12.517 42.624 12.997 ;
     RECT  89.496 12.517 91.2 12.805 ;
     RECT  91.224 12.517 92.688 17.461 ;
     RECT  22.992 12.563 24 12.853 ;
     RECT  25.608 12.563 26.232 13.525 ;
     RECT  81.288 12.563 82.896 13.621 ;
     RECT  39.792 12.755 40.032 13.621 ;
     RECT  95.16 12.757 96.624 13.045 ;
     RECT  89.496 12.805 90.48 12.947 ;
     RECT  23.016 12.853 24 14.147 ;
     RECT  89.352 12.947 90.48 15.013 ;
     RECT  41.112 12.997 42.576 17.605 ;
     RECT  17.232 13.043 18.48 13.285 ;
     RECT  13.512 13.045 14.832 13.331 ;
     RECT  24.312 13.091 25.584 14.099 ;
     RECT  59.64 13.093 61.008 13.139 ;
     RECT  59.64 13.139 59.736 14.197 ;
     RECT  17.016 13.285 18.48 13.427 ;
     RECT  75.096 13.285 76.08 14.099 ;
     RECT  13.512 13.331 14.928 14.867 ;
     RECT  92.712 13.619 93.744 14.627 ;
     RECT  81.528 13.621 82.896 14.339 ;
     RECT  19.56 13.669 20.784 14.819 ;
     RECT  24.312 14.099 25.728 14.389 ;
     RECT  74.568 14.099 76.08 14.291 ;
     RECT  49.416 14.339 50.688 15.491 ;
     RECT  81.288 14.339 82.896 15.397 ;
     RECT  24.408 14.389 25.728 15.301 ;
     RECT  62.808 14.627 62.952 16.021 ;
     RECT  92.712 14.627 93.984 19.811 ;
     RECT  79.272 14.629 80.64 14.771 ;
     RECT  78.312 14.771 78.408 15.733 ;
     RECT  47.88 14.773 49.392 15.491 ;
     RECT  70.488 14.819 71.76 18.995 ;
     RECT  33.576 14.821 34.56 15.443 ;
     RECT  97.608 14.917 98.64 15.443 ;
     RECT  59.64 15.203 59.736 15.829 ;
     RECT  89.352 15.203 90.336 16.453 ;
     RECT  81.288 15.397 82.656 15.781 ;
     RECT  33.576 15.443 34.8 19.861 ;
     RECT  87.816 15.683 88.8 16.837 ;
     RECT  86.424 15.733 87.744 17.171 ;
     RECT  59.64 15.829 60.624 18.997 ;
     RECT  51.48 15.877 52.944 16.595 ;
     RECT  52.968 15.877 54.288 16.595 ;
     RECT  74.568 15.877 75.744 17.605 ;
     RECT  81.528 15.923 82.896 17.843 ;
     RECT  45.912 16.453 47.328 17.029 ;
     RECT  63.624 16.597 65.088 16.739 ;
     RECT  64.992 16.739 65.088 17.845 ;
     RECT  69.696 16.835 69.888 16.837 ;
     RECT  67.512 16.837 68.592 17.509 ;
     RECT  68.616 16.837 69.888 16.883 ;
     RECT  68.616 16.883 70.464 17.893 ;
     RECT  38.376 16.981 39.792 18.995 ;
     RECT  46.104 17.029 47.328 17.605 ;
     RECT  32.928 17.459 33.504 18.517 ;
     RECT  89.112 17.459 90.336 18.757 ;
     RECT  91.368 17.461 92.688 19.571 ;
     RECT  41.112 17.605 42.432 18.949 ;
     RECT  46.248 17.605 47.328 22.835 ;
     RECT  74.568 17.605 75.552 18.229 ;
     RECT  75.768 17.699 77.088 18.275 ;
     RECT  69.336 17.893 70.464 18.995 ;
     RECT  24.312 17.987 25.344 19.237 ;
     RECT  47.688 18.181 48.96 18.851 ;
     RECT  75.576 18.275 77.088 18.659 ;
     RECT  41.448 18.949 42.432 19.283 ;
     RECT  65.544 18.995 66.672 21.395 ;
     RECT  69.336 18.995 71.76 20.197 ;
     RECT  13.512 19.091 13.608 20.149 ;
     RECT  18.48 19.091 18.6 19.909 ;
     RECT  43.128 19.091 43.368 20.437 ;
     RECT  41.448 19.283 42.576 21.539 ;
     RECT  92.712 19.811 94.2 23.557 ;
     RECT  16.008 19.909 17.472 20.099 ;
     RECT  17.592 19.909 18.6 20.053 ;
     RECT  54.312 20.051 55.824 22.835 ;
     RECT  69.96 20.197 71.76 20.485 ;
     RECT  74.376 20.243 75.552 22.211 ;
     RECT  76.344 20.389 77.856 20.869 ;
     RECT  69.96 20.485 71.472 21.637 ;
     RECT  33.624 20.579 34.8 21.733 ;
     RECT  24.312 20.627 25.344 25.429 ;
     RECT  28.344 20.725 29.4 20.917 ;
     RECT  71.496 20.963 72.6 23.509 ;
     RECT  2.712 20.965 3.792 21.205 ;
     RECT  81.288 20.965 82.272 22.165 ;
     RECT  28.344 21.059 29.4 21.683 ;
     RECT  82.296 21.347 83.4 23.653 ;
     RECT  65.448 21.395 66.672 23.989 ;
     RECT  40.512 21.539 42.576 22.741 ;
     RECT  70.104 21.637 71.472 22.499 ;
     RECT  7.008 21.683 7.8 22.789 ;
     RECT  28.464 21.683 29.4 22.069 ;
     RECT  56.712 21.923 57.888 26.099 ;
     RECT  74.328 22.211 75.552 22.885 ;
     RECT  16.584 22.213 17.568 23.315 ;
     RECT  94.92 22.259 96.048 27.395 ;
     RECT  33.624 22.451 34.8 24.709 ;
     RECT  87.816 22.453 88.8 23.557 ;
     RECT  69.96 22.499 71.472 22.981 ;
     RECT  30.504 22.597 31.824 23.029 ;
     RECT  31.848 22.597 32.928 23.221 ;
     RECT  67.608 22.597 68.976 23.317 ;
     RECT  41.256 22.741 42.576 24.899 ;
     RECT  78.312 22.741 79.488 23.845 ;
     RECT  6.216 22.789 7.8 22.885 ;
     RECT  25.368 22.789 26.4 23.317 ;
     RECT  98.184 22.789 99.504 23.843 ;
     RECT  46.248 22.835 47.712 25.139 ;
     RECT  55.632 22.835 55.824 23.029 ;
     RECT  6.216 22.885 7.2 23.171 ;
     RECT  74.328 22.885 75.456 23.845 ;
     RECT  69.96 22.981 71.328 23.653 ;
     RECT  13.512 23.029 14.784 23.699 ;
     RECT  16.56 23.315 17.568 24.757 ;
     RECT  91.656 23.317 92.688 23.365 ;
     RECT  90.36 23.363 91.632 23.939 ;
     RECT  79.848 23.411 80.88 24.563 ;
     RECT  63.72 23.557 64.992 23.701 ;
     RECT  82.392 23.653 83.4 23.893 ;
     RECT  84.648 23.653 86.016 27.491 ;
     RECT  76.488 23.699 77.616 27.635 ;
     RECT  63.72 23.701 64.896 23.843 ;
     RECT  86.04 23.797 87.024 25.861 ;
     RECT  30.504 23.843 31.824 25.571 ;
     RECT  63.72 23.843 64.992 24.371 ;
     RECT  81.288 23.843 82.368 27.587 ;
     RECT  18.912 23.939 19.032 24.853 ;
     RECT  71.352 23.987 72.6 25.573 ;
     RECT  65.016 24.227 66.144 24.371 ;
     RECT  68.952 24.419 69.936 25.235 ;
     RECT  96.072 24.469 97.488 25.139 ;
     RECT  60.216 24.563 61.584 24.659 ;
     RECT  91.656 24.611 93.168 27.877 ;
     RECT  60.216 24.659 61.632 28.547 ;
     RECT  16.296 24.757 17.568 26.147 ;
     RECT  18.912 24.853 19.92 26.101 ;
     RECT  40.512 24.899 42.576 25.717 ;
     RECT  45.912 25.139 47.712 26.581 ;
     RECT  58.152 25.139 59.52 26.243 ;
     RECT  7.2 25.187 7.488 26.149 ;
     RECT  68.952 25.235 70.08 27.587 ;
     RECT  75.24 25.283 76.464 26.917 ;
     RECT  3.432 25.475 3.528 25.525 ;
     RECT  52.056 25.477 53.328 29.893 ;
     RECT  32.328 25.523 33.408 26.051 ;
     RECT  3.432 25.525 4.56 25.571 ;
     RECT  24.312 25.571 25.344 26.533 ;
     RECT  30.264 25.571 31.824 26.773 ;
     RECT  43.128 25.619 43.32 26.197 ;
     RECT  87.048 25.715 88.272 26.339 ;
     RECT  40.512 25.717 41.856 25.859 ;
     RECT  32.328 26.051 33.552 26.725 ;
     RECT  56.712 26.099 58.128 26.243 ;
     RECT  4.584 26.149 5.952 27.395 ;
     RECT  5.976 26.149 7.488 26.197 ;
     RECT  6.168 26.197 7.488 26.675 ;
     RECT  43.128 26.197 44.448 26.629 ;
     RECT  19.368 26.531 19.608 27.877 ;
     RECT  70.536 26.579 71.76 27.395 ;
     RECT  46.248 26.581 47.712 26.723 ;
     RECT  43.272 26.629 44.448 26.819 ;
     RECT  6.168 26.675 6.264 27.877 ;
     RECT  45.912 26.723 47.712 27.877 ;
     RECT  32.376 26.725 33.552 27.395 ;
     RECT  25.8 26.773 26.784 26.915 ;
     RECT  30.264 26.773 31.296 27.635 ;
     RECT  17.568 26.819 17.856 27.925 ;
     RECT  74.184 26.867 75.216 30.325 ;
     RECT  75.432 26.917 76.464 28.211 ;
     RECT  43.128 27.203 43.272 28.357 ;
     RECT  90.648 27.205 91.632 28.499 ;
     RECT  53.352 27.301 54.672 30.517 ;
     RECT  54.696 27.301 55.872 27.395 ;
     RECT  4.608 27.395 6.144 27.733 ;
     RECT  32.376 27.395 33.84 29.077 ;
     RECT  70.536 27.395 71.856 27.923 ;
     RECT  68.952 27.587 70.368 27.923 ;
     RECT  29.712 27.635 29.928 29.029 ;
     RECT  76.488 27.635 77.712 27.683 ;
     RECT  76.488 27.683 78 28.211 ;
     RECT  89.256 27.731 90.624 28.499 ;
     RECT  4.632 27.733 6.144 27.923 ;
     RECT  11.496 27.827 12.624 29.509 ;
     RECT  46.488 27.877 47.712 28.405 ;
     RECT  91.656 27.877 92.928 28.643 ;
     RECT  68.184 27.923 70.368 29.365 ;
     RECT  70.536 27.923 71.952 30.517 ;
     RECT  15.72 27.925 17.04 28.979 ;
     RECT  75.432 28.211 75.864 29.173 ;
     RECT  77.856 28.211 78 29.413 ;
     RECT  35.352 28.259 36.384 29.651 ;
     RECT  46.632 28.405 47.712 30.227 ;
     RECT  61.584 28.547 61.632 29.029 ;
     RECT  91.656 28.643 93.168 29.363 ;
     RECT  15.72 28.979 17.76 29.075 ;
     RECT  18.912 29.027 19.968 29.795 ;
     RECT  13.512 29.029 14.976 31.619 ;
     RECT  15.72 29.075 17.856 29.843 ;
     RECT  83.04 29.075 83.4 29.605 ;
     RECT  32.376 29.077 33.696 29.123 ;
     RECT  31.704 29.123 33.696 29.605 ;
     RECT  68.184 29.365 69.36 29.747 ;
     RECT  69.384 29.365 70.368 30.899 ;
     RECT  31.704 29.605 33.024 30.275 ;
     RECT  81.288 29.605 82.272 31.475 ;
     RECT  82.296 29.605 83.4 31.475 ;
     RECT  35.304 29.651 36.384 31.763 ;
     RECT  67.944 29.747 69.36 30.899 ;
     RECT  54.696 29.749 56.112 30.371 ;
     RECT  15.72 29.843 16.824 29.989 ;
     RECT  15.72 29.989 16.8 30.131 ;
     RECT  46.44 30.227 47.712 34.931 ;
     RECT  53.352 30.517 54.384 33.301 ;
     RECT  40.968 30.565 42.288 30.611 ;
     RECT  36.408 30.613 37.44 31.379 ;
     RECT  62.112 30.755 63.12 31.955 ;
     RECT  20.52 30.757 21.696 31.379 ;
     RECT  71.4 30.803 72.6 31.955 ;
     RECT  87.144 30.851 88.8 32.053 ;
     RECT  70.392 30.899 71.376 30.947 ;
     RECT  11.496 31.283 12.528 32.483 ;
     RECT  10.248 31.333 11.472 32.195 ;
     RECT  83.28 31.475 83.4 31.621 ;
     RECT  24.312 31.571 25.44 33.299 ;
     RECT  94.08 31.715 94.2 33.013 ;
     RECT  35.304 31.763 35.352 32.485 ;
     RECT  52.056 31.907 53.328 32.531 ;
     RECT  62.112 31.955 63.312 33.107 ;
     RECT  71.376 31.955 72.6 31.957 ;
     RECT  71.376 31.957 71.472 32.917 ;
     RECT  71.496 31.957 72.6 33.299 ;
     RECT  87.144 32.053 88.464 33.013 ;
     RECT  11.376 32.195 11.472 32.437 ;
     RECT  78.312 32.195 79.296 32.723 ;
     RECT  85.272 32.293 86.304 33.827 ;
     RECT  18.48 32.339 18.6 32.821 ;
     RECT  11.496 32.483 12.768 33.589 ;
     RECT  16.008 32.821 17.088 33.061 ;
     RECT  17.208 32.821 18.6 32.963 ;
     RECT  67.944 32.869 69.36 33.635 ;
     RECT  69.384 32.917 70.752 33.635 ;
     RECT  17.112 32.963 18.6 33.107 ;
     RECT  27.768 33.013 28.944 34.355 ;
     RECT  87.144 33.013 88.224 33.779 ;
     RECT  16.008 33.061 16.992 34.643 ;
     RECT  17.016 33.107 18.6 34.357 ;
     RECT  24.312 33.299 25.464 33.589 ;
     RECT  53.352 33.301 54.336 34.355 ;
     RECT  43.128 33.541 44.64 35.077 ;
     RECT  11.496 33.589 12.528 34.355 ;
     RECT  24.312 33.589 25.824 35.603 ;
     RECT  72.912 34.115 74.016 34.259 ;
     RECT  21.72 34.117 22.992 34.451 ;
     RECT  23.016 34.117 24 34.451 ;
     RECT  55.368 34.117 56.4 35.219 ;
     RECT  27.768 34.355 29.4 35.363 ;
     RECT  53.064 34.355 54.336 34.691 ;
     RECT  17.112 34.357 18.6 34.691 ;
     RECT  21.72 34.451 22.2 34.835 ;
     RECT  23.904 34.451 24 35.029 ;
     RECT  15.72 34.643 16.992 36.997 ;
     RECT  53.064 34.691 54.384 36.851 ;
     RECT  22.176 34.835 22.2 35.509 ;
     RECT  43.272 35.077 44.64 35.363 ;
     RECT  49.896 35.267 51 36.083 ;
     RECT  29.04 35.363 29.4 35.605 ;
     RECT  29.04 35.605 29.088 35.795 ;
     RECT  29.04 35.795 29.4 36.853 ;
     RECT  49.608 36.083 51 36.467 ;
     RECT  6.504 36.133 7.8 61.715 ;
     RECT  17.112 36.949 18.6 37.093 ;
     RECT  17.256 37.093 18.6 37.477 ;
     RECT  29.832 37.141 30.912 38.677 ;
     RECT  22.824 37.381 24 37.619 ;
     RECT  17.304 37.477 18.6 37.573 ;
     RECT  17.544 37.573 18.6 38.675 ;
     RECT  39.12 37.619 40.08 37.667 ;
     RECT  39.12 37.667 40.2 37.669 ;
     RECT  39.048 37.669 40.2 38.677 ;
     RECT  43.272 37.957 44.448 39.251 ;
     RECT  44.472 37.957 45.6 39.061 ;
     RECT  17.304 38.675 18.6 38.819 ;
     RECT  29.832 38.677 30.816 39.107 ;
     RECT  39.192 38.677 40.2 39.107 ;
     RECT  28.248 38.725 29.4 39.635 ;
     RECT  17.256 38.819 18.6 38.915 ;
     RECT  18.912 38.917 20.352 47.363 ;
     RECT  44.568 39.061 45.6 39.251 ;
     RECT  39.048 39.107 40.2 40.259 ;
     RECT  31.416 39.253 32.736 39.395 ;
     RECT  94.512 39.877 95.76 40.883 ;
     RECT  97.368 41.605 98.352 44.579 ;
     RECT  98.376 41.605 99.6 44.675 ;
     RECT  35.112 41.699 36.288 41.891 ;
     RECT  96.984 44.579 98.352 44.675 ;
     RECT  96.72 46.067 96.768 47.269 ;
     RECT  94.512 48.421 95.76 52.211 ;
     RECT  96.288 52.211 96.72 53.365 ;
     RECT  94.512 56.389 95.76 59.315 ;
     RECT  94.512 59.315 95.808 68.915 ;
     RECT  96.792 62.245 98.208 63.587 ;
     RECT  98.232 62.245 99.6 62.581 ;
     RECT  98.232 62.819 99.6 63.587 ;
     RECT  98.232 67.333 99.6 68.435 ;
  END
END ot_hgi_coll_fj_n1s0_r128
END LIBRARY
